VERSION 5.8 ;
BUSBITCHARS "[]" ;
DIVIDERCHAR "/" ;
UNITS
    DATABASE MICRONS 1000 ;
END UNITS

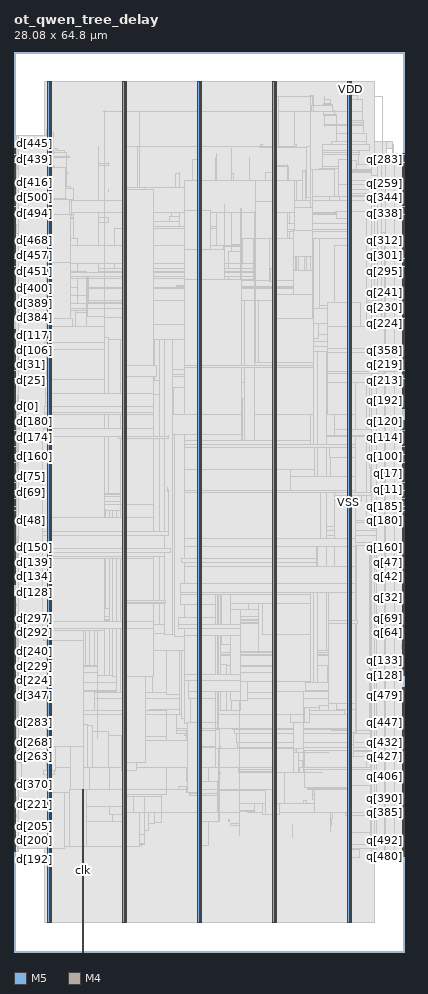
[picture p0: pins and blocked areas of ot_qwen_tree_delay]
MACRO ot_qwen_tree_delay
  FOREIGN ot_qwen_tree_delay 0 0 ;
  CLASS BLOCK ;
  SIZE 28.08 BY 64.8 ;
  PIN clk
    DIRECTION INPUT ;
    USE SIGNAL ;
    PORT
      LAYER M5 ;
        RECT  4.944 0 4.968 0.084 ;
    END
    PORT
      LAYER M5 ;
        RECT  4.944 0.016 4.968 11.701 ;
    END
  END clk
  PIN d[0]
    DIRECTION INPUT ;
    USE SIGNAL ;
    PORT
      LAYER M4 ;
        RECT  0 38.736 0.084 38.76 ;
    END
  END d[0]
  PIN d[100]
    DIRECTION INPUT ;
    USE SIGNAL ;
    PORT
      LAYER M4 ;
        RECT  0 42.192 0.084 42.216 ;
    END
  END d[100]
  PIN d[101]
    DIRECTION INPUT ;
    USE SIGNAL ;
    PORT
      LAYER M4 ;
        RECT  0 42.288 0.084 42.312 ;
    END
  END d[101]
  PIN d[102]
    DIRECTION INPUT ;
    USE SIGNAL ;
    PORT
      LAYER M4 ;
        RECT  0 42.384 0.084 42.408 ;
    END
  END d[102]
  PIN d[103]
    DIRECTION INPUT ;
    USE SIGNAL ;
    PORT
      LAYER M4 ;
        RECT  0 42.48 0.084 42.504 ;
    END
  END d[103]
  PIN d[104]
    DIRECTION INPUT ;
    USE SIGNAL ;
    PORT
      LAYER M4 ;
        RECT  0 42.576 0.084 42.6 ;
    END
  END d[104]
  PIN d[105]
    DIRECTION INPUT ;
    USE SIGNAL ;
    PORT
      LAYER M4 ;
        RECT  0 42.672 0.084 42.696 ;
    END
  END d[105]
  PIN d[106]
    DIRECTION INPUT ;
    USE SIGNAL ;
    PORT
      LAYER M4 ;
        RECT  0 42.768 0.084 42.792 ;
    END
  END d[106]
  PIN d[107]
    DIRECTION INPUT ;
    USE SIGNAL ;
    PORT
      LAYER M4 ;
        RECT  0 42.864 0.084 42.888 ;
    END
  END d[107]
  PIN d[108]
    DIRECTION INPUT ;
    USE SIGNAL ;
    PORT
      LAYER M4 ;
        RECT  0 42.96 0.084 42.984 ;
    END
  END d[108]
  PIN d[109]
    DIRECTION INPUT ;
    USE SIGNAL ;
    PORT
      LAYER M4 ;
        RECT  0 43.056 0.084 43.08 ;
    END
  END d[109]
  PIN d[10]
    DIRECTION INPUT ;
    USE SIGNAL ;
    PORT
      LAYER M4 ;
        RECT  0 39.696 0.084 39.72 ;
    END
  END d[10]
  PIN d[110]
    DIRECTION INPUT ;
    USE SIGNAL ;
    PORT
      LAYER M4 ;
        RECT  0 43.152 0.084 43.176 ;
    END
  END d[110]
  PIN d[111]
    DIRECTION INPUT ;
    USE SIGNAL ;
    PORT
      LAYER M4 ;
        RECT  0 43.248 0.084 43.272 ;
    END
  END d[111]
  PIN d[112]
    DIRECTION INPUT ;
    USE SIGNAL ;
    PORT
      LAYER M4 ;
        RECT  0 43.344 0.084 43.368 ;
    END
  END d[112]
  PIN d[113]
    DIRECTION INPUT ;
    USE SIGNAL ;
    PORT
      LAYER M4 ;
        RECT  0 43.44 0.084 43.464 ;
    END
  END d[113]
  PIN d[114]
    DIRECTION INPUT ;
    USE SIGNAL ;
    PORT
      LAYER M4 ;
        RECT  0 43.536 0.084 43.56 ;
    END
  END d[114]
  PIN d[115]
    DIRECTION INPUT ;
    USE SIGNAL ;
    PORT
      LAYER M4 ;
        RECT  0 43.632 0.084 43.656 ;
    END
  END d[115]
  PIN d[116]
    DIRECTION INPUT ;
    USE SIGNAL ;
    PORT
      LAYER M4 ;
        RECT  0 43.728 0.084 43.752 ;
    END
  END d[116]
  PIN d[117]
    DIRECTION INPUT ;
    USE SIGNAL ;
    PORT
      LAYER M4 ;
        RECT  0 43.824 0.084 43.848 ;
    END
  END d[117]
  PIN d[118]
    DIRECTION INPUT ;
    USE SIGNAL ;
    PORT
      LAYER M4 ;
        RECT  0 43.92 0.084 43.944 ;
    END
  END d[118]
  PIN d[119]
    DIRECTION INPUT ;
    USE SIGNAL ;
    PORT
      LAYER M4 ;
        RECT  0 44.016 0.084 44.04 ;
    END
  END d[119]
  PIN d[11]
    DIRECTION INPUT ;
    USE SIGNAL ;
    PORT
      LAYER M4 ;
        RECT  0 39.792 0.084 39.816 ;
    END
  END d[11]
  PIN d[120]
    DIRECTION INPUT ;
    USE SIGNAL ;
    PORT
      LAYER M4 ;
        RECT  0 44.112 0.084 44.136 ;
    END
  END d[120]
  PIN d[121]
    DIRECTION INPUT ;
    USE SIGNAL ;
    PORT
      LAYER M4 ;
        RECT  0 44.208 0.084 44.232 ;
    END
  END d[121]
  PIN d[122]
    DIRECTION INPUT ;
    USE SIGNAL ;
    PORT
      LAYER M4 ;
        RECT  0 44.304 0.084 44.328 ;
    END
  END d[122]
  PIN d[123]
    DIRECTION INPUT ;
    USE SIGNAL ;
    PORT
      LAYER M4 ;
        RECT  0 44.4 0.084 44.424 ;
    END
  END d[123]
  PIN d[124]
    DIRECTION INPUT ;
    USE SIGNAL ;
    PORT
      LAYER M4 ;
        RECT  0 44.496 0.084 44.52 ;
    END
  END d[124]
  PIN d[125]
    DIRECTION INPUT ;
    USE SIGNAL ;
    PORT
      LAYER M4 ;
        RECT  0 44.592 0.084 44.616 ;
    END
  END d[125]
  PIN d[126]
    DIRECTION INPUT ;
    USE SIGNAL ;
    PORT
      LAYER M4 ;
        RECT  0 44.688 0.084 44.712 ;
    END
  END d[126]
  PIN d[127]
    DIRECTION INPUT ;
    USE SIGNAL ;
    PORT
      LAYER M4 ;
        RECT  0 44.784 0.084 44.808 ;
    END
  END d[127]
  PIN d[128]
    DIRECTION INPUT ;
    USE SIGNAL ;
    PORT
      LAYER M4 ;
        RECT  0 26.448 0.084 26.472 ;
    END
  END d[128]
  PIN d[129]
    DIRECTION INPUT ;
    USE SIGNAL ;
    PORT
      LAYER M4 ;
        RECT  0 26.544 0.084 26.568 ;
    END
  END d[129]
  PIN d[12]
    DIRECTION INPUT ;
    USE SIGNAL ;
    PORT
      LAYER M4 ;
        RECT  0 39.888 0.084 39.912 ;
    END
  END d[12]
  PIN d[130]
    DIRECTION INPUT ;
    USE SIGNAL ;
    PORT
      LAYER M4 ;
        RECT  0 26.64 0.084 26.664 ;
    END
  END d[130]
  PIN d[131]
    DIRECTION INPUT ;
    USE SIGNAL ;
    PORT
      LAYER M4 ;
        RECT  0 26.736 0.084 26.76 ;
    END
  END d[131]
  PIN d[132]
    DIRECTION INPUT ;
    USE SIGNAL ;
    PORT
      LAYER M4 ;
        RECT  0 26.832 0.084 26.856 ;
    END
  END d[132]
  PIN d[133]
    DIRECTION INPUT ;
    USE SIGNAL ;
    PORT
      LAYER M4 ;
        RECT  0 26.928 0.084 26.952 ;
    END
  END d[133]
  PIN d[134]
    DIRECTION INPUT ;
    USE SIGNAL ;
    PORT
      LAYER M4 ;
        RECT  0 27.024 0.084 27.048 ;
    END
  END d[134]
  PIN d[135]
    DIRECTION INPUT ;
    USE SIGNAL ;
    PORT
      LAYER M4 ;
        RECT  0 27.12 0.084 27.144 ;
    END
  END d[135]
  PIN d[136]
    DIRECTION INPUT ;
    USE SIGNAL ;
    PORT
      LAYER M4 ;
        RECT  0 27.216 0.084 27.24 ;
    END
  END d[136]
  PIN d[137]
    DIRECTION INPUT ;
    USE SIGNAL ;
    PORT
      LAYER M4 ;
        RECT  0 27.312 0.084 27.336 ;
    END
  END d[137]
  PIN d[138]
    DIRECTION INPUT ;
    USE SIGNAL ;
    PORT
      LAYER M4 ;
        RECT  0 27.408 0.084 27.432 ;
    END
  END d[138]
  PIN d[139]
    DIRECTION INPUT ;
    USE SIGNAL ;
    PORT
      LAYER M4 ;
        RECT  0 27.504 0.084 27.528 ;
    END
  END d[139]
  PIN d[13]
    DIRECTION INPUT ;
    USE SIGNAL ;
    PORT
      LAYER M4 ;
        RECT  0 39.984 0.084 40.008 ;
    END
  END d[13]
  PIN d[140]
    DIRECTION INPUT ;
    USE SIGNAL ;
    PORT
      LAYER M4 ;
        RECT  0 27.6 0.084 27.624 ;
    END
  END d[140]
  PIN d[141]
    DIRECTION INPUT ;
    USE SIGNAL ;
    PORT
      LAYER M4 ;
        RECT  0 27.696 0.084 27.72 ;
    END
  END d[141]
  PIN d[142]
    DIRECTION INPUT ;
    USE SIGNAL ;
    PORT
      LAYER M4 ;
        RECT  0 27.792 0.084 27.816 ;
    END
  END d[142]
  PIN d[143]
    DIRECTION INPUT ;
    USE SIGNAL ;
    PORT
      LAYER M4 ;
        RECT  0 27.888 0.084 27.912 ;
    END
  END d[143]
  PIN d[144]
    DIRECTION INPUT ;
    USE SIGNAL ;
    PORT
      LAYER M4 ;
        RECT  0 27.984 0.084 28.008 ;
    END
  END d[144]
  PIN d[145]
    DIRECTION INPUT ;
    USE SIGNAL ;
    PORT
      LAYER M4 ;
        RECT  0 28.08 0.084 28.104 ;
    END
  END d[145]
  PIN d[146]
    DIRECTION INPUT ;
    USE SIGNAL ;
    PORT
      LAYER M4 ;
        RECT  0 28.176 0.084 28.2 ;
    END
  END d[146]
  PIN d[147]
    DIRECTION INPUT ;
    USE SIGNAL ;
    PORT
      LAYER M4 ;
        RECT  0 28.272 0.084 28.296 ;
    END
  END d[147]
  PIN d[148]
    DIRECTION INPUT ;
    USE SIGNAL ;
    PORT
      LAYER M4 ;
        RECT  0 28.368 0.084 28.392 ;
    END
  END d[148]
  PIN d[149]
    DIRECTION INPUT ;
    USE SIGNAL ;
    PORT
      LAYER M4 ;
        RECT  0 28.464 0.084 28.488 ;
    END
  END d[149]
  PIN d[14]
    DIRECTION INPUT ;
    USE SIGNAL ;
    PORT
      LAYER M4 ;
        RECT  0 40.08 0.084 40.104 ;
    END
  END d[14]
  PIN d[150]
    DIRECTION INPUT ;
    USE SIGNAL ;
    PORT
      LAYER M4 ;
        RECT  0 28.56 0.084 28.584 ;
    END
  END d[150]
  PIN d[151]
    DIRECTION INPUT ;
    USE SIGNAL ;
    PORT
      LAYER M4 ;
        RECT  0 28.656 0.084 28.68 ;
    END
  END d[151]
  PIN d[152]
    DIRECTION INPUT ;
    USE SIGNAL ;
    PORT
      LAYER M4 ;
        RECT  0 28.752 0.084 28.776 ;
    END
  END d[152]
  PIN d[153]
    DIRECTION INPUT ;
    USE SIGNAL ;
    PORT
      LAYER M4 ;
        RECT  0 28.848 0.084 28.872 ;
    END
  END d[153]
  PIN d[154]
    DIRECTION INPUT ;
    USE SIGNAL ;
    PORT
      LAYER M4 ;
        RECT  0 28.944 0.084 28.968 ;
    END
  END d[154]
  PIN d[155]
    DIRECTION INPUT ;
    USE SIGNAL ;
    PORT
      LAYER M4 ;
        RECT  0 29.04 0.084 29.064 ;
    END
  END d[155]
  PIN d[156]
    DIRECTION INPUT ;
    USE SIGNAL ;
    PORT
      LAYER M4 ;
        RECT  0 29.136 0.084 29.16 ;
    END
  END d[156]
  PIN d[157]
    DIRECTION INPUT ;
    USE SIGNAL ;
    PORT
      LAYER M4 ;
        RECT  0 29.232 0.084 29.256 ;
    END
  END d[157]
  PIN d[158]
    DIRECTION INPUT ;
    USE SIGNAL ;
    PORT
      LAYER M4 ;
        RECT  0 29.328 0.084 29.352 ;
    END
  END d[158]
  PIN d[159]
    DIRECTION INPUT ;
    USE SIGNAL ;
    PORT
      LAYER M4 ;
        RECT  0 29.424 0.084 29.448 ;
    END
  END d[159]
  PIN d[15]
    DIRECTION INPUT ;
    USE SIGNAL ;
    PORT
      LAYER M4 ;
        RECT  0 40.176 0.084 40.2 ;
    END
  END d[15]
  PIN d[160]
    DIRECTION INPUT ;
    USE SIGNAL ;
    PORT
      LAYER M4 ;
        RECT  0 35.664 0.084 35.688 ;
    END
  END d[160]
  PIN d[161]
    DIRECTION INPUT ;
    USE SIGNAL ;
    PORT
      LAYER M4 ;
        RECT  0 35.76 0.084 35.784 ;
    END
  END d[161]
  PIN d[162]
    DIRECTION INPUT ;
    USE SIGNAL ;
    PORT
      LAYER M4 ;
        RECT  0 35.856 0.084 35.88 ;
    END
  END d[162]
  PIN d[163]
    DIRECTION INPUT ;
    USE SIGNAL ;
    PORT
      LAYER M4 ;
        RECT  0 35.952 0.084 35.976 ;
    END
  END d[163]
  PIN d[164]
    DIRECTION INPUT ;
    USE SIGNAL ;
    PORT
      LAYER M4 ;
        RECT  0 36.048 0.084 36.072 ;
    END
  END d[164]
  PIN d[165]
    DIRECTION INPUT ;
    USE SIGNAL ;
    PORT
      LAYER M4 ;
        RECT  0 36.144 0.084 36.168 ;
    END
  END d[165]
  PIN d[166]
    DIRECTION INPUT ;
    USE SIGNAL ;
    PORT
      LAYER M4 ;
        RECT  0 36.24 0.084 36.264 ;
    END
  END d[166]
  PIN d[167]
    DIRECTION INPUT ;
    USE SIGNAL ;
    PORT
      LAYER M4 ;
        RECT  0 36.336 0.084 36.36 ;
    END
  END d[167]
  PIN d[168]
    DIRECTION INPUT ;
    USE SIGNAL ;
    PORT
      LAYER M4 ;
        RECT  0 36.432 0.084 36.456 ;
    END
  END d[168]
  PIN d[169]
    DIRECTION INPUT ;
    USE SIGNAL ;
    PORT
      LAYER M4 ;
        RECT  0 36.528 0.084 36.552 ;
    END
  END d[169]
  PIN d[16]
    DIRECTION INPUT ;
    USE SIGNAL ;
    PORT
      LAYER M4 ;
        RECT  0 40.272 0.084 40.296 ;
    END
  END d[16]
  PIN d[170]
    DIRECTION INPUT ;
    USE SIGNAL ;
    PORT
      LAYER M4 ;
        RECT  0 36.624 0.084 36.648 ;
    END
  END d[170]
  PIN d[171]
    DIRECTION INPUT ;
    USE SIGNAL ;
    PORT
      LAYER M4 ;
        RECT  0 36.72 0.084 36.744 ;
    END
  END d[171]
  PIN d[172]
    DIRECTION INPUT ;
    USE SIGNAL ;
    PORT
      LAYER M4 ;
        RECT  0 36.816 0.084 36.84 ;
    END
  END d[172]
  PIN d[173]
    DIRECTION INPUT ;
    USE SIGNAL ;
    PORT
      LAYER M4 ;
        RECT  0 36.912 0.084 36.936 ;
    END
  END d[173]
  PIN d[174]
    DIRECTION INPUT ;
    USE SIGNAL ;
    PORT
      LAYER M4 ;
        RECT  0 37.008 0.084 37.032 ;
    END
  END d[174]
  PIN d[175]
    DIRECTION INPUT ;
    USE SIGNAL ;
    PORT
      LAYER M4 ;
        RECT  0 37.104 0.084 37.128 ;
    END
  END d[175]
  PIN d[176]
    DIRECTION INPUT ;
    USE SIGNAL ;
    PORT
      LAYER M4 ;
        RECT  0 37.2 0.084 37.224 ;
    END
  END d[176]
  PIN d[177]
    DIRECTION INPUT ;
    USE SIGNAL ;
    PORT
      LAYER M4 ;
        RECT  0 37.296 0.084 37.32 ;
    END
  END d[177]
  PIN d[178]
    DIRECTION INPUT ;
    USE SIGNAL ;
    PORT
      LAYER M4 ;
        RECT  0 37.392 0.084 37.416 ;
    END
  END d[178]
  PIN d[179]
    DIRECTION INPUT ;
    USE SIGNAL ;
    PORT
      LAYER M4 ;
        RECT  0 37.488 0.084 37.512 ;
    END
  END d[179]
  PIN d[17]
    DIRECTION INPUT ;
    USE SIGNAL ;
    PORT
      LAYER M4 ;
        RECT  0 40.368 0.084 40.392 ;
    END
  END d[17]
  PIN d[180]
    DIRECTION INPUT ;
    USE SIGNAL ;
    PORT
      LAYER M4 ;
        RECT  0 37.584 0.084 37.608 ;
    END
  END d[180]
  PIN d[181]
    DIRECTION INPUT ;
    USE SIGNAL ;
    PORT
      LAYER M4 ;
        RECT  0 37.68 0.084 37.704 ;
    END
  END d[181]
  PIN d[182]
    DIRECTION INPUT ;
    USE SIGNAL ;
    PORT
      LAYER M4 ;
        RECT  0 37.776 0.084 37.8 ;
    END
  END d[182]
  PIN d[183]
    DIRECTION INPUT ;
    USE SIGNAL ;
    PORT
      LAYER M4 ;
        RECT  0 37.872 0.084 37.896 ;
    END
  END d[183]
  PIN d[184]
    DIRECTION INPUT ;
    USE SIGNAL ;
    PORT
      LAYER M4 ;
        RECT  0 37.968 0.084 37.992 ;
    END
  END d[184]
  PIN d[185]
    DIRECTION INPUT ;
    USE SIGNAL ;
    PORT
      LAYER M4 ;
        RECT  0 38.064 0.084 38.088 ;
    END
  END d[185]
  PIN d[186]
    DIRECTION INPUT ;
    USE SIGNAL ;
    PORT
      LAYER M4 ;
        RECT  0 38.16 0.084 38.184 ;
    END
  END d[186]
  PIN d[187]
    DIRECTION INPUT ;
    USE SIGNAL ;
    PORT
      LAYER M4 ;
        RECT  0 38.256 0.084 38.28 ;
    END
  END d[187]
  PIN d[188]
    DIRECTION INPUT ;
    USE SIGNAL ;
    PORT
      LAYER M4 ;
        RECT  0 38.352 0.084 38.376 ;
    END
  END d[188]
  PIN d[189]
    DIRECTION INPUT ;
    USE SIGNAL ;
    PORT
      LAYER M4 ;
        RECT  0 38.448 0.084 38.472 ;
    END
  END d[189]
  PIN d[18]
    DIRECTION INPUT ;
    USE SIGNAL ;
    PORT
      LAYER M4 ;
        RECT  0 40.464 0.084 40.488 ;
    END
  END d[18]
  PIN d[190]
    DIRECTION INPUT ;
    USE SIGNAL ;
    PORT
      LAYER M4 ;
        RECT  0 38.544 0.084 38.568 ;
    END
  END d[190]
  PIN d[191]
    DIRECTION INPUT ;
    USE SIGNAL ;
    PORT
      LAYER M4 ;
        RECT  0 38.64 0.084 38.664 ;
    END
  END d[191]
  PIN d[192]
    DIRECTION INPUT ;
    USE SIGNAL ;
    PORT
      LAYER M4 ;
        RECT  0 7.248 0.084 7.272 ;
    END
  END d[192]
  PIN d[193]
    DIRECTION INPUT ;
    USE SIGNAL ;
    PORT
      LAYER M4 ;
        RECT  0 7.344 0.084 7.368 ;
    END
  END d[193]
  PIN d[194]
    DIRECTION INPUT ;
    USE SIGNAL ;
    PORT
      LAYER M4 ;
        RECT  0 7.44 0.084 7.464 ;
    END
  END d[194]
  PIN d[195]
    DIRECTION INPUT ;
    USE SIGNAL ;
    PORT
      LAYER M4 ;
        RECT  0 7.536 0.084 7.56 ;
    END
  END d[195]
  PIN d[196]
    DIRECTION INPUT ;
    USE SIGNAL ;
    PORT
      LAYER M4 ;
        RECT  0 7.632 0.084 7.656 ;
    END
  END d[196]
  PIN d[197]
    DIRECTION INPUT ;
    USE SIGNAL ;
    PORT
      LAYER M4 ;
        RECT  0 7.728 0.084 7.752 ;
    END
  END d[197]
  PIN d[198]
    DIRECTION INPUT ;
    USE SIGNAL ;
    PORT
      LAYER M4 ;
        RECT  0 7.824 0.084 7.848 ;
    END
  END d[198]
  PIN d[199]
    DIRECTION INPUT ;
    USE SIGNAL ;
    PORT
      LAYER M4 ;
        RECT  0 7.92 0.084 7.944 ;
    END
  END d[199]
  PIN d[19]
    DIRECTION INPUT ;
    USE SIGNAL ;
    PORT
      LAYER M4 ;
        RECT  0 40.56 0.084 40.584 ;
    END
  END d[19]
  PIN d[1]
    DIRECTION INPUT ;
    USE SIGNAL ;
    PORT
      LAYER M4 ;
        RECT  0 38.832 0.084 38.856 ;
    END
  END d[1]
  PIN d[200]
    DIRECTION INPUT ;
    USE SIGNAL ;
    PORT
      LAYER M4 ;
        RECT  0 8.016 0.084 8.04 ;
    END
  END d[200]
  PIN d[201]
    DIRECTION INPUT ;
    USE SIGNAL ;
    PORT
      LAYER M4 ;
        RECT  0 8.112 0.084 8.136 ;
    END
  END d[201]
  PIN d[202]
    DIRECTION INPUT ;
    USE SIGNAL ;
    PORT
      LAYER M4 ;
        RECT  0 8.208 0.084 8.232 ;
    END
  END d[202]
  PIN d[203]
    DIRECTION INPUT ;
    USE SIGNAL ;
    PORT
      LAYER M4 ;
        RECT  0 8.304 0.084 8.328 ;
    END
  END d[203]
  PIN d[204]
    DIRECTION INPUT ;
    USE SIGNAL ;
    PORT
      LAYER M4 ;
        RECT  0 8.4 0.084 8.424 ;
    END
  END d[204]
  PIN d[205]
    DIRECTION INPUT ;
    USE SIGNAL ;
    PORT
      LAYER M4 ;
        RECT  0 8.496 0.084 8.52 ;
    END
  END d[205]
  PIN d[206]
    DIRECTION INPUT ;
    USE SIGNAL ;
    PORT
      LAYER M4 ;
        RECT  0 8.592 0.084 8.616 ;
    END
  END d[206]
  PIN d[207]
    DIRECTION INPUT ;
    USE SIGNAL ;
    PORT
      LAYER M4 ;
        RECT  0 8.688 0.084 8.712 ;
    END
  END d[207]
  PIN d[208]
    DIRECTION INPUT ;
    USE SIGNAL ;
    PORT
      LAYER M4 ;
        RECT  0 8.784 0.084 8.808 ;
    END
  END d[208]
  PIN d[209]
    DIRECTION INPUT ;
    USE SIGNAL ;
    PORT
      LAYER M4 ;
        RECT  0 8.88 0.084 8.904 ;
    END
  END d[209]
  PIN d[20]
    DIRECTION INPUT ;
    USE SIGNAL ;
    PORT
      LAYER M4 ;
        RECT  0 40.656 0.084 40.68 ;
    END
  END d[20]
  PIN d[210]
    DIRECTION INPUT ;
    USE SIGNAL ;
    PORT
      LAYER M4 ;
        RECT  0 8.976 0.084 9 ;
    END
  END d[210]
  PIN d[211]
    DIRECTION INPUT ;
    USE SIGNAL ;
    PORT
      LAYER M4 ;
        RECT  0 9.072 0.084 9.096 ;
    END
  END d[211]
  PIN d[212]
    DIRECTION INPUT ;
    USE SIGNAL ;
    PORT
      LAYER M4 ;
        RECT  0 9.168 0.084 9.192 ;
    END
  END d[212]
  PIN d[213]
    DIRECTION INPUT ;
    USE SIGNAL ;
    PORT
      LAYER M4 ;
        RECT  0 9.264 0.084 9.288 ;
    END
  END d[213]
  PIN d[214]
    DIRECTION INPUT ;
    USE SIGNAL ;
    PORT
      LAYER M4 ;
        RECT  0 9.36 0.084 9.384 ;
    END
  END d[214]
  PIN d[215]
    DIRECTION INPUT ;
    USE SIGNAL ;
    PORT
      LAYER M4 ;
        RECT  0 9.456 0.084 9.48 ;
    END
  END d[215]
  PIN d[216]
    DIRECTION INPUT ;
    USE SIGNAL ;
    PORT
      LAYER M4 ;
        RECT  0 9.552 0.084 9.576 ;
    END
  END d[216]
  PIN d[217]
    DIRECTION INPUT ;
    USE SIGNAL ;
    PORT
      LAYER M4 ;
        RECT  0 9.648 0.084 9.672 ;
    END
  END d[217]
  PIN d[218]
    DIRECTION INPUT ;
    USE SIGNAL ;
    PORT
      LAYER M4 ;
        RECT  0 9.744 0.084 9.768 ;
    END
  END d[218]
  PIN d[219]
    DIRECTION INPUT ;
    USE SIGNAL ;
    PORT
      LAYER M4 ;
        RECT  0 9.84 0.084 9.864 ;
    END
  END d[219]
  PIN d[21]
    DIRECTION INPUT ;
    USE SIGNAL ;
    PORT
      LAYER M4 ;
        RECT  0 40.752 0.084 40.776 ;
    END
  END d[21]
  PIN d[220]
    DIRECTION INPUT ;
    USE SIGNAL ;
    PORT
      LAYER M4 ;
        RECT  0 9.936 0.084 9.96 ;
    END
  END d[220]
  PIN d[221]
    DIRECTION INPUT ;
    USE SIGNAL ;
    PORT
      LAYER M4 ;
        RECT  0 10.032 0.084 10.056 ;
    END
  END d[221]
  PIN d[222]
    DIRECTION INPUT ;
    USE SIGNAL ;
    PORT
      LAYER M4 ;
        RECT  0 10.128 0.084 10.152 ;
    END
  END d[222]
  PIN d[223]
    DIRECTION INPUT ;
    USE SIGNAL ;
    PORT
      LAYER M4 ;
        RECT  0 10.224 0.084 10.248 ;
    END
  END d[223]
  PIN d[224]
    DIRECTION INPUT ;
    USE SIGNAL ;
    PORT
      LAYER M4 ;
        RECT  0 19.536 0.084 19.56 ;
    END
  END d[224]
  PIN d[225]
    DIRECTION INPUT ;
    USE SIGNAL ;
    PORT
      LAYER M4 ;
        RECT  0 19.632 0.084 19.656 ;
    END
  END d[225]
  PIN d[226]
    DIRECTION INPUT ;
    USE SIGNAL ;
    PORT
      LAYER M4 ;
        RECT  0 19.728 0.084 19.752 ;
    END
  END d[226]
  PIN d[227]
    DIRECTION INPUT ;
    USE SIGNAL ;
    PORT
      LAYER M4 ;
        RECT  0 19.824 0.084 19.848 ;
    END
  END d[227]
  PIN d[228]
    DIRECTION INPUT ;
    USE SIGNAL ;
    PORT
      LAYER M4 ;
        RECT  0 19.92 0.084 19.944 ;
    END
  END d[228]
  PIN d[229]
    DIRECTION INPUT ;
    USE SIGNAL ;
    PORT
      LAYER M4 ;
        RECT  0 20.016 0.084 20.04 ;
    END
  END d[229]
  PIN d[22]
    DIRECTION INPUT ;
    USE SIGNAL ;
    PORT
      LAYER M4 ;
        RECT  0 40.848 0.084 40.872 ;
    END
  END d[22]
  PIN d[230]
    DIRECTION INPUT ;
    USE SIGNAL ;
    PORT
      LAYER M4 ;
        RECT  0 20.112 0.084 20.136 ;
    END
  END d[230]
  PIN d[231]
    DIRECTION INPUT ;
    USE SIGNAL ;
    PORT
      LAYER M4 ;
        RECT  0 20.208 0.084 20.232 ;
    END
  END d[231]
  PIN d[232]
    DIRECTION INPUT ;
    USE SIGNAL ;
    PORT
      LAYER M4 ;
        RECT  0 20.304 0.084 20.328 ;
    END
  END d[232]
  PIN d[233]
    DIRECTION INPUT ;
    USE SIGNAL ;
    PORT
      LAYER M4 ;
        RECT  0 20.4 0.084 20.424 ;
    END
  END d[233]
  PIN d[234]
    DIRECTION INPUT ;
    USE SIGNAL ;
    PORT
      LAYER M4 ;
        RECT  0 20.496 0.084 20.52 ;
    END
  END d[234]
  PIN d[235]
    DIRECTION INPUT ;
    USE SIGNAL ;
    PORT
      LAYER M4 ;
        RECT  0 20.592 0.084 20.616 ;
    END
  END d[235]
  PIN d[236]
    DIRECTION INPUT ;
    USE SIGNAL ;
    PORT
      LAYER M4 ;
        RECT  0 20.688 0.084 20.712 ;
    END
  END d[236]
  PIN d[237]
    DIRECTION INPUT ;
    USE SIGNAL ;
    PORT
      LAYER M4 ;
        RECT  0 20.784 0.084 20.808 ;
    END
  END d[237]
  PIN d[238]
    DIRECTION INPUT ;
    USE SIGNAL ;
    PORT
      LAYER M4 ;
        RECT  0 20.88 0.084 20.904 ;
    END
  END d[238]
  PIN d[239]
    DIRECTION INPUT ;
    USE SIGNAL ;
    PORT
      LAYER M4 ;
        RECT  0 20.976 0.084 21 ;
    END
  END d[239]
  PIN d[23]
    DIRECTION INPUT ;
    USE SIGNAL ;
    PORT
      LAYER M4 ;
        RECT  0 40.944 0.084 40.968 ;
    END
  END d[23]
  PIN d[240]
    DIRECTION INPUT ;
    USE SIGNAL ;
    PORT
      LAYER M4 ;
        RECT  0 21.072 0.084 21.096 ;
    END
  END d[240]
  PIN d[241]
    DIRECTION INPUT ;
    USE SIGNAL ;
    PORT
      LAYER M4 ;
        RECT  0 21.168 0.084 21.192 ;
    END
  END d[241]
  PIN d[242]
    DIRECTION INPUT ;
    USE SIGNAL ;
    PORT
      LAYER M4 ;
        RECT  0 21.264 0.084 21.288 ;
    END
  END d[242]
  PIN d[243]
    DIRECTION INPUT ;
    USE SIGNAL ;
    PORT
      LAYER M4 ;
        RECT  0 21.36 0.084 21.384 ;
    END
  END d[243]
  PIN d[244]
    DIRECTION INPUT ;
    USE SIGNAL ;
    PORT
      LAYER M4 ;
        RECT  0 21.456 0.084 21.48 ;
    END
  END d[244]
  PIN d[245]
    DIRECTION INPUT ;
    USE SIGNAL ;
    PORT
      LAYER M4 ;
        RECT  0 21.552 0.084 21.576 ;
    END
  END d[245]
  PIN d[246]
    DIRECTION INPUT ;
    USE SIGNAL ;
    PORT
      LAYER M4 ;
        RECT  0 21.648 0.084 21.672 ;
    END
  END d[246]
  PIN d[247]
    DIRECTION INPUT ;
    USE SIGNAL ;
    PORT
      LAYER M4 ;
        RECT  0 21.744 0.084 21.768 ;
    END
  END d[247]
  PIN d[248]
    DIRECTION INPUT ;
    USE SIGNAL ;
    PORT
      LAYER M4 ;
        RECT  0 21.84 0.084 21.864 ;
    END
  END d[248]
  PIN d[249]
    DIRECTION INPUT ;
    USE SIGNAL ;
    PORT
      LAYER M4 ;
        RECT  0 21.936 0.084 21.96 ;
    END
  END d[249]
  PIN d[24]
    DIRECTION INPUT ;
    USE SIGNAL ;
    PORT
      LAYER M4 ;
        RECT  0 41.04 0.084 41.064 ;
    END
  END d[24]
  PIN d[250]
    DIRECTION INPUT ;
    USE SIGNAL ;
    PORT
      LAYER M4 ;
        RECT  0 22.032 0.084 22.056 ;
    END
  END d[250]
  PIN d[251]
    DIRECTION INPUT ;
    USE SIGNAL ;
    PORT
      LAYER M4 ;
        RECT  0 22.128 0.084 22.152 ;
    END
  END d[251]
  PIN d[252]
    DIRECTION INPUT ;
    USE SIGNAL ;
    PORT
      LAYER M4 ;
        RECT  0 22.224 0.084 22.248 ;
    END
  END d[252]
  PIN d[253]
    DIRECTION INPUT ;
    USE SIGNAL ;
    PORT
      LAYER M4 ;
        RECT  0 22.32 0.084 22.344 ;
    END
  END d[253]
  PIN d[254]
    DIRECTION INPUT ;
    USE SIGNAL ;
    PORT
      LAYER M4 ;
        RECT  0 22.416 0.084 22.44 ;
    END
  END d[254]
  PIN d[255]
    DIRECTION INPUT ;
    USE SIGNAL ;
    PORT
      LAYER M4 ;
        RECT  0 22.512 0.084 22.536 ;
    END
  END d[255]
  PIN d[256]
    DIRECTION INPUT ;
    USE SIGNAL ;
    PORT
      LAYER M4 ;
        RECT  0 13.392 0.084 13.416 ;
    END
  END d[256]
  PIN d[257]
    DIRECTION INPUT ;
    USE SIGNAL ;
    PORT
      LAYER M4 ;
        RECT  0 13.488 0.084 13.512 ;
    END
  END d[257]
  PIN d[258]
    DIRECTION INPUT ;
    USE SIGNAL ;
    PORT
      LAYER M4 ;
        RECT  0 13.584 0.084 13.608 ;
    END
  END d[258]
  PIN d[259]
    DIRECTION INPUT ;
    USE SIGNAL ;
    PORT
      LAYER M4 ;
        RECT  0 13.68 0.084 13.704 ;
    END
  END d[259]
  PIN d[25]
    DIRECTION INPUT ;
    USE SIGNAL ;
    PORT
      LAYER M4 ;
        RECT  0 41.136 0.084 41.16 ;
    END
  END d[25]
  PIN d[260]
    DIRECTION INPUT ;
    USE SIGNAL ;
    PORT
      LAYER M4 ;
        RECT  0 13.776 0.084 13.8 ;
    END
  END d[260]
  PIN d[261]
    DIRECTION INPUT ;
    USE SIGNAL ;
    PORT
      LAYER M4 ;
        RECT  0 13.872 0.084 13.896 ;
    END
  END d[261]
  PIN d[262]
    DIRECTION INPUT ;
    USE SIGNAL ;
    PORT
      LAYER M4 ;
        RECT  0 13.968 0.084 13.992 ;
    END
  END d[262]
  PIN d[263]
    DIRECTION INPUT ;
    USE SIGNAL ;
    PORT
      LAYER M4 ;
        RECT  0 14.064 0.084 14.088 ;
    END
  END d[263]
  PIN d[264]
    DIRECTION INPUT ;
    USE SIGNAL ;
    PORT
      LAYER M4 ;
        RECT  0 14.16 0.084 14.184 ;
    END
  END d[264]
  PIN d[265]
    DIRECTION INPUT ;
    USE SIGNAL ;
    PORT
      LAYER M4 ;
        RECT  0 14.256 0.084 14.28 ;
    END
  END d[265]
  PIN d[266]
    DIRECTION INPUT ;
    USE SIGNAL ;
    PORT
      LAYER M4 ;
        RECT  0 14.352 0.084 14.376 ;
    END
  END d[266]
  PIN d[267]
    DIRECTION INPUT ;
    USE SIGNAL ;
    PORT
      LAYER M4 ;
        RECT  0 14.448 0.084 14.472 ;
    END
  END d[267]
  PIN d[268]
    DIRECTION INPUT ;
    USE SIGNAL ;
    PORT
      LAYER M4 ;
        RECT  0 14.544 0.084 14.568 ;
    END
  END d[268]
  PIN d[269]
    DIRECTION INPUT ;
    USE SIGNAL ;
    PORT
      LAYER M4 ;
        RECT  0 14.64 0.084 14.664 ;
    END
  END d[269]
  PIN d[26]
    DIRECTION INPUT ;
    USE SIGNAL ;
    PORT
      LAYER M4 ;
        RECT  0 41.232 0.084 41.256 ;
    END
  END d[26]
  PIN d[270]
    DIRECTION INPUT ;
    USE SIGNAL ;
    PORT
      LAYER M4 ;
        RECT  0 14.736 0.084 14.76 ;
    END
  END d[270]
  PIN d[271]
    DIRECTION INPUT ;
    USE SIGNAL ;
    PORT
      LAYER M4 ;
        RECT  0 14.832 0.084 14.856 ;
    END
  END d[271]
  PIN d[272]
    DIRECTION INPUT ;
    USE SIGNAL ;
    PORT
      LAYER M4 ;
        RECT  0 14.928 0.084 14.952 ;
    END
  END d[272]
  PIN d[273]
    DIRECTION INPUT ;
    USE SIGNAL ;
    PORT
      LAYER M4 ;
        RECT  0 15.024 0.084 15.048 ;
    END
  END d[273]
  PIN d[274]
    DIRECTION INPUT ;
    USE SIGNAL ;
    PORT
      LAYER M4 ;
        RECT  0 15.12 0.084 15.144 ;
    END
  END d[274]
  PIN d[275]
    DIRECTION INPUT ;
    USE SIGNAL ;
    PORT
      LAYER M4 ;
        RECT  0 15.216 0.084 15.24 ;
    END
  END d[275]
  PIN d[276]
    DIRECTION INPUT ;
    USE SIGNAL ;
    PORT
      LAYER M4 ;
        RECT  0 15.312 0.084 15.336 ;
    END
  END d[276]
  PIN d[277]
    DIRECTION INPUT ;
    USE SIGNAL ;
    PORT
      LAYER M4 ;
        RECT  0 15.408 0.084 15.432 ;
    END
  END d[277]
  PIN d[278]
    DIRECTION INPUT ;
    USE SIGNAL ;
    PORT
      LAYER M4 ;
        RECT  0 15.504 0.084 15.528 ;
    END
  END d[278]
  PIN d[279]
    DIRECTION INPUT ;
    USE SIGNAL ;
    PORT
      LAYER M4 ;
        RECT  0 15.6 0.084 15.624 ;
    END
  END d[279]
  PIN d[27]
    DIRECTION INPUT ;
    USE SIGNAL ;
    PORT
      LAYER M4 ;
        RECT  0 41.328 0.084 41.352 ;
    END
  END d[27]
  PIN d[280]
    DIRECTION INPUT ;
    USE SIGNAL ;
    PORT
      LAYER M4 ;
        RECT  0 15.696 0.084 15.72 ;
    END
  END d[280]
  PIN d[281]
    DIRECTION INPUT ;
    USE SIGNAL ;
    PORT
      LAYER M4 ;
        RECT  0 15.792 0.084 15.816 ;
    END
  END d[281]
  PIN d[282]
    DIRECTION INPUT ;
    USE SIGNAL ;
    PORT
      LAYER M4 ;
        RECT  0 15.888 0.084 15.912 ;
    END
  END d[282]
  PIN d[283]
    DIRECTION INPUT ;
    USE SIGNAL ;
    PORT
      LAYER M4 ;
        RECT  0 15.984 0.084 16.008 ;
    END
  END d[283]
  PIN d[284]
    DIRECTION INPUT ;
    USE SIGNAL ;
    PORT
      LAYER M4 ;
        RECT  0 16.08 0.084 16.104 ;
    END
  END d[284]
  PIN d[285]
    DIRECTION INPUT ;
    USE SIGNAL ;
    PORT
      LAYER M4 ;
        RECT  0 16.176 0.084 16.2 ;
    END
  END d[285]
  PIN d[286]
    DIRECTION INPUT ;
    USE SIGNAL ;
    PORT
      LAYER M4 ;
        RECT  0 16.272 0.084 16.296 ;
    END
  END d[286]
  PIN d[287]
    DIRECTION INPUT ;
    USE SIGNAL ;
    PORT
      LAYER M4 ;
        RECT  0 16.368 0.084 16.392 ;
    END
  END d[287]
  PIN d[288]
    DIRECTION INPUT ;
    USE SIGNAL ;
    PORT
      LAYER M4 ;
        RECT  0 22.608 0.084 22.632 ;
    END
  END d[288]
  PIN d[289]
    DIRECTION INPUT ;
    USE SIGNAL ;
    PORT
      LAYER M4 ;
        RECT  0 22.704 0.084 22.728 ;
    END
  END d[289]
  PIN d[28]
    DIRECTION INPUT ;
    USE SIGNAL ;
    PORT
      LAYER M4 ;
        RECT  0 41.424 0.084 41.448 ;
    END
  END d[28]
  PIN d[290]
    DIRECTION INPUT ;
    USE SIGNAL ;
    PORT
      LAYER M4 ;
        RECT  0 22.8 0.084 22.824 ;
    END
  END d[290]
  PIN d[291]
    DIRECTION INPUT ;
    USE SIGNAL ;
    PORT
      LAYER M4 ;
        RECT  0 22.896 0.084 22.92 ;
    END
  END d[291]
  PIN d[292]
    DIRECTION INPUT ;
    USE SIGNAL ;
    PORT
      LAYER M4 ;
        RECT  0 22.992 0.084 23.016 ;
    END
  END d[292]
  PIN d[293]
    DIRECTION INPUT ;
    USE SIGNAL ;
    PORT
      LAYER M4 ;
        RECT  0 23.088 0.084 23.112 ;
    END
  END d[293]
  PIN d[294]
    DIRECTION INPUT ;
    USE SIGNAL ;
    PORT
      LAYER M4 ;
        RECT  0 23.184 0.084 23.208 ;
    END
  END d[294]
  PIN d[295]
    DIRECTION INPUT ;
    USE SIGNAL ;
    PORT
      LAYER M4 ;
        RECT  0 23.28 0.084 23.304 ;
    END
  END d[295]
  PIN d[296]
    DIRECTION INPUT ;
    USE SIGNAL ;
    PORT
      LAYER M4 ;
        RECT  0 23.376 0.084 23.4 ;
    END
  END d[296]
  PIN d[297]
    DIRECTION INPUT ;
    USE SIGNAL ;
    PORT
      LAYER M4 ;
        RECT  0 23.472 0.084 23.496 ;
    END
  END d[297]
  PIN d[298]
    DIRECTION INPUT ;
    USE SIGNAL ;
    PORT
      LAYER M4 ;
        RECT  0 23.568 0.084 23.592 ;
    END
  END d[298]
  PIN d[299]
    DIRECTION INPUT ;
    USE SIGNAL ;
    PORT
      LAYER M4 ;
        RECT  0 23.664 0.084 23.688 ;
    END
  END d[299]
  PIN d[29]
    DIRECTION INPUT ;
    USE SIGNAL ;
    PORT
      LAYER M4 ;
        RECT  0 41.52 0.084 41.544 ;
    END
  END d[29]
  PIN d[2]
    DIRECTION INPUT ;
    USE SIGNAL ;
    PORT
      LAYER M4 ;
        RECT  0 38.928 0.084 38.952 ;
    END
  END d[2]
  PIN d[300]
    DIRECTION INPUT ;
    USE SIGNAL ;
    PORT
      LAYER M4 ;
        RECT  0 23.76 0.084 23.784 ;
    END
  END d[300]
  PIN d[301]
    DIRECTION INPUT ;
    USE SIGNAL ;
    PORT
      LAYER M4 ;
        RECT  0 23.856 0.084 23.88 ;
    END
  END d[301]
  PIN d[302]
    DIRECTION INPUT ;
    USE SIGNAL ;
    PORT
      LAYER M4 ;
        RECT  0 23.952 0.084 23.976 ;
    END
  END d[302]
  PIN d[303]
    DIRECTION INPUT ;
    USE SIGNAL ;
    PORT
      LAYER M4 ;
        RECT  0 24.048 0.084 24.072 ;
    END
  END d[303]
  PIN d[304]
    DIRECTION INPUT ;
    USE SIGNAL ;
    PORT
      LAYER M4 ;
        RECT  0 24.144 0.084 24.168 ;
    END
  END d[304]
  PIN d[305]
    DIRECTION INPUT ;
    USE SIGNAL ;
    PORT
      LAYER M4 ;
        RECT  0 24.24 0.084 24.264 ;
    END
  END d[305]
  PIN d[306]
    DIRECTION INPUT ;
    USE SIGNAL ;
    PORT
      LAYER M4 ;
        RECT  0 24.336 0.084 24.36 ;
    END
  END d[306]
  PIN d[307]
    DIRECTION INPUT ;
    USE SIGNAL ;
    PORT
      LAYER M4 ;
        RECT  0 24.432 0.084 24.456 ;
    END
  END d[307]
  PIN d[308]
    DIRECTION INPUT ;
    USE SIGNAL ;
    PORT
      LAYER M4 ;
        RECT  0 24.528 0.084 24.552 ;
    END
  END d[308]
  PIN d[309]
    DIRECTION INPUT ;
    USE SIGNAL ;
    PORT
      LAYER M4 ;
        RECT  0 24.624 0.084 24.648 ;
    END
  END d[309]
  PIN d[30]
    DIRECTION INPUT ;
    USE SIGNAL ;
    PORT
      LAYER M4 ;
        RECT  0 41.616 0.084 41.64 ;
    END
  END d[30]
  PIN d[310]
    DIRECTION INPUT ;
    USE SIGNAL ;
    PORT
      LAYER M4 ;
        RECT  0 24.72 0.084 24.744 ;
    END
  END d[310]
  PIN d[311]
    DIRECTION INPUT ;
    USE SIGNAL ;
    PORT
      LAYER M4 ;
        RECT  0 24.816 0.084 24.84 ;
    END
  END d[311]
  PIN d[312]
    DIRECTION INPUT ;
    USE SIGNAL ;
    PORT
      LAYER M4 ;
        RECT  0 24.912 0.084 24.936 ;
    END
  END d[312]
  PIN d[313]
    DIRECTION INPUT ;
    USE SIGNAL ;
    PORT
      LAYER M4 ;
        RECT  0 25.008 0.084 25.032 ;
    END
  END d[313]
  PIN d[314]
    DIRECTION INPUT ;
    USE SIGNAL ;
    PORT
      LAYER M4 ;
        RECT  0 25.104 0.084 25.128 ;
    END
  END d[314]
  PIN d[315]
    DIRECTION INPUT ;
    USE SIGNAL ;
    PORT
      LAYER M4 ;
        RECT  0 25.2 0.084 25.224 ;
    END
  END d[315]
  PIN d[316]
    DIRECTION INPUT ;
    USE SIGNAL ;
    PORT
      LAYER M4 ;
        RECT  0 25.296 0.084 25.32 ;
    END
  END d[316]
  PIN d[317]
    DIRECTION INPUT ;
    USE SIGNAL ;
    PORT
      LAYER M4 ;
        RECT  0 25.392 0.084 25.416 ;
    END
  END d[317]
  PIN d[318]
    DIRECTION INPUT ;
    USE SIGNAL ;
    PORT
      LAYER M4 ;
        RECT  0 25.488 0.084 25.512 ;
    END
  END d[318]
  PIN d[319]
    DIRECTION INPUT ;
    USE SIGNAL ;
    PORT
      LAYER M4 ;
        RECT  0 25.584 0.084 25.608 ;
    END
  END d[319]
  PIN d[31]
    DIRECTION INPUT ;
    USE SIGNAL ;
    PORT
      LAYER M4 ;
        RECT  0 41.712 0.084 41.736 ;
    END
  END d[31]
  PIN d[320]
    DIRECTION INPUT ;
    USE SIGNAL ;
    PORT
      LAYER M4 ;
        RECT  0 16.464 0.084 16.488 ;
    END
  END d[320]
  PIN d[321]
    DIRECTION INPUT ;
    USE SIGNAL ;
    PORT
      LAYER M4 ;
        RECT  0 16.56 0.084 16.584 ;
    END
  END d[321]
  PIN d[322]
    DIRECTION INPUT ;
    USE SIGNAL ;
    PORT
      LAYER M4 ;
        RECT  0 16.656 0.084 16.68 ;
    END
  END d[322]
  PIN d[323]
    DIRECTION INPUT ;
    USE SIGNAL ;
    PORT
      LAYER M4 ;
        RECT  0 16.752 0.084 16.776 ;
    END
  END d[323]
  PIN d[324]
    DIRECTION INPUT ;
    USE SIGNAL ;
    PORT
      LAYER M4 ;
        RECT  0 16.848 0.084 16.872 ;
    END
  END d[324]
  PIN d[325]
    DIRECTION INPUT ;
    USE SIGNAL ;
    PORT
      LAYER M4 ;
        RECT  0 16.944 0.084 16.968 ;
    END
  END d[325]
  PIN d[326]
    DIRECTION INPUT ;
    USE SIGNAL ;
    PORT
      LAYER M4 ;
        RECT  0 17.04 0.084 17.064 ;
    END
  END d[326]
  PIN d[327]
    DIRECTION INPUT ;
    USE SIGNAL ;
    PORT
      LAYER M4 ;
        RECT  0 17.136 0.084 17.16 ;
    END
  END d[327]
  PIN d[328]
    DIRECTION INPUT ;
    USE SIGNAL ;
    PORT
      LAYER M4 ;
        RECT  0 17.232 0.084 17.256 ;
    END
  END d[328]
  PIN d[329]
    DIRECTION INPUT ;
    USE SIGNAL ;
    PORT
      LAYER M4 ;
        RECT  0 17.328 0.084 17.352 ;
    END
  END d[329]
  PIN d[32]
    DIRECTION INPUT ;
    USE SIGNAL ;
    PORT
      LAYER M4 ;
        RECT  0 29.52 0.084 29.544 ;
    END
  END d[32]
  PIN d[330]
    DIRECTION INPUT ;
    USE SIGNAL ;
    PORT
      LAYER M4 ;
        RECT  0 17.424 0.084 17.448 ;
    END
  END d[330]
  PIN d[331]
    DIRECTION INPUT ;
    USE SIGNAL ;
    PORT
      LAYER M4 ;
        RECT  0 17.52 0.084 17.544 ;
    END
  END d[331]
  PIN d[332]
    DIRECTION INPUT ;
    USE SIGNAL ;
    PORT
      LAYER M4 ;
        RECT  0 17.616 0.084 17.64 ;
    END
  END d[332]
  PIN d[333]
    DIRECTION INPUT ;
    USE SIGNAL ;
    PORT
      LAYER M4 ;
        RECT  0 17.712 0.084 17.736 ;
    END
  END d[333]
  PIN d[334]
    DIRECTION INPUT ;
    USE SIGNAL ;
    PORT
      LAYER M4 ;
        RECT  0 17.808 0.084 17.832 ;
    END
  END d[334]
  PIN d[335]
    DIRECTION INPUT ;
    USE SIGNAL ;
    PORT
      LAYER M4 ;
        RECT  0 17.904 0.084 17.928 ;
    END
  END d[335]
  PIN d[336]
    DIRECTION INPUT ;
    USE SIGNAL ;
    PORT
      LAYER M4 ;
        RECT  0 18 0.084 18.024 ;
    END
  END d[336]
  PIN d[337]
    DIRECTION INPUT ;
    USE SIGNAL ;
    PORT
      LAYER M4 ;
        RECT  0 18.096 0.084 18.12 ;
    END
  END d[337]
  PIN d[338]
    DIRECTION INPUT ;
    USE SIGNAL ;
    PORT
      LAYER M4 ;
        RECT  0 18.192 0.084 18.216 ;
    END
  END d[338]
  PIN d[339]
    DIRECTION INPUT ;
    USE SIGNAL ;
    PORT
      LAYER M4 ;
        RECT  0 18.288 0.084 18.312 ;
    END
  END d[339]
  PIN d[33]
    DIRECTION INPUT ;
    USE SIGNAL ;
    PORT
      LAYER M4 ;
        RECT  0 29.616 0.084 29.64 ;
    END
  END d[33]
  PIN d[340]
    DIRECTION INPUT ;
    USE SIGNAL ;
    PORT
      LAYER M4 ;
        RECT  0 18.384 0.084 18.408 ;
    END
  END d[340]
  PIN d[341]
    DIRECTION INPUT ;
    USE SIGNAL ;
    PORT
      LAYER M4 ;
        RECT  0 18.48 0.084 18.504 ;
    END
  END d[341]
  PIN d[342]
    DIRECTION INPUT ;
    USE SIGNAL ;
    PORT
      LAYER M4 ;
        RECT  0 18.576 0.084 18.6 ;
    END
  END d[342]
  PIN d[343]
    DIRECTION INPUT ;
    USE SIGNAL ;
    PORT
      LAYER M4 ;
        RECT  0 18.672 0.084 18.696 ;
    END
  END d[343]
  PIN d[344]
    DIRECTION INPUT ;
    USE SIGNAL ;
    PORT
      LAYER M4 ;
        RECT  0 18.768 0.084 18.792 ;
    END
  END d[344]
  PIN d[345]
    DIRECTION INPUT ;
    USE SIGNAL ;
    PORT
      LAYER M4 ;
        RECT  0 18.864 0.084 18.888 ;
    END
  END d[345]
  PIN d[346]
    DIRECTION INPUT ;
    USE SIGNAL ;
    PORT
      LAYER M4 ;
        RECT  0 18.96 0.084 18.984 ;
    END
  END d[346]
  PIN d[347]
    DIRECTION INPUT ;
    USE SIGNAL ;
    PORT
      LAYER M4 ;
        RECT  0 19.056 0.084 19.08 ;
    END
  END d[347]
  PIN d[348]
    DIRECTION INPUT ;
    USE SIGNAL ;
    PORT
      LAYER M4 ;
        RECT  0 19.152 0.084 19.176 ;
    END
  END d[348]
  PIN d[349]
    DIRECTION INPUT ;
    USE SIGNAL ;
    PORT
      LAYER M4 ;
        RECT  0 19.248 0.084 19.272 ;
    END
  END d[349]
  PIN d[34]
    DIRECTION INPUT ;
    USE SIGNAL ;
    PORT
      LAYER M4 ;
        RECT  0 29.712 0.084 29.736 ;
    END
  END d[34]
  PIN d[350]
    DIRECTION INPUT ;
    USE SIGNAL ;
    PORT
      LAYER M4 ;
        RECT  0 19.344 0.084 19.368 ;
    END
  END d[350]
  PIN d[351]
    DIRECTION INPUT ;
    USE SIGNAL ;
    PORT
      LAYER M4 ;
        RECT  0 19.44 0.084 19.464 ;
    END
  END d[351]
  PIN d[352]
    DIRECTION INPUT ;
    USE SIGNAL ;
    PORT
      LAYER M4 ;
        RECT  0 10.32 0.084 10.344 ;
    END
  END d[352]
  PIN d[353]
    DIRECTION INPUT ;
    USE SIGNAL ;
    PORT
      LAYER M4 ;
        RECT  0 10.416 0.084 10.44 ;
    END
  END d[353]
  PIN d[354]
    DIRECTION INPUT ;
    USE SIGNAL ;
    PORT
      LAYER M4 ;
        RECT  0 10.512 0.084 10.536 ;
    END
  END d[354]
  PIN d[355]
    DIRECTION INPUT ;
    USE SIGNAL ;
    PORT
      LAYER M4 ;
        RECT  0 10.608 0.084 10.632 ;
    END
  END d[355]
  PIN d[356]
    DIRECTION INPUT ;
    USE SIGNAL ;
    PORT
      LAYER M4 ;
        RECT  0 10.704 0.084 10.728 ;
    END
  END d[356]
  PIN d[357]
    DIRECTION INPUT ;
    USE SIGNAL ;
    PORT
      LAYER M4 ;
        RECT  0 10.8 0.084 10.824 ;
    END
  END d[357]
  PIN d[358]
    DIRECTION INPUT ;
    USE SIGNAL ;
    PORT
      LAYER M4 ;
        RECT  0 10.896 0.084 10.92 ;
    END
  END d[358]
  PIN d[359]
    DIRECTION INPUT ;
    USE SIGNAL ;
    PORT
      LAYER M4 ;
        RECT  0 10.992 0.084 11.016 ;
    END
  END d[359]
  PIN d[35]
    DIRECTION INPUT ;
    USE SIGNAL ;
    PORT
      LAYER M4 ;
        RECT  0 29.808 0.084 29.832 ;
    END
  END d[35]
  PIN d[360]
    DIRECTION INPUT ;
    USE SIGNAL ;
    PORT
      LAYER M4 ;
        RECT  0 11.088 0.084 11.112 ;
    END
  END d[360]
  PIN d[361]
    DIRECTION INPUT ;
    USE SIGNAL ;
    PORT
      LAYER M4 ;
        RECT  0 11.184 0.084 11.208 ;
    END
  END d[361]
  PIN d[362]
    DIRECTION INPUT ;
    USE SIGNAL ;
    PORT
      LAYER M4 ;
        RECT  0 11.28 0.084 11.304 ;
    END
  END d[362]
  PIN d[363]
    DIRECTION INPUT ;
    USE SIGNAL ;
    PORT
      LAYER M4 ;
        RECT  0 11.376 0.084 11.4 ;
    END
  END d[363]
  PIN d[364]
    DIRECTION INPUT ;
    USE SIGNAL ;
    PORT
      LAYER M4 ;
        RECT  0 11.472 0.084 11.496 ;
    END
  END d[364]
  PIN d[365]
    DIRECTION INPUT ;
    USE SIGNAL ;
    PORT
      LAYER M4 ;
        RECT  0 11.568 0.084 11.592 ;
    END
  END d[365]
  PIN d[366]
    DIRECTION INPUT ;
    USE SIGNAL ;
    PORT
      LAYER M4 ;
        RECT  0 11.664 0.084 11.688 ;
    END
  END d[366]
  PIN d[367]
    DIRECTION INPUT ;
    USE SIGNAL ;
    PORT
      LAYER M4 ;
        RECT  0 11.76 0.084 11.784 ;
    END
  END d[367]
  PIN d[368]
    DIRECTION INPUT ;
    USE SIGNAL ;
    PORT
      LAYER M4 ;
        RECT  0 11.856 0.084 11.88 ;
    END
  END d[368]
  PIN d[369]
    DIRECTION INPUT ;
    USE SIGNAL ;
    PORT
      LAYER M4 ;
        RECT  0 11.952 0.084 11.976 ;
    END
  END d[369]
  PIN d[36]
    DIRECTION INPUT ;
    USE SIGNAL ;
    PORT
      LAYER M4 ;
        RECT  0 29.904 0.084 29.928 ;
    END
  END d[36]
  PIN d[370]
    DIRECTION INPUT ;
    USE SIGNAL ;
    PORT
      LAYER M4 ;
        RECT  0 12.048 0.084 12.072 ;
    END
  END d[370]
  PIN d[371]
    DIRECTION INPUT ;
    USE SIGNAL ;
    PORT
      LAYER M4 ;
        RECT  0 12.144 0.084 12.168 ;
    END
  END d[371]
  PIN d[372]
    DIRECTION INPUT ;
    USE SIGNAL ;
    PORT
      LAYER M4 ;
        RECT  0 12.24 0.084 12.264 ;
    END
  END d[372]
  PIN d[373]
    DIRECTION INPUT ;
    USE SIGNAL ;
    PORT
      LAYER M4 ;
        RECT  0 12.336 0.084 12.36 ;
    END
  END d[373]
  PIN d[374]
    DIRECTION INPUT ;
    USE SIGNAL ;
    PORT
      LAYER M4 ;
        RECT  0 12.432 0.084 12.456 ;
    END
  END d[374]
  PIN d[375]
    DIRECTION INPUT ;
    USE SIGNAL ;
    PORT
      LAYER M4 ;
        RECT  0 12.528 0.084 12.552 ;
    END
  END d[375]
  PIN d[376]
    DIRECTION INPUT ;
    USE SIGNAL ;
    PORT
      LAYER M4 ;
        RECT  0 12.624 0.084 12.648 ;
    END
  END d[376]
  PIN d[377]
    DIRECTION INPUT ;
    USE SIGNAL ;
    PORT
      LAYER M4 ;
        RECT  0 12.72 0.084 12.744 ;
    END
  END d[377]
  PIN d[378]
    DIRECTION INPUT ;
    USE SIGNAL ;
    PORT
      LAYER M4 ;
        RECT  0 12.816 0.084 12.84 ;
    END
  END d[378]
  PIN d[379]
    DIRECTION INPUT ;
    USE SIGNAL ;
    PORT
      LAYER M4 ;
        RECT  0 12.912 0.084 12.936 ;
    END
  END d[379]
  PIN d[37]
    DIRECTION INPUT ;
    USE SIGNAL ;
    PORT
      LAYER M4 ;
        RECT  0 30 0.084 30.024 ;
    END
  END d[37]
  PIN d[380]
    DIRECTION INPUT ;
    USE SIGNAL ;
    PORT
      LAYER M4 ;
        RECT  0 13.008 0.084 13.032 ;
    END
  END d[380]
  PIN d[381]
    DIRECTION INPUT ;
    USE SIGNAL ;
    PORT
      LAYER M4 ;
        RECT  0 13.104 0.084 13.128 ;
    END
  END d[381]
  PIN d[382]
    DIRECTION INPUT ;
    USE SIGNAL ;
    PORT
      LAYER M4 ;
        RECT  0 13.2 0.084 13.224 ;
    END
  END d[382]
  PIN d[383]
    DIRECTION INPUT ;
    USE SIGNAL ;
    PORT
      LAYER M4 ;
        RECT  0 13.296 0.084 13.32 ;
    END
  END d[383]
  PIN d[384]
    DIRECTION INPUT ;
    USE SIGNAL ;
    PORT
      LAYER M4 ;
        RECT  0 45.648 0.084 45.672 ;
    END
  END d[384]
  PIN d[385]
    DIRECTION INPUT ;
    USE SIGNAL ;
    PORT
      LAYER M4 ;
        RECT  0 45.744 0.084 45.768 ;
    END
  END d[385]
  PIN d[386]
    DIRECTION INPUT ;
    USE SIGNAL ;
    PORT
      LAYER M4 ;
        RECT  0 45.84 0.084 45.864 ;
    END
  END d[386]
  PIN d[387]
    DIRECTION INPUT ;
    USE SIGNAL ;
    PORT
      LAYER M4 ;
        RECT  0 45.936 0.084 45.96 ;
    END
  END d[387]
  PIN d[388]
    DIRECTION INPUT ;
    USE SIGNAL ;
    PORT
      LAYER M4 ;
        RECT  0 46.032 0.084 46.056 ;
    END
  END d[388]
  PIN d[389]
    DIRECTION INPUT ;
    USE SIGNAL ;
    PORT
      LAYER M4 ;
        RECT  0 46.128 0.084 46.152 ;
    END
  END d[389]
  PIN d[38]
    DIRECTION INPUT ;
    USE SIGNAL ;
    PORT
      LAYER M4 ;
        RECT  0 30.096 0.084 30.12 ;
    END
  END d[38]
  PIN d[390]
    DIRECTION INPUT ;
    USE SIGNAL ;
    PORT
      LAYER M4 ;
        RECT  0 46.224 0.084 46.248 ;
    END
  END d[390]
  PIN d[391]
    DIRECTION INPUT ;
    USE SIGNAL ;
    PORT
      LAYER M4 ;
        RECT  0 46.32 0.084 46.344 ;
    END
  END d[391]
  PIN d[392]
    DIRECTION INPUT ;
    USE SIGNAL ;
    PORT
      LAYER M4 ;
        RECT  0 46.416 0.084 46.44 ;
    END
  END d[392]
  PIN d[393]
    DIRECTION INPUT ;
    USE SIGNAL ;
    PORT
      LAYER M4 ;
        RECT  0 46.512 0.084 46.536 ;
    END
  END d[393]
  PIN d[394]
    DIRECTION INPUT ;
    USE SIGNAL ;
    PORT
      LAYER M4 ;
        RECT  0 46.608 0.084 46.632 ;
    END
  END d[394]
  PIN d[395]
    DIRECTION INPUT ;
    USE SIGNAL ;
    PORT
      LAYER M4 ;
        RECT  0 46.704 0.084 46.728 ;
    END
  END d[395]
  PIN d[396]
    DIRECTION INPUT ;
    USE SIGNAL ;
    PORT
      LAYER M4 ;
        RECT  0 46.8 0.084 46.824 ;
    END
  END d[396]
  PIN d[397]
    DIRECTION INPUT ;
    USE SIGNAL ;
    PORT
      LAYER M4 ;
        RECT  0 46.896 0.084 46.92 ;
    END
  END d[397]
  PIN d[398]
    DIRECTION INPUT ;
    USE SIGNAL ;
    PORT
      LAYER M4 ;
        RECT  0 46.992 0.084 47.016 ;
    END
  END d[398]
  PIN d[399]
    DIRECTION INPUT ;
    USE SIGNAL ;
    PORT
      LAYER M4 ;
        RECT  0 47.088 0.084 47.112 ;
    END
  END d[399]
  PIN d[39]
    DIRECTION INPUT ;
    USE SIGNAL ;
    PORT
      LAYER M4 ;
        RECT  0 30.192 0.084 30.216 ;
    END
  END d[39]
  PIN d[3]
    DIRECTION INPUT ;
    USE SIGNAL ;
    PORT
      LAYER M4 ;
        RECT  0 39.024 0.084 39.048 ;
    END
  END d[3]
  PIN d[400]
    DIRECTION INPUT ;
    USE SIGNAL ;
    PORT
      LAYER M4 ;
        RECT  0 47.184 0.084 47.208 ;
    END
  END d[400]
  PIN d[401]
    DIRECTION INPUT ;
    USE SIGNAL ;
    PORT
      LAYER M4 ;
        RECT  0 47.28 0.084 47.304 ;
    END
  END d[401]
  PIN d[402]
    DIRECTION INPUT ;
    USE SIGNAL ;
    PORT
      LAYER M4 ;
        RECT  0 47.376 0.084 47.4 ;
    END
  END d[402]
  PIN d[403]
    DIRECTION INPUT ;
    USE SIGNAL ;
    PORT
      LAYER M4 ;
        RECT  0 47.472 0.084 47.496 ;
    END
  END d[403]
  PIN d[404]
    DIRECTION INPUT ;
    USE SIGNAL ;
    PORT
      LAYER M4 ;
        RECT  0 47.568 0.084 47.592 ;
    END
  END d[404]
  PIN d[405]
    DIRECTION INPUT ;
    USE SIGNAL ;
    PORT
      LAYER M4 ;
        RECT  0 47.664 0.084 47.688 ;
    END
  END d[405]
  PIN d[406]
    DIRECTION INPUT ;
    USE SIGNAL ;
    PORT
      LAYER M4 ;
        RECT  0 47.76 0.084 47.784 ;
    END
  END d[406]
  PIN d[407]
    DIRECTION INPUT ;
    USE SIGNAL ;
    PORT
      LAYER M4 ;
        RECT  0 47.856 0.084 47.88 ;
    END
  END d[407]
  PIN d[408]
    DIRECTION INPUT ;
    USE SIGNAL ;
    PORT
      LAYER M4 ;
        RECT  0 47.952 0.084 47.976 ;
    END
  END d[408]
  PIN d[409]
    DIRECTION INPUT ;
    USE SIGNAL ;
    PORT
      LAYER M4 ;
        RECT  0 48.048 0.084 48.072 ;
    END
  END d[409]
  PIN d[40]
    DIRECTION INPUT ;
    USE SIGNAL ;
    PORT
      LAYER M4 ;
        RECT  0 30.288 0.084 30.312 ;
    END
  END d[40]
  PIN d[410]
    DIRECTION INPUT ;
    USE SIGNAL ;
    PORT
      LAYER M4 ;
        RECT  0 48.144 0.084 48.168 ;
    END
  END d[410]
  PIN d[411]
    DIRECTION INPUT ;
    USE SIGNAL ;
    PORT
      LAYER M4 ;
        RECT  0 48.24 0.084 48.264 ;
    END
  END d[411]
  PIN d[412]
    DIRECTION INPUT ;
    USE SIGNAL ;
    PORT
      LAYER M4 ;
        RECT  0 48.336 0.084 48.36 ;
    END
  END d[412]
  PIN d[413]
    DIRECTION INPUT ;
    USE SIGNAL ;
    PORT
      LAYER M4 ;
        RECT  0 48.432 0.084 48.456 ;
    END
  END d[413]
  PIN d[414]
    DIRECTION INPUT ;
    USE SIGNAL ;
    PORT
      LAYER M4 ;
        RECT  0 48.528 0.084 48.552 ;
    END
  END d[414]
  PIN d[415]
    DIRECTION INPUT ;
    USE SIGNAL ;
    PORT
      LAYER M4 ;
        RECT  0 48.624 0.084 48.648 ;
    END
  END d[415]
  PIN d[416]
    DIRECTION INPUT ;
    USE SIGNAL ;
    PORT
      LAYER M4 ;
        RECT  0 54.864 0.084 54.888 ;
    END
  END d[416]
  PIN d[417]
    DIRECTION INPUT ;
    USE SIGNAL ;
    PORT
      LAYER M4 ;
        RECT  0 54.96 0.084 54.984 ;
    END
  END d[417]
  PIN d[418]
    DIRECTION INPUT ;
    USE SIGNAL ;
    PORT
      LAYER M4 ;
        RECT  0 55.056 0.084 55.08 ;
    END
  END d[418]
  PIN d[419]
    DIRECTION INPUT ;
    USE SIGNAL ;
    PORT
      LAYER M4 ;
        RECT  0 55.152 0.084 55.176 ;
    END
  END d[419]
  PIN d[41]
    DIRECTION INPUT ;
    USE SIGNAL ;
    PORT
      LAYER M4 ;
        RECT  0 30.384 0.084 30.408 ;
    END
  END d[41]
  PIN d[420]
    DIRECTION INPUT ;
    USE SIGNAL ;
    PORT
      LAYER M4 ;
        RECT  0 55.248 0.084 55.272 ;
    END
  END d[420]
  PIN d[421]
    DIRECTION INPUT ;
    USE SIGNAL ;
    PORT
      LAYER M4 ;
        RECT  0 55.344 0.084 55.368 ;
    END
  END d[421]
  PIN d[422]
    DIRECTION INPUT ;
    USE SIGNAL ;
    PORT
      LAYER M4 ;
        RECT  0 55.44 0.084 55.464 ;
    END
  END d[422]
  PIN d[423]
    DIRECTION INPUT ;
    USE SIGNAL ;
    PORT
      LAYER M4 ;
        RECT  0 55.536 0.084 55.56 ;
    END
  END d[423]
  PIN d[424]
    DIRECTION INPUT ;
    USE SIGNAL ;
    PORT
      LAYER M4 ;
        RECT  0 55.632 0.084 55.656 ;
    END
  END d[424]
  PIN d[425]
    DIRECTION INPUT ;
    USE SIGNAL ;
    PORT
      LAYER M4 ;
        RECT  0 55.728 0.084 55.752 ;
    END
  END d[425]
  PIN d[426]
    DIRECTION INPUT ;
    USE SIGNAL ;
    PORT
      LAYER M4 ;
        RECT  0 55.824 0.084 55.848 ;
    END
  END d[426]
  PIN d[427]
    DIRECTION INPUT ;
    USE SIGNAL ;
    PORT
      LAYER M4 ;
        RECT  0 55.92 0.084 55.944 ;
    END
  END d[427]
  PIN d[428]
    DIRECTION INPUT ;
    USE SIGNAL ;
    PORT
      LAYER M4 ;
        RECT  0 56.016 0.084 56.04 ;
    END
  END d[428]
  PIN d[429]
    DIRECTION INPUT ;
    USE SIGNAL ;
    PORT
      LAYER M4 ;
        RECT  0 56.112 0.084 56.136 ;
    END
  END d[429]
  PIN d[42]
    DIRECTION INPUT ;
    USE SIGNAL ;
    PORT
      LAYER M4 ;
        RECT  0 30.48 0.084 30.504 ;
    END
  END d[42]
  PIN d[430]
    DIRECTION INPUT ;
    USE SIGNAL ;
    PORT
      LAYER M4 ;
        RECT  0 56.208 0.084 56.232 ;
    END
  END d[430]
  PIN d[431]
    DIRECTION INPUT ;
    USE SIGNAL ;
    PORT
      LAYER M4 ;
        RECT  0 56.304 0.084 56.328 ;
    END
  END d[431]
  PIN d[432]
    DIRECTION INPUT ;
    USE SIGNAL ;
    PORT
      LAYER M4 ;
        RECT  0 56.4 0.084 56.424 ;
    END
  END d[432]
  PIN d[433]
    DIRECTION INPUT ;
    USE SIGNAL ;
    PORT
      LAYER M4 ;
        RECT  0 56.496 0.084 56.52 ;
    END
  END d[433]
  PIN d[434]
    DIRECTION INPUT ;
    USE SIGNAL ;
    PORT
      LAYER M4 ;
        RECT  0 56.592 0.084 56.616 ;
    END
  END d[434]
  PIN d[435]
    DIRECTION INPUT ;
    USE SIGNAL ;
    PORT
      LAYER M4 ;
        RECT  0 56.688 0.084 56.712 ;
    END
  END d[435]
  PIN d[436]
    DIRECTION INPUT ;
    USE SIGNAL ;
    PORT
      LAYER M4 ;
        RECT  0 56.784 0.084 56.808 ;
    END
  END d[436]
  PIN d[437]
    DIRECTION INPUT ;
    USE SIGNAL ;
    PORT
      LAYER M4 ;
        RECT  0 56.88 0.084 56.904 ;
    END
  END d[437]
  PIN d[438]
    DIRECTION INPUT ;
    USE SIGNAL ;
    PORT
      LAYER M4 ;
        RECT  0 56.976 0.084 57 ;
    END
  END d[438]
  PIN d[439]
    DIRECTION INPUT ;
    USE SIGNAL ;
    PORT
      LAYER M4 ;
        RECT  0 57.072 0.084 57.096 ;
    END
  END d[439]
  PIN d[43]
    DIRECTION INPUT ;
    USE SIGNAL ;
    PORT
      LAYER M4 ;
        RECT  0 30.576 0.084 30.6 ;
    END
  END d[43]
  PIN d[440]
    DIRECTION INPUT ;
    USE SIGNAL ;
    PORT
      LAYER M4 ;
        RECT  0 57.168 0.084 57.192 ;
    END
  END d[440]
  PIN d[441]
    DIRECTION INPUT ;
    USE SIGNAL ;
    PORT
      LAYER M4 ;
        RECT  0 57.264 0.084 57.288 ;
    END
  END d[441]
  PIN d[442]
    DIRECTION INPUT ;
    USE SIGNAL ;
    PORT
      LAYER M4 ;
        RECT  0 57.36 0.084 57.384 ;
    END
  END d[442]
  PIN d[443]
    DIRECTION INPUT ;
    USE SIGNAL ;
    PORT
      LAYER M4 ;
        RECT  0 57.456 0.084 57.48 ;
    END
  END d[443]
  PIN d[444]
    DIRECTION INPUT ;
    USE SIGNAL ;
    PORT
      LAYER M4 ;
        RECT  0 57.552 0.084 57.576 ;
    END
  END d[444]
  PIN d[445]
    DIRECTION INPUT ;
    USE SIGNAL ;
    PORT
      LAYER M4 ;
        RECT  0 57.648 0.084 57.672 ;
    END
  END d[445]
  PIN d[446]
    DIRECTION INPUT ;
    USE SIGNAL ;
    PORT
      LAYER M4 ;
        RECT  0 57.744 0.084 57.768 ;
    END
  END d[446]
  PIN d[447]
    DIRECTION INPUT ;
    USE SIGNAL ;
    PORT
      LAYER M4 ;
        RECT  0 57.84 0.084 57.864 ;
    END
  END d[447]
  PIN d[448]
    DIRECTION INPUT ;
    USE SIGNAL ;
    PORT
      LAYER M4 ;
        RECT  0 48.72 0.084 48.744 ;
    END
  END d[448]
  PIN d[449]
    DIRECTION INPUT ;
    USE SIGNAL ;
    PORT
      LAYER M4 ;
        RECT  0 48.816 0.084 48.84 ;
    END
  END d[449]
  PIN d[44]
    DIRECTION INPUT ;
    USE SIGNAL ;
    PORT
      LAYER M4 ;
        RECT  0 30.672 0.084 30.696 ;
    END
  END d[44]
  PIN d[450]
    DIRECTION INPUT ;
    USE SIGNAL ;
    PORT
      LAYER M4 ;
        RECT  0 48.912 0.084 48.936 ;
    END
  END d[450]
  PIN d[451]
    DIRECTION INPUT ;
    USE SIGNAL ;
    PORT
      LAYER M4 ;
        RECT  0 49.008 0.084 49.032 ;
    END
  END d[451]
  PIN d[452]
    DIRECTION INPUT ;
    USE SIGNAL ;
    PORT
      LAYER M4 ;
        RECT  0 49.104 0.084 49.128 ;
    END
  END d[452]
  PIN d[453]
    DIRECTION INPUT ;
    USE SIGNAL ;
    PORT
      LAYER M4 ;
        RECT  0 49.2 0.084 49.224 ;
    END
  END d[453]
  PIN d[454]
    DIRECTION INPUT ;
    USE SIGNAL ;
    PORT
      LAYER M4 ;
        RECT  0 49.296 0.084 49.32 ;
    END
  END d[454]
  PIN d[455]
    DIRECTION INPUT ;
    USE SIGNAL ;
    PORT
      LAYER M4 ;
        RECT  0 49.392 0.084 49.416 ;
    END
  END d[455]
  PIN d[456]
    DIRECTION INPUT ;
    USE SIGNAL ;
    PORT
      LAYER M4 ;
        RECT  0 49.488 0.084 49.512 ;
    END
  END d[456]
  PIN d[457]
    DIRECTION INPUT ;
    USE SIGNAL ;
    PORT
      LAYER M4 ;
        RECT  0 49.584 0.084 49.608 ;
    END
  END d[457]
  PIN d[458]
    DIRECTION INPUT ;
    USE SIGNAL ;
    PORT
      LAYER M4 ;
        RECT  0 49.68 0.084 49.704 ;
    END
  END d[458]
  PIN d[459]
    DIRECTION INPUT ;
    USE SIGNAL ;
    PORT
      LAYER M4 ;
        RECT  0 49.776 0.084 49.8 ;
    END
  END d[459]
  PIN d[45]
    DIRECTION INPUT ;
    USE SIGNAL ;
    PORT
      LAYER M4 ;
        RECT  0 30.768 0.084 30.792 ;
    END
  END d[45]
  PIN d[460]
    DIRECTION INPUT ;
    USE SIGNAL ;
    PORT
      LAYER M4 ;
        RECT  0 49.872 0.084 49.896 ;
    END
  END d[460]
  PIN d[461]
    DIRECTION INPUT ;
    USE SIGNAL ;
    PORT
      LAYER M4 ;
        RECT  0 49.968 0.084 49.992 ;
    END
  END d[461]
  PIN d[462]
    DIRECTION INPUT ;
    USE SIGNAL ;
    PORT
      LAYER M4 ;
        RECT  0 50.064 0.084 50.088 ;
    END
  END d[462]
  PIN d[463]
    DIRECTION INPUT ;
    USE SIGNAL ;
    PORT
      LAYER M4 ;
        RECT  0 50.16 0.084 50.184 ;
    END
  END d[463]
  PIN d[464]
    DIRECTION INPUT ;
    USE SIGNAL ;
    PORT
      LAYER M4 ;
        RECT  0 50.256 0.084 50.28 ;
    END
  END d[464]
  PIN d[465]
    DIRECTION INPUT ;
    USE SIGNAL ;
    PORT
      LAYER M4 ;
        RECT  0 50.352 0.084 50.376 ;
    END
  END d[465]
  PIN d[466]
    DIRECTION INPUT ;
    USE SIGNAL ;
    PORT
      LAYER M4 ;
        RECT  0 50.448 0.084 50.472 ;
    END
  END d[466]
  PIN d[467]
    DIRECTION INPUT ;
    USE SIGNAL ;
    PORT
      LAYER M4 ;
        RECT  0 50.544 0.084 50.568 ;
    END
  END d[467]
  PIN d[468]
    DIRECTION INPUT ;
    USE SIGNAL ;
    PORT
      LAYER M4 ;
        RECT  0 50.64 0.084 50.664 ;
    END
  END d[468]
  PIN d[469]
    DIRECTION INPUT ;
    USE SIGNAL ;
    PORT
      LAYER M4 ;
        RECT  0 50.736 0.084 50.76 ;
    END
  END d[469]
  PIN d[46]
    DIRECTION INPUT ;
    USE SIGNAL ;
    PORT
      LAYER M4 ;
        RECT  0 30.864 0.084 30.888 ;
    END
  END d[46]
  PIN d[470]
    DIRECTION INPUT ;
    USE SIGNAL ;
    PORT
      LAYER M4 ;
        RECT  0 50.832 0.084 50.856 ;
    END
  END d[470]
  PIN d[471]
    DIRECTION INPUT ;
    USE SIGNAL ;
    PORT
      LAYER M4 ;
        RECT  0 50.928 0.084 50.952 ;
    END
  END d[471]
  PIN d[472]
    DIRECTION INPUT ;
    USE SIGNAL ;
    PORT
      LAYER M4 ;
        RECT  0 51.024 0.084 51.048 ;
    END
  END d[472]
  PIN d[473]
    DIRECTION INPUT ;
    USE SIGNAL ;
    PORT
      LAYER M4 ;
        RECT  0 51.12 0.084 51.144 ;
    END
  END d[473]
  PIN d[474]
    DIRECTION INPUT ;
    USE SIGNAL ;
    PORT
      LAYER M4 ;
        RECT  0 51.216 0.084 51.24 ;
    END
  END d[474]
  PIN d[475]
    DIRECTION INPUT ;
    USE SIGNAL ;
    PORT
      LAYER M4 ;
        RECT  0 51.312 0.084 51.336 ;
    END
  END d[475]
  PIN d[476]
    DIRECTION INPUT ;
    USE SIGNAL ;
    PORT
      LAYER M4 ;
        RECT  0 51.408 0.084 51.432 ;
    END
  END d[476]
  PIN d[477]
    DIRECTION INPUT ;
    USE SIGNAL ;
    PORT
      LAYER M4 ;
        RECT  0 51.504 0.084 51.528 ;
    END
  END d[477]
  PIN d[478]
    DIRECTION INPUT ;
    USE SIGNAL ;
    PORT
      LAYER M4 ;
        RECT  0 51.6 0.084 51.624 ;
    END
  END d[478]
  PIN d[479]
    DIRECTION INPUT ;
    USE SIGNAL ;
    PORT
      LAYER M4 ;
        RECT  0 51.696 0.084 51.72 ;
    END
  END d[479]
  PIN d[47]
    DIRECTION INPUT ;
    USE SIGNAL ;
    PORT
      LAYER M4 ;
        RECT  0 30.96 0.084 30.984 ;
    END
  END d[47]
  PIN d[480]
    DIRECTION INPUT ;
    USE SIGNAL ;
    PORT
      LAYER M4 ;
        RECT  0 51.792 0.084 51.816 ;
    END
  END d[480]
  PIN d[481]
    DIRECTION INPUT ;
    USE SIGNAL ;
    PORT
      LAYER M4 ;
        RECT  0 51.888 0.084 51.912 ;
    END
  END d[481]
  PIN d[482]
    DIRECTION INPUT ;
    USE SIGNAL ;
    PORT
      LAYER M4 ;
        RECT  0 51.984 0.084 52.008 ;
    END
  END d[482]
  PIN d[483]
    DIRECTION INPUT ;
    USE SIGNAL ;
    PORT
      LAYER M4 ;
        RECT  0 52.08 0.084 52.104 ;
    END
  END d[483]
  PIN d[484]
    DIRECTION INPUT ;
    USE SIGNAL ;
    PORT
      LAYER M4 ;
        RECT  0 52.176 0.084 52.2 ;
    END
  END d[484]
  PIN d[485]
    DIRECTION INPUT ;
    USE SIGNAL ;
    PORT
      LAYER M4 ;
        RECT  0 52.272 0.084 52.296 ;
    END
  END d[485]
  PIN d[486]
    DIRECTION INPUT ;
    USE SIGNAL ;
    PORT
      LAYER M4 ;
        RECT  0 52.368 0.084 52.392 ;
    END
  END d[486]
  PIN d[487]
    DIRECTION INPUT ;
    USE SIGNAL ;
    PORT
      LAYER M4 ;
        RECT  0 52.464 0.084 52.488 ;
    END
  END d[487]
  PIN d[488]
    DIRECTION INPUT ;
    USE SIGNAL ;
    PORT
      LAYER M4 ;
        RECT  0 52.56 0.084 52.584 ;
    END
  END d[488]
  PIN d[489]
    DIRECTION INPUT ;
    USE SIGNAL ;
    PORT
      LAYER M4 ;
        RECT  0 52.656 0.084 52.68 ;
    END
  END d[489]
  PIN d[48]
    DIRECTION INPUT ;
    USE SIGNAL ;
    PORT
      LAYER M4 ;
        RECT  0 31.056 0.084 31.08 ;
    END
  END d[48]
  PIN d[490]
    DIRECTION INPUT ;
    USE SIGNAL ;
    PORT
      LAYER M4 ;
        RECT  0 52.752 0.084 52.776 ;
    END
  END d[490]
  PIN d[491]
    DIRECTION INPUT ;
    USE SIGNAL ;
    PORT
      LAYER M4 ;
        RECT  0 52.848 0.084 52.872 ;
    END
  END d[491]
  PIN d[492]
    DIRECTION INPUT ;
    USE SIGNAL ;
    PORT
      LAYER M4 ;
        RECT  0 52.944 0.084 52.968 ;
    END
  END d[492]
  PIN d[493]
    DIRECTION INPUT ;
    USE SIGNAL ;
    PORT
      LAYER M4 ;
        RECT  0 53.04 0.084 53.064 ;
    END
  END d[493]
  PIN d[494]
    DIRECTION INPUT ;
    USE SIGNAL ;
    PORT
      LAYER M4 ;
        RECT  0 53.136 0.084 53.16 ;
    END
  END d[494]
  PIN d[495]
    DIRECTION INPUT ;
    USE SIGNAL ;
    PORT
      LAYER M4 ;
        RECT  0 53.232 0.084 53.256 ;
    END
  END d[495]
  PIN d[496]
    DIRECTION INPUT ;
    USE SIGNAL ;
    PORT
      LAYER M4 ;
        RECT  0 53.328 0.084 53.352 ;
    END
  END d[496]
  PIN d[497]
    DIRECTION INPUT ;
    USE SIGNAL ;
    PORT
      LAYER M4 ;
        RECT  0 53.424 0.084 53.448 ;
    END
  END d[497]
  PIN d[498]
    DIRECTION INPUT ;
    USE SIGNAL ;
    PORT
      LAYER M4 ;
        RECT  0 53.52 0.084 53.544 ;
    END
  END d[498]
  PIN d[499]
    DIRECTION INPUT ;
    USE SIGNAL ;
    PORT
      LAYER M4 ;
        RECT  0 53.616 0.084 53.64 ;
    END
  END d[499]
  PIN d[49]
    DIRECTION INPUT ;
    USE SIGNAL ;
    PORT
      LAYER M4 ;
        RECT  0 31.152 0.084 31.176 ;
    END
  END d[49]
  PIN d[4]
    DIRECTION INPUT ;
    USE SIGNAL ;
    PORT
      LAYER M4 ;
        RECT  0 39.12 0.084 39.144 ;
    END
  END d[4]
  PIN d[500]
    DIRECTION INPUT ;
    USE SIGNAL ;
    PORT
      LAYER M4 ;
        RECT  0 53.712 0.084 53.736 ;
    END
  END d[500]
  PIN d[501]
    DIRECTION INPUT ;
    USE SIGNAL ;
    PORT
      LAYER M4 ;
        RECT  0 53.808 0.084 53.832 ;
    END
  END d[501]
  PIN d[502]
    DIRECTION INPUT ;
    USE SIGNAL ;
    PORT
      LAYER M4 ;
        RECT  0 53.904 0.084 53.928 ;
    END
  END d[502]
  PIN d[503]
    DIRECTION INPUT ;
    USE SIGNAL ;
    PORT
      LAYER M4 ;
        RECT  0 54 0.084 54.024 ;
    END
  END d[503]
  PIN d[504]
    DIRECTION INPUT ;
    USE SIGNAL ;
    PORT
      LAYER M4 ;
        RECT  0 54.096 0.084 54.12 ;
    END
  END d[504]
  PIN d[505]
    DIRECTION INPUT ;
    USE SIGNAL ;
    PORT
      LAYER M4 ;
        RECT  0 54.192 0.084 54.216 ;
    END
  END d[505]
  PIN d[506]
    DIRECTION INPUT ;
    USE SIGNAL ;
    PORT
      LAYER M4 ;
        RECT  0 54.288 0.084 54.312 ;
    END
  END d[506]
  PIN d[507]
    DIRECTION INPUT ;
    USE SIGNAL ;
    PORT
      LAYER M4 ;
        RECT  0 54.384 0.084 54.408 ;
    END
  END d[507]
  PIN d[508]
    DIRECTION INPUT ;
    USE SIGNAL ;
    PORT
      LAYER M4 ;
        RECT  0 54.48 0.084 54.504 ;
    END
  END d[508]
  PIN d[509]
    DIRECTION INPUT ;
    USE SIGNAL ;
    PORT
      LAYER M4 ;
        RECT  0 54.576 0.084 54.6 ;
    END
  END d[509]
  PIN d[50]
    DIRECTION INPUT ;
    USE SIGNAL ;
    PORT
      LAYER M4 ;
        RECT  0 31.248 0.084 31.272 ;
    END
  END d[50]
  PIN d[510]
    DIRECTION INPUT ;
    USE SIGNAL ;
    PORT
      LAYER M4 ;
        RECT  0 54.672 0.084 54.696 ;
    END
  END d[510]
  PIN d[511]
    DIRECTION INPUT ;
    USE SIGNAL ;
    PORT
      LAYER M4 ;
        RECT  0 54.768 0.084 54.792 ;
    END
  END d[511]
  PIN d[51]
    DIRECTION INPUT ;
    USE SIGNAL ;
    PORT
      LAYER M4 ;
        RECT  0 31.344 0.084 31.368 ;
    END
  END d[51]
  PIN d[52]
    DIRECTION INPUT ;
    USE SIGNAL ;
    PORT
      LAYER M4 ;
        RECT  0 31.44 0.084 31.464 ;
    END
  END d[52]
  PIN d[53]
    DIRECTION INPUT ;
    USE SIGNAL ;
    PORT
      LAYER M4 ;
        RECT  0 31.536 0.084 31.56 ;
    END
  END d[53]
  PIN d[54]
    DIRECTION INPUT ;
    USE SIGNAL ;
    PORT
      LAYER M4 ;
        RECT  0 31.632 0.084 31.656 ;
    END
  END d[54]
  PIN d[55]
    DIRECTION INPUT ;
    USE SIGNAL ;
    PORT
      LAYER M4 ;
        RECT  0 31.728 0.084 31.752 ;
    END
  END d[55]
  PIN d[56]
    DIRECTION INPUT ;
    USE SIGNAL ;
    PORT
      LAYER M4 ;
        RECT  0 31.824 0.084 31.848 ;
    END
  END d[56]
  PIN d[57]
    DIRECTION INPUT ;
    USE SIGNAL ;
    PORT
      LAYER M4 ;
        RECT  0 31.92 0.084 31.944 ;
    END
  END d[57]
  PIN d[58]
    DIRECTION INPUT ;
    USE SIGNAL ;
    PORT
      LAYER M4 ;
        RECT  0 32.016 0.084 32.04 ;
    END
  END d[58]
  PIN d[59]
    DIRECTION INPUT ;
    USE SIGNAL ;
    PORT
      LAYER M4 ;
        RECT  0 32.112 0.084 32.136 ;
    END
  END d[59]
  PIN d[5]
    DIRECTION INPUT ;
    USE SIGNAL ;
    PORT
      LAYER M4 ;
        RECT  0 39.216 0.084 39.24 ;
    END
  END d[5]
  PIN d[60]
    DIRECTION INPUT ;
    USE SIGNAL ;
    PORT
      LAYER M4 ;
        RECT  0 32.208 0.084 32.232 ;
    END
  END d[60]
  PIN d[61]
    DIRECTION INPUT ;
    USE SIGNAL ;
    PORT
      LAYER M4 ;
        RECT  0 32.304 0.084 32.328 ;
    END
  END d[61]
  PIN d[62]
    DIRECTION INPUT ;
    USE SIGNAL ;
    PORT
      LAYER M4 ;
        RECT  0 32.4 0.084 32.424 ;
    END
  END d[62]
  PIN d[63]
    DIRECTION INPUT ;
    USE SIGNAL ;
    PORT
      LAYER M4 ;
        RECT  0 32.496 0.084 32.52 ;
    END
  END d[63]
  PIN d[64]
    DIRECTION INPUT ;
    USE SIGNAL ;
    PORT
      LAYER M4 ;
        RECT  0 32.592 0.084 32.616 ;
    END
  END d[64]
  PIN d[65]
    DIRECTION INPUT ;
    USE SIGNAL ;
    PORT
      LAYER M4 ;
        RECT  0 32.688 0.084 32.712 ;
    END
  END d[65]
  PIN d[66]
    DIRECTION INPUT ;
    USE SIGNAL ;
    PORT
      LAYER M4 ;
        RECT  0 32.784 0.084 32.808 ;
    END
  END d[66]
  PIN d[67]
    DIRECTION INPUT ;
    USE SIGNAL ;
    PORT
      LAYER M4 ;
        RECT  0 32.88 0.084 32.904 ;
    END
  END d[67]
  PIN d[68]
    DIRECTION INPUT ;
    USE SIGNAL ;
    PORT
      LAYER M4 ;
        RECT  0 32.976 0.084 33 ;
    END
  END d[68]
  PIN d[69]
    DIRECTION INPUT ;
    USE SIGNAL ;
    PORT
      LAYER M4 ;
        RECT  0 33.072 0.084 33.096 ;
    END
  END d[69]
  PIN d[6]
    DIRECTION INPUT ;
    USE SIGNAL ;
    PORT
      LAYER M4 ;
        RECT  0 39.312 0.084 39.336 ;
    END
  END d[6]
  PIN d[70]
    DIRECTION INPUT ;
    USE SIGNAL ;
    PORT
      LAYER M4 ;
        RECT  0 33.168 0.084 33.192 ;
    END
  END d[70]
  PIN d[71]
    DIRECTION INPUT ;
    USE SIGNAL ;
    PORT
      LAYER M4 ;
        RECT  0 33.264 0.084 33.288 ;
    END
  END d[71]
  PIN d[72]
    DIRECTION INPUT ;
    USE SIGNAL ;
    PORT
      LAYER M4 ;
        RECT  0 33.36 0.084 33.384 ;
    END
  END d[72]
  PIN d[73]
    DIRECTION INPUT ;
    USE SIGNAL ;
    PORT
      LAYER M4 ;
        RECT  0 33.456 0.084 33.48 ;
    END
  END d[73]
  PIN d[74]
    DIRECTION INPUT ;
    USE SIGNAL ;
    PORT
      LAYER M4 ;
        RECT  0 33.552 0.084 33.576 ;
    END
  END d[74]
  PIN d[75]
    DIRECTION INPUT ;
    USE SIGNAL ;
    PORT
      LAYER M4 ;
        RECT  0 33.648 0.084 33.672 ;
    END
  END d[75]
  PIN d[76]
    DIRECTION INPUT ;
    USE SIGNAL ;
    PORT
      LAYER M4 ;
        RECT  0 33.744 0.084 33.768 ;
    END
  END d[76]
  PIN d[77]
    DIRECTION INPUT ;
    USE SIGNAL ;
    PORT
      LAYER M4 ;
        RECT  0 33.84 0.084 33.864 ;
    END
  END d[77]
  PIN d[78]
    DIRECTION INPUT ;
    USE SIGNAL ;
    PORT
      LAYER M4 ;
        RECT  0 33.936 0.084 33.96 ;
    END
  END d[78]
  PIN d[79]
    DIRECTION INPUT ;
    USE SIGNAL ;
    PORT
      LAYER M4 ;
        RECT  0 34.032 0.084 34.056 ;
    END
  END d[79]
  PIN d[7]
    DIRECTION INPUT ;
    USE SIGNAL ;
    PORT
      LAYER M4 ;
        RECT  0 39.408 0.084 39.432 ;
    END
  END d[7]
  PIN d[80]
    DIRECTION INPUT ;
    USE SIGNAL ;
    PORT
      LAYER M4 ;
        RECT  0 34.128 0.084 34.152 ;
    END
  END d[80]
  PIN d[81]
    DIRECTION INPUT ;
    USE SIGNAL ;
    PORT
      LAYER M4 ;
        RECT  0 34.224 0.084 34.248 ;
    END
  END d[81]
  PIN d[82]
    DIRECTION INPUT ;
    USE SIGNAL ;
    PORT
      LAYER M4 ;
        RECT  0 34.32 0.084 34.344 ;
    END
  END d[82]
  PIN d[83]
    DIRECTION INPUT ;
    USE SIGNAL ;
    PORT
      LAYER M4 ;
        RECT  0 34.416 0.084 34.44 ;
    END
  END d[83]
  PIN d[84]
    DIRECTION INPUT ;
    USE SIGNAL ;
    PORT
      LAYER M4 ;
        RECT  0 34.512 0.084 34.536 ;
    END
  END d[84]
  PIN d[85]
    DIRECTION INPUT ;
    USE SIGNAL ;
    PORT
      LAYER M4 ;
        RECT  0 34.608 0.084 34.632 ;
    END
  END d[85]
  PIN d[86]
    DIRECTION INPUT ;
    USE SIGNAL ;
    PORT
      LAYER M4 ;
        RECT  0 34.704 0.084 34.728 ;
    END
  END d[86]
  PIN d[87]
    DIRECTION INPUT ;
    USE SIGNAL ;
    PORT
      LAYER M4 ;
        RECT  0 34.8 0.084 34.824 ;
    END
  END d[87]
  PIN d[88]
    DIRECTION INPUT ;
    USE SIGNAL ;
    PORT
      LAYER M4 ;
        RECT  0 34.896 0.084 34.92 ;
    END
  END d[88]
  PIN d[89]
    DIRECTION INPUT ;
    USE SIGNAL ;
    PORT
      LAYER M4 ;
        RECT  0 34.992 0.084 35.016 ;
    END
  END d[89]
  PIN d[8]
    DIRECTION INPUT ;
    USE SIGNAL ;
    PORT
      LAYER M4 ;
        RECT  0 39.504 0.084 39.528 ;
    END
  END d[8]
  PIN d[90]
    DIRECTION INPUT ;
    USE SIGNAL ;
    PORT
      LAYER M4 ;
        RECT  0 35.088 0.084 35.112 ;
    END
  END d[90]
  PIN d[91]
    DIRECTION INPUT ;
    USE SIGNAL ;
    PORT
      LAYER M4 ;
        RECT  0 35.184 0.084 35.208 ;
    END
  END d[91]
  PIN d[92]
    DIRECTION INPUT ;
    USE SIGNAL ;
    PORT
      LAYER M4 ;
        RECT  0 35.28 0.084 35.304 ;
    END
  END d[92]
  PIN d[93]
    DIRECTION INPUT ;
    USE SIGNAL ;
    PORT
      LAYER M4 ;
        RECT  0 35.376 0.084 35.4 ;
    END
  END d[93]
  PIN d[94]
    DIRECTION INPUT ;
    USE SIGNAL ;
    PORT
      LAYER M4 ;
        RECT  0 35.472 0.084 35.496 ;
    END
  END d[94]
  PIN d[95]
    DIRECTION INPUT ;
    USE SIGNAL ;
    PORT
      LAYER M4 ;
        RECT  0 35.568 0.084 35.592 ;
    END
  END d[95]
  PIN d[96]
    DIRECTION INPUT ;
    USE SIGNAL ;
    PORT
      LAYER M4 ;
        RECT  0 41.808 0.084 41.832 ;
    END
  END d[96]
  PIN d[97]
    DIRECTION INPUT ;
    USE SIGNAL ;
    PORT
      LAYER M4 ;
        RECT  0 41.904 0.084 41.928 ;
    END
  END d[97]
  PIN d[98]
    DIRECTION INPUT ;
    USE SIGNAL ;
    PORT
      LAYER M4 ;
        RECT  0 42 0.084 42.024 ;
    END
  END d[98]
  PIN d[99]
    DIRECTION INPUT ;
    USE SIGNAL ;
    PORT
      LAYER M4 ;
        RECT  0 42.096 0.084 42.12 ;
    END
  END d[99]
  PIN d[9]
    DIRECTION INPUT ;
    USE SIGNAL ;
    PORT
      LAYER M4 ;
        RECT  0 39.6 0.084 39.624 ;
    END
  END d[9]
  PIN q[0]
    DIRECTION OUTPUT ;
    USE SIGNAL ;
    PORT
      LAYER M4 ;
        RECT  27.996 32.208 28.08 32.232 ;
    END
  END q[0]
  PIN q[100]
    DIRECTION OUTPUT ;
    USE SIGNAL ;
    PORT
      LAYER M4 ;
        RECT  27.996 35.664 28.08 35.688 ;
    END
  END q[100]
  PIN q[101]
    DIRECTION OUTPUT ;
    USE SIGNAL ;
    PORT
      LAYER M4 ;
        RECT  27.996 35.76 28.08 35.784 ;
    END
  END q[101]
  PIN q[102]
    DIRECTION OUTPUT ;
    USE SIGNAL ;
    PORT
      LAYER M4 ;
        RECT  27.996 35.856 28.08 35.88 ;
    END
  END q[102]
  PIN q[103]
    DIRECTION OUTPUT ;
    USE SIGNAL ;
    PORT
      LAYER M4 ;
        RECT  27.996 35.952 28.08 35.976 ;
    END
  END q[103]
  PIN q[104]
    DIRECTION OUTPUT ;
    USE SIGNAL ;
    PORT
      LAYER M4 ;
        RECT  27.996 36.048 28.08 36.072 ;
    END
  END q[104]
  PIN q[105]
    DIRECTION OUTPUT ;
    USE SIGNAL ;
    PORT
      LAYER M4 ;
        RECT  27.996 36.144 28.08 36.168 ;
    END
  END q[105]
  PIN q[106]
    DIRECTION OUTPUT ;
    USE SIGNAL ;
    PORT
      LAYER M4 ;
        RECT  27.996 36.24 28.08 36.264 ;
    END
  END q[106]
  PIN q[107]
    DIRECTION OUTPUT ;
    USE SIGNAL ;
    PORT
      LAYER M4 ;
        RECT  27.996 36.336 28.08 36.36 ;
    END
  END q[107]
  PIN q[108]
    DIRECTION OUTPUT ;
    USE SIGNAL ;
    PORT
      LAYER M4 ;
        RECT  27.996 36.432 28.08 36.456 ;
    END
  END q[108]
  PIN q[109]
    DIRECTION OUTPUT ;
    USE SIGNAL ;
    PORT
      LAYER M4 ;
        RECT  27.996 36.528 28.08 36.552 ;
    END
  END q[109]
  PIN q[10]
    DIRECTION OUTPUT ;
    USE SIGNAL ;
    PORT
      LAYER M4 ;
        RECT  27.996 33.168 28.08 33.192 ;
    END
  END q[10]
  PIN q[110]
    DIRECTION OUTPUT ;
    USE SIGNAL ;
    PORT
      LAYER M4 ;
        RECT  27.996 36.624 28.08 36.648 ;
    END
  END q[110]
  PIN q[111]
    DIRECTION OUTPUT ;
    USE SIGNAL ;
    PORT
      LAYER M4 ;
        RECT  27.996 36.72 28.08 36.744 ;
    END
  END q[111]
  PIN q[112]
    DIRECTION OUTPUT ;
    USE SIGNAL ;
    PORT
      LAYER M4 ;
        RECT  27.996 36.816 28.08 36.84 ;
    END
  END q[112]
  PIN q[113]
    DIRECTION OUTPUT ;
    USE SIGNAL ;
    PORT
      LAYER M4 ;
        RECT  27.996 36.912 28.08 36.936 ;
    END
  END q[113]
  PIN q[114]
    DIRECTION OUTPUT ;
    USE SIGNAL ;
    PORT
      LAYER M4 ;
        RECT  27.996 37.008 28.08 37.032 ;
    END
  END q[114]
  PIN q[115]
    DIRECTION OUTPUT ;
    USE SIGNAL ;
    PORT
      LAYER M4 ;
        RECT  27.996 37.104 28.08 37.128 ;
    END
  END q[115]
  PIN q[116]
    DIRECTION OUTPUT ;
    USE SIGNAL ;
    PORT
      LAYER M4 ;
        RECT  27.996 37.2 28.08 37.224 ;
    END
  END q[116]
  PIN q[117]
    DIRECTION OUTPUT ;
    USE SIGNAL ;
    PORT
      LAYER M4 ;
        RECT  27.996 37.296 28.08 37.32 ;
    END
  END q[117]
  PIN q[118]
    DIRECTION OUTPUT ;
    USE SIGNAL ;
    PORT
      LAYER M4 ;
        RECT  27.996 37.392 28.08 37.416 ;
    END
  END q[118]
  PIN q[119]
    DIRECTION OUTPUT ;
    USE SIGNAL ;
    PORT
      LAYER M4 ;
        RECT  27.996 37.488 28.08 37.512 ;
    END
  END q[119]
  PIN q[11]
    DIRECTION OUTPUT ;
    USE SIGNAL ;
    PORT
      LAYER M4 ;
        RECT  27.996 33.264 28.08 33.288 ;
    END
  END q[11]
  PIN q[120]
    DIRECTION OUTPUT ;
    USE SIGNAL ;
    PORT
      LAYER M4 ;
        RECT  27.996 37.584 28.08 37.608 ;
    END
  END q[120]
  PIN q[121]
    DIRECTION OUTPUT ;
    USE SIGNAL ;
    PORT
      LAYER M4 ;
        RECT  27.996 37.68 28.08 37.704 ;
    END
  END q[121]
  PIN q[122]
    DIRECTION OUTPUT ;
    USE SIGNAL ;
    PORT
      LAYER M4 ;
        RECT  27.996 37.776 28.08 37.8 ;
    END
  END q[122]
  PIN q[123]
    DIRECTION OUTPUT ;
    USE SIGNAL ;
    PORT
      LAYER M4 ;
        RECT  27.996 37.872 28.08 37.896 ;
    END
  END q[123]
  PIN q[124]
    DIRECTION OUTPUT ;
    USE SIGNAL ;
    PORT
      LAYER M4 ;
        RECT  27.996 37.968 28.08 37.992 ;
    END
  END q[124]
  PIN q[125]
    DIRECTION OUTPUT ;
    USE SIGNAL ;
    PORT
      LAYER M4 ;
        RECT  27.996 38.064 28.08 38.088 ;
    END
  END q[125]
  PIN q[126]
    DIRECTION OUTPUT ;
    USE SIGNAL ;
    PORT
      LAYER M4 ;
        RECT  27.996 38.16 28.08 38.184 ;
    END
  END q[126]
  PIN q[127]
    DIRECTION OUTPUT ;
    USE SIGNAL ;
    PORT
      LAYER M4 ;
        RECT  27.996 38.256 28.08 38.28 ;
    END
  END q[127]
  PIN q[128]
    DIRECTION OUTPUT ;
    USE SIGNAL ;
    PORT
      LAYER M4 ;
        RECT  27.996 19.92 28.08 19.944 ;
    END
  END q[128]
  PIN q[129]
    DIRECTION OUTPUT ;
    USE SIGNAL ;
    PORT
      LAYER M4 ;
        RECT  27.996 20.016 28.08 20.04 ;
    END
  END q[129]
  PIN q[12]
    DIRECTION OUTPUT ;
    USE SIGNAL ;
    PORT
      LAYER M4 ;
        RECT  27.996 33.36 28.08 33.384 ;
    END
  END q[12]
  PIN q[130]
    DIRECTION OUTPUT ;
    USE SIGNAL ;
    PORT
      LAYER M4 ;
        RECT  27.996 20.112 28.08 20.136 ;
    END
  END q[130]
  PIN q[131]
    DIRECTION OUTPUT ;
    USE SIGNAL ;
    PORT
      LAYER M4 ;
        RECT  27.996 20.208 28.08 20.232 ;
    END
  END q[131]
  PIN q[132]
    DIRECTION OUTPUT ;
    USE SIGNAL ;
    PORT
      LAYER M4 ;
        RECT  27.996 20.304 28.08 20.328 ;
    END
  END q[132]
  PIN q[133]
    DIRECTION OUTPUT ;
    USE SIGNAL ;
    PORT
      LAYER M4 ;
        RECT  27.996 20.4 28.08 20.424 ;
    END
  END q[133]
  PIN q[134]
    DIRECTION OUTPUT ;
    USE SIGNAL ;
    PORT
      LAYER M4 ;
        RECT  27.996 20.496 28.08 20.52 ;
    END
  END q[134]
  PIN q[135]
    DIRECTION OUTPUT ;
    USE SIGNAL ;
    PORT
      LAYER M4 ;
        RECT  27.996 20.592 28.08 20.616 ;
    END
  END q[135]
  PIN q[136]
    DIRECTION OUTPUT ;
    USE SIGNAL ;
    PORT
      LAYER M4 ;
        RECT  27.996 20.688 28.08 20.712 ;
    END
  END q[136]
  PIN q[137]
    DIRECTION OUTPUT ;
    USE SIGNAL ;
    PORT
      LAYER M4 ;
        RECT  27.996 20.784 28.08 20.808 ;
    END
  END q[137]
  PIN q[138]
    DIRECTION OUTPUT ;
    USE SIGNAL ;
    PORT
      LAYER M4 ;
        RECT  27.996 20.88 28.08 20.904 ;
    END
  END q[138]
  PIN q[139]
    DIRECTION OUTPUT ;
    USE SIGNAL ;
    PORT
      LAYER M4 ;
        RECT  27.996 20.976 28.08 21 ;
    END
  END q[139]
  PIN q[13]
    DIRECTION OUTPUT ;
    USE SIGNAL ;
    PORT
      LAYER M4 ;
        RECT  27.996 33.456 28.08 33.48 ;
    END
  END q[13]
  PIN q[140]
    DIRECTION OUTPUT ;
    USE SIGNAL ;
    PORT
      LAYER M4 ;
        RECT  27.996 21.072 28.08 21.096 ;
    END
  END q[140]
  PIN q[141]
    DIRECTION OUTPUT ;
    USE SIGNAL ;
    PORT
      LAYER M4 ;
        RECT  27.996 21.168 28.08 21.192 ;
    END
  END q[141]
  PIN q[142]
    DIRECTION OUTPUT ;
    USE SIGNAL ;
    PORT
      LAYER M4 ;
        RECT  27.996 21.264 28.08 21.288 ;
    END
  END q[142]
  PIN q[143]
    DIRECTION OUTPUT ;
    USE SIGNAL ;
    PORT
      LAYER M4 ;
        RECT  27.996 21.36 28.08 21.384 ;
    END
  END q[143]
  PIN q[144]
    DIRECTION OUTPUT ;
    USE SIGNAL ;
    PORT
      LAYER M4 ;
        RECT  27.996 21.456 28.08 21.48 ;
    END
  END q[144]
  PIN q[145]
    DIRECTION OUTPUT ;
    USE SIGNAL ;
    PORT
      LAYER M4 ;
        RECT  27.996 21.552 28.08 21.576 ;
    END
  END q[145]
  PIN q[146]
    DIRECTION OUTPUT ;
    USE SIGNAL ;
    PORT
      LAYER M4 ;
        RECT  27.996 21.648 28.08 21.672 ;
    END
  END q[146]
  PIN q[147]
    DIRECTION OUTPUT ;
    USE SIGNAL ;
    PORT
      LAYER M4 ;
        RECT  27.996 21.744 28.08 21.768 ;
    END
  END q[147]
  PIN q[148]
    DIRECTION OUTPUT ;
    USE SIGNAL ;
    PORT
      LAYER M4 ;
        RECT  27.996 21.84 28.08 21.864 ;
    END
  END q[148]
  PIN q[149]
    DIRECTION OUTPUT ;
    USE SIGNAL ;
    PORT
      LAYER M4 ;
        RECT  27.996 21.936 28.08 21.96 ;
    END
  END q[149]
  PIN q[14]
    DIRECTION OUTPUT ;
    USE SIGNAL ;
    PORT
      LAYER M4 ;
        RECT  27.996 33.552 28.08 33.576 ;
    END
  END q[14]
  PIN q[150]
    DIRECTION OUTPUT ;
    USE SIGNAL ;
    PORT
      LAYER M4 ;
        RECT  27.996 22.032 28.08 22.056 ;
    END
  END q[150]
  PIN q[151]
    DIRECTION OUTPUT ;
    USE SIGNAL ;
    PORT
      LAYER M4 ;
        RECT  27.996 22.128 28.08 22.152 ;
    END
  END q[151]
  PIN q[152]
    DIRECTION OUTPUT ;
    USE SIGNAL ;
    PORT
      LAYER M4 ;
        RECT  27.996 22.224 28.08 22.248 ;
    END
  END q[152]
  PIN q[153]
    DIRECTION OUTPUT ;
    USE SIGNAL ;
    PORT
      LAYER M4 ;
        RECT  27.996 22.32 28.08 22.344 ;
    END
  END q[153]
  PIN q[154]
    DIRECTION OUTPUT ;
    USE SIGNAL ;
    PORT
      LAYER M4 ;
        RECT  27.996 22.416 28.08 22.44 ;
    END
  END q[154]
  PIN q[155]
    DIRECTION OUTPUT ;
    USE SIGNAL ;
    PORT
      LAYER M4 ;
        RECT  27.996 22.512 28.08 22.536 ;
    END
  END q[155]
  PIN q[156]
    DIRECTION OUTPUT ;
    USE SIGNAL ;
    PORT
      LAYER M4 ;
        RECT  27.996 22.608 28.08 22.632 ;
    END
  END q[156]
  PIN q[157]
    DIRECTION OUTPUT ;
    USE SIGNAL ;
    PORT
      LAYER M4 ;
        RECT  27.996 22.704 28.08 22.728 ;
    END
  END q[157]
  PIN q[158]
    DIRECTION OUTPUT ;
    USE SIGNAL ;
    PORT
      LAYER M4 ;
        RECT  27.996 22.8 28.08 22.824 ;
    END
  END q[158]
  PIN q[159]
    DIRECTION OUTPUT ;
    USE SIGNAL ;
    PORT
      LAYER M4 ;
        RECT  27.996 22.896 28.08 22.92 ;
    END
  END q[159]
  PIN q[15]
    DIRECTION OUTPUT ;
    USE SIGNAL ;
    PORT
      LAYER M4 ;
        RECT  27.996 33.648 28.08 33.672 ;
    END
  END q[15]
  PIN q[160]
    DIRECTION OUTPUT ;
    USE SIGNAL ;
    PORT
      LAYER M4 ;
        RECT  27.996 29.136 28.08 29.16 ;
    END
  END q[160]
  PIN q[161]
    DIRECTION OUTPUT ;
    USE SIGNAL ;
    PORT
      LAYER M4 ;
        RECT  27.996 29.232 28.08 29.256 ;
    END
  END q[161]
  PIN q[162]
    DIRECTION OUTPUT ;
    USE SIGNAL ;
    PORT
      LAYER M4 ;
        RECT  27.996 29.328 28.08 29.352 ;
    END
  END q[162]
  PIN q[163]
    DIRECTION OUTPUT ;
    USE SIGNAL ;
    PORT
      LAYER M4 ;
        RECT  27.996 29.424 28.08 29.448 ;
    END
  END q[163]
  PIN q[164]
    DIRECTION OUTPUT ;
    USE SIGNAL ;
    PORT
      LAYER M4 ;
        RECT  27.996 29.52 28.08 29.544 ;
    END
  END q[164]
  PIN q[165]
    DIRECTION OUTPUT ;
    USE SIGNAL ;
    PORT
      LAYER M4 ;
        RECT  27.996 29.616 28.08 29.64 ;
    END
  END q[165]
  PIN q[166]
    DIRECTION OUTPUT ;
    USE SIGNAL ;
    PORT
      LAYER M4 ;
        RECT  27.996 29.712 28.08 29.736 ;
    END
  END q[166]
  PIN q[167]
    DIRECTION OUTPUT ;
    USE SIGNAL ;
    PORT
      LAYER M4 ;
        RECT  27.996 29.808 28.08 29.832 ;
    END
  END q[167]
  PIN q[168]
    DIRECTION OUTPUT ;
    USE SIGNAL ;
    PORT
      LAYER M4 ;
        RECT  27.996 29.904 28.08 29.928 ;
    END
  END q[168]
  PIN q[169]
    DIRECTION OUTPUT ;
    USE SIGNAL ;
    PORT
      LAYER M4 ;
        RECT  27.996 30 28.08 30.024 ;
    END
  END q[169]
  PIN q[16]
    DIRECTION OUTPUT ;
    USE SIGNAL ;
    PORT
      LAYER M4 ;
        RECT  27.996 33.744 28.08 33.768 ;
    END
  END q[16]
  PIN q[170]
    DIRECTION OUTPUT ;
    USE SIGNAL ;
    PORT
      LAYER M4 ;
        RECT  27.996 30.096 28.08 30.12 ;
    END
  END q[170]
  PIN q[171]
    DIRECTION OUTPUT ;
    USE SIGNAL ;
    PORT
      LAYER M4 ;
        RECT  27.996 30.192 28.08 30.216 ;
    END
  END q[171]
  PIN q[172]
    DIRECTION OUTPUT ;
    USE SIGNAL ;
    PORT
      LAYER M4 ;
        RECT  27.996 30.288 28.08 30.312 ;
    END
  END q[172]
  PIN q[173]
    DIRECTION OUTPUT ;
    USE SIGNAL ;
    PORT
      LAYER M4 ;
        RECT  27.996 30.384 28.08 30.408 ;
    END
  END q[173]
  PIN q[174]
    DIRECTION OUTPUT ;
    USE SIGNAL ;
    PORT
      LAYER M4 ;
        RECT  27.996 30.48 28.08 30.504 ;
    END
  END q[174]
  PIN q[175]
    DIRECTION OUTPUT ;
    USE SIGNAL ;
    PORT
      LAYER M4 ;
        RECT  27.996 30.576 28.08 30.6 ;
    END
  END q[175]
  PIN q[176]
    DIRECTION OUTPUT ;
    USE SIGNAL ;
    PORT
      LAYER M4 ;
        RECT  27.996 30.672 28.08 30.696 ;
    END
  END q[176]
  PIN q[177]
    DIRECTION OUTPUT ;
    USE SIGNAL ;
    PORT
      LAYER M4 ;
        RECT  27.996 30.768 28.08 30.792 ;
    END
  END q[177]
  PIN q[178]
    DIRECTION OUTPUT ;
    USE SIGNAL ;
    PORT
      LAYER M4 ;
        RECT  27.996 30.864 28.08 30.888 ;
    END
  END q[178]
  PIN q[179]
    DIRECTION OUTPUT ;
    USE SIGNAL ;
    PORT
      LAYER M4 ;
        RECT  27.996 30.96 28.08 30.984 ;
    END
  END q[179]
  PIN q[17]
    DIRECTION OUTPUT ;
    USE SIGNAL ;
    PORT
      LAYER M4 ;
        RECT  27.996 33.84 28.08 33.864 ;
    END
  END q[17]
  PIN q[180]
    DIRECTION OUTPUT ;
    USE SIGNAL ;
    PORT
      LAYER M4 ;
        RECT  27.996 31.056 28.08 31.08 ;
    END
  END q[180]
  PIN q[181]
    DIRECTION OUTPUT ;
    USE SIGNAL ;
    PORT
      LAYER M4 ;
        RECT  27.996 31.152 28.08 31.176 ;
    END
  END q[181]
  PIN q[182]
    DIRECTION OUTPUT ;
    USE SIGNAL ;
    PORT
      LAYER M4 ;
        RECT  27.996 31.248 28.08 31.272 ;
    END
  END q[182]
  PIN q[183]
    DIRECTION OUTPUT ;
    USE SIGNAL ;
    PORT
      LAYER M4 ;
        RECT  27.996 31.344 28.08 31.368 ;
    END
  END q[183]
  PIN q[184]
    DIRECTION OUTPUT ;
    USE SIGNAL ;
    PORT
      LAYER M4 ;
        RECT  27.996 31.44 28.08 31.464 ;
    END
  END q[184]
  PIN q[185]
    DIRECTION OUTPUT ;
    USE SIGNAL ;
    PORT
      LAYER M4 ;
        RECT  27.996 31.536 28.08 31.56 ;
    END
  END q[185]
  PIN q[186]
    DIRECTION OUTPUT ;
    USE SIGNAL ;
    PORT
      LAYER M4 ;
        RECT  27.996 31.632 28.08 31.656 ;
    END
  END q[186]
  PIN q[187]
    DIRECTION OUTPUT ;
    USE SIGNAL ;
    PORT
      LAYER M4 ;
        RECT  27.996 31.728 28.08 31.752 ;
    END
  END q[187]
  PIN q[188]
    DIRECTION OUTPUT ;
    USE SIGNAL ;
    PORT
      LAYER M4 ;
        RECT  27.996 31.824 28.08 31.848 ;
    END
  END q[188]
  PIN q[189]
    DIRECTION OUTPUT ;
    USE SIGNAL ;
    PORT
      LAYER M4 ;
        RECT  27.996 31.92 28.08 31.944 ;
    END
  END q[189]
  PIN q[18]
    DIRECTION OUTPUT ;
    USE SIGNAL ;
    PORT
      LAYER M4 ;
        RECT  27.996 33.936 28.08 33.96 ;
    END
  END q[18]
  PIN q[190]
    DIRECTION OUTPUT ;
    USE SIGNAL ;
    PORT
      LAYER M4 ;
        RECT  27.996 32.016 28.08 32.04 ;
    END
  END q[190]
  PIN q[191]
    DIRECTION OUTPUT ;
    USE SIGNAL ;
    PORT
      LAYER M4 ;
        RECT  27.996 32.112 28.08 32.136 ;
    END
  END q[191]
  PIN q[192]
    DIRECTION OUTPUT ;
    USE SIGNAL ;
    PORT
      LAYER M4 ;
        RECT  27.996 39.12 28.08 39.144 ;
    END
  END q[192]
  PIN q[193]
    DIRECTION OUTPUT ;
    USE SIGNAL ;
    PORT
      LAYER M4 ;
        RECT  27.996 39.216 28.08 39.24 ;
    END
  END q[193]
  PIN q[194]
    DIRECTION OUTPUT ;
    USE SIGNAL ;
    PORT
      LAYER M4 ;
        RECT  27.996 39.312 28.08 39.336 ;
    END
  END q[194]
  PIN q[195]
    DIRECTION OUTPUT ;
    USE SIGNAL ;
    PORT
      LAYER M4 ;
        RECT  27.996 39.408 28.08 39.432 ;
    END
  END q[195]
  PIN q[196]
    DIRECTION OUTPUT ;
    USE SIGNAL ;
    PORT
      LAYER M4 ;
        RECT  27.996 39.504 28.08 39.528 ;
    END
  END q[196]
  PIN q[197]
    DIRECTION OUTPUT ;
    USE SIGNAL ;
    PORT
      LAYER M4 ;
        RECT  27.996 39.6 28.08 39.624 ;
    END
  END q[197]
  PIN q[198]
    DIRECTION OUTPUT ;
    USE SIGNAL ;
    PORT
      LAYER M4 ;
        RECT  27.996 39.696 28.08 39.72 ;
    END
  END q[198]
  PIN q[199]
    DIRECTION OUTPUT ;
    USE SIGNAL ;
    PORT
      LAYER M4 ;
        RECT  27.996 39.792 28.08 39.816 ;
    END
  END q[199]
  PIN q[19]
    DIRECTION OUTPUT ;
    USE SIGNAL ;
    PORT
      LAYER M4 ;
        RECT  27.996 34.032 28.08 34.056 ;
    END
  END q[19]
  PIN q[1]
    DIRECTION OUTPUT ;
    USE SIGNAL ;
    PORT
      LAYER M4 ;
        RECT  27.996 32.304 28.08 32.328 ;
    END
  END q[1]
  PIN q[200]
    DIRECTION OUTPUT ;
    USE SIGNAL ;
    PORT
      LAYER M4 ;
        RECT  27.996 39.888 28.08 39.912 ;
    END
  END q[200]
  PIN q[201]
    DIRECTION OUTPUT ;
    USE SIGNAL ;
    PORT
      LAYER M4 ;
        RECT  27.996 39.984 28.08 40.008 ;
    END
  END q[201]
  PIN q[202]
    DIRECTION OUTPUT ;
    USE SIGNAL ;
    PORT
      LAYER M4 ;
        RECT  27.996 40.08 28.08 40.104 ;
    END
  END q[202]
  PIN q[203]
    DIRECTION OUTPUT ;
    USE SIGNAL ;
    PORT
      LAYER M4 ;
        RECT  27.996 40.176 28.08 40.2 ;
    END
  END q[203]
  PIN q[204]
    DIRECTION OUTPUT ;
    USE SIGNAL ;
    PORT
      LAYER M4 ;
        RECT  27.996 40.272 28.08 40.296 ;
    END
  END q[204]
  PIN q[205]
    DIRECTION OUTPUT ;
    USE SIGNAL ;
    PORT
      LAYER M4 ;
        RECT  27.996 40.368 28.08 40.392 ;
    END
  END q[205]
  PIN q[206]
    DIRECTION OUTPUT ;
    USE SIGNAL ;
    PORT
      LAYER M4 ;
        RECT  27.996 40.464 28.08 40.488 ;
    END
  END q[206]
  PIN q[207]
    DIRECTION OUTPUT ;
    USE SIGNAL ;
    PORT
      LAYER M4 ;
        RECT  27.996 40.56 28.08 40.584 ;
    END
  END q[207]
  PIN q[208]
    DIRECTION OUTPUT ;
    USE SIGNAL ;
    PORT
      LAYER M4 ;
        RECT  27.996 40.656 28.08 40.68 ;
    END
  END q[208]
  PIN q[209]
    DIRECTION OUTPUT ;
    USE SIGNAL ;
    PORT
      LAYER M4 ;
        RECT  27.996 40.752 28.08 40.776 ;
    END
  END q[209]
  PIN q[20]
    DIRECTION OUTPUT ;
    USE SIGNAL ;
    PORT
      LAYER M4 ;
        RECT  27.996 34.128 28.08 34.152 ;
    END
  END q[20]
  PIN q[210]
    DIRECTION OUTPUT ;
    USE SIGNAL ;
    PORT
      LAYER M4 ;
        RECT  27.996 40.848 28.08 40.872 ;
    END
  END q[210]
  PIN q[211]
    DIRECTION OUTPUT ;
    USE SIGNAL ;
    PORT
      LAYER M4 ;
        RECT  27.996 40.944 28.08 40.968 ;
    END
  END q[211]
  PIN q[212]
    DIRECTION OUTPUT ;
    USE SIGNAL ;
    PORT
      LAYER M4 ;
        RECT  27.996 41.04 28.08 41.064 ;
    END
  END q[212]
  PIN q[213]
    DIRECTION OUTPUT ;
    USE SIGNAL ;
    PORT
      LAYER M4 ;
        RECT  27.996 41.136 28.08 41.16 ;
    END
  END q[213]
  PIN q[214]
    DIRECTION OUTPUT ;
    USE SIGNAL ;
    PORT
      LAYER M4 ;
        RECT  27.996 41.232 28.08 41.256 ;
    END
  END q[214]
  PIN q[215]
    DIRECTION OUTPUT ;
    USE SIGNAL ;
    PORT
      LAYER M4 ;
        RECT  27.996 41.328 28.08 41.352 ;
    END
  END q[215]
  PIN q[216]
    DIRECTION OUTPUT ;
    USE SIGNAL ;
    PORT
      LAYER M4 ;
        RECT  27.996 41.424 28.08 41.448 ;
    END
  END q[216]
  PIN q[217]
    DIRECTION OUTPUT ;
    USE SIGNAL ;
    PORT
      LAYER M4 ;
        RECT  27.996 41.52 28.08 41.544 ;
    END
  END q[217]
  PIN q[218]
    DIRECTION OUTPUT ;
    USE SIGNAL ;
    PORT
      LAYER M4 ;
        RECT  27.996 41.616 28.08 41.64 ;
    END
  END q[218]
  PIN q[219]
    DIRECTION OUTPUT ;
    USE SIGNAL ;
    PORT
      LAYER M4 ;
        RECT  27.996 41.712 28.08 41.736 ;
    END
  END q[219]
  PIN q[21]
    DIRECTION OUTPUT ;
    USE SIGNAL ;
    PORT
      LAYER M4 ;
        RECT  27.996 34.224 28.08 34.248 ;
    END
  END q[21]
  PIN q[220]
    DIRECTION OUTPUT ;
    USE SIGNAL ;
    PORT
      LAYER M4 ;
        RECT  27.996 41.808 28.08 41.832 ;
    END
  END q[220]
  PIN q[221]
    DIRECTION OUTPUT ;
    USE SIGNAL ;
    PORT
      LAYER M4 ;
        RECT  27.996 41.904 28.08 41.928 ;
    END
  END q[221]
  PIN q[222]
    DIRECTION OUTPUT ;
    USE SIGNAL ;
    PORT
      LAYER M4 ;
        RECT  27.996 42 28.08 42.024 ;
    END
  END q[222]
  PIN q[223]
    DIRECTION OUTPUT ;
    USE SIGNAL ;
    PORT
      LAYER M4 ;
        RECT  27.996 42.096 28.08 42.12 ;
    END
  END q[223]
  PIN q[224]
    DIRECTION OUTPUT ;
    USE SIGNAL ;
    PORT
      LAYER M4 ;
        RECT  27.996 45.264 28.08 45.288 ;
    END
  END q[224]
  PIN q[225]
    DIRECTION OUTPUT ;
    USE SIGNAL ;
    PORT
      LAYER M4 ;
        RECT  27.996 45.36 28.08 45.384 ;
    END
  END q[225]
  PIN q[226]
    DIRECTION OUTPUT ;
    USE SIGNAL ;
    PORT
      LAYER M4 ;
        RECT  27.996 45.456 28.08 45.48 ;
    END
  END q[226]
  PIN q[227]
    DIRECTION OUTPUT ;
    USE SIGNAL ;
    PORT
      LAYER M4 ;
        RECT  27.996 45.552 28.08 45.576 ;
    END
  END q[227]
  PIN q[228]
    DIRECTION OUTPUT ;
    USE SIGNAL ;
    PORT
      LAYER M4 ;
        RECT  27.996 45.648 28.08 45.672 ;
    END
  END q[228]
  PIN q[229]
    DIRECTION OUTPUT ;
    USE SIGNAL ;
    PORT
      LAYER M4 ;
        RECT  27.996 45.744 28.08 45.768 ;
    END
  END q[229]
  PIN q[22]
    DIRECTION OUTPUT ;
    USE SIGNAL ;
    PORT
      LAYER M4 ;
        RECT  27.996 34.32 28.08 34.344 ;
    END
  END q[22]
  PIN q[230]
    DIRECTION OUTPUT ;
    USE SIGNAL ;
    PORT
      LAYER M4 ;
        RECT  27.996 45.84 28.08 45.864 ;
    END
  END q[230]
  PIN q[231]
    DIRECTION OUTPUT ;
    USE SIGNAL ;
    PORT
      LAYER M4 ;
        RECT  27.996 45.936 28.08 45.96 ;
    END
  END q[231]
  PIN q[232]
    DIRECTION OUTPUT ;
    USE SIGNAL ;
    PORT
      LAYER M4 ;
        RECT  27.996 46.032 28.08 46.056 ;
    END
  END q[232]
  PIN q[233]
    DIRECTION OUTPUT ;
    USE SIGNAL ;
    PORT
      LAYER M4 ;
        RECT  27.996 46.128 28.08 46.152 ;
    END
  END q[233]
  PIN q[234]
    DIRECTION OUTPUT ;
    USE SIGNAL ;
    PORT
      LAYER M4 ;
        RECT  27.996 46.224 28.08 46.248 ;
    END
  END q[234]
  PIN q[235]
    DIRECTION OUTPUT ;
    USE SIGNAL ;
    PORT
      LAYER M4 ;
        RECT  27.996 46.32 28.08 46.344 ;
    END
  END q[235]
  PIN q[236]
    DIRECTION OUTPUT ;
    USE SIGNAL ;
    PORT
      LAYER M4 ;
        RECT  27.996 46.416 28.08 46.44 ;
    END
  END q[236]
  PIN q[237]
    DIRECTION OUTPUT ;
    USE SIGNAL ;
    PORT
      LAYER M4 ;
        RECT  27.996 46.512 28.08 46.536 ;
    END
  END q[237]
  PIN q[238]
    DIRECTION OUTPUT ;
    USE SIGNAL ;
    PORT
      LAYER M4 ;
        RECT  27.996 46.608 28.08 46.632 ;
    END
  END q[238]
  PIN q[239]
    DIRECTION OUTPUT ;
    USE SIGNAL ;
    PORT
      LAYER M4 ;
        RECT  27.996 46.704 28.08 46.728 ;
    END
  END q[239]
  PIN q[23]
    DIRECTION OUTPUT ;
    USE SIGNAL ;
    PORT
      LAYER M4 ;
        RECT  27.996 34.416 28.08 34.44 ;
    END
  END q[23]
  PIN q[240]
    DIRECTION OUTPUT ;
    USE SIGNAL ;
    PORT
      LAYER M4 ;
        RECT  27.996 46.8 28.08 46.824 ;
    END
  END q[240]
  PIN q[241]
    DIRECTION OUTPUT ;
    USE SIGNAL ;
    PORT
      LAYER M4 ;
        RECT  27.996 46.896 28.08 46.92 ;
    END
  END q[241]
  PIN q[242]
    DIRECTION OUTPUT ;
    USE SIGNAL ;
    PORT
      LAYER M4 ;
        RECT  27.996 46.992 28.08 47.016 ;
    END
  END q[242]
  PIN q[243]
    DIRECTION OUTPUT ;
    USE SIGNAL ;
    PORT
      LAYER M4 ;
        RECT  27.996 47.088 28.08 47.112 ;
    END
  END q[243]
  PIN q[244]
    DIRECTION OUTPUT ;
    USE SIGNAL ;
    PORT
      LAYER M4 ;
        RECT  27.996 47.184 28.08 47.208 ;
    END
  END q[244]
  PIN q[245]
    DIRECTION OUTPUT ;
    USE SIGNAL ;
    PORT
      LAYER M4 ;
        RECT  27.996 47.28 28.08 47.304 ;
    END
  END q[245]
  PIN q[246]
    DIRECTION OUTPUT ;
    USE SIGNAL ;
    PORT
      LAYER M4 ;
        RECT  27.996 47.376 28.08 47.4 ;
    END
  END q[246]
  PIN q[247]
    DIRECTION OUTPUT ;
    USE SIGNAL ;
    PORT
      LAYER M4 ;
        RECT  27.996 47.472 28.08 47.496 ;
    END
  END q[247]
  PIN q[248]
    DIRECTION OUTPUT ;
    USE SIGNAL ;
    PORT
      LAYER M4 ;
        RECT  27.996 47.568 28.08 47.592 ;
    END
  END q[248]
  PIN q[249]
    DIRECTION OUTPUT ;
    USE SIGNAL ;
    PORT
      LAYER M4 ;
        RECT  27.996 47.664 28.08 47.688 ;
    END
  END q[249]
  PIN q[24]
    DIRECTION OUTPUT ;
    USE SIGNAL ;
    PORT
      LAYER M4 ;
        RECT  27.996 34.512 28.08 34.536 ;
    END
  END q[24]
  PIN q[250]
    DIRECTION OUTPUT ;
    USE SIGNAL ;
    PORT
      LAYER M4 ;
        RECT  27.996 47.76 28.08 47.784 ;
    END
  END q[250]
  PIN q[251]
    DIRECTION OUTPUT ;
    USE SIGNAL ;
    PORT
      LAYER M4 ;
        RECT  27.996 47.856 28.08 47.88 ;
    END
  END q[251]
  PIN q[252]
    DIRECTION OUTPUT ;
    USE SIGNAL ;
    PORT
      LAYER M4 ;
        RECT  27.996 47.952 28.08 47.976 ;
    END
  END q[252]
  PIN q[253]
    DIRECTION OUTPUT ;
    USE SIGNAL ;
    PORT
      LAYER M4 ;
        RECT  27.996 48.048 28.08 48.072 ;
    END
  END q[253]
  PIN q[254]
    DIRECTION OUTPUT ;
    USE SIGNAL ;
    PORT
      LAYER M4 ;
        RECT  27.996 48.144 28.08 48.168 ;
    END
  END q[254]
  PIN q[255]
    DIRECTION OUTPUT ;
    USE SIGNAL ;
    PORT
      LAYER M4 ;
        RECT  27.996 48.24 28.08 48.264 ;
    END
  END q[255]
  PIN q[256]
    DIRECTION OUTPUT ;
    USE SIGNAL ;
    PORT
      LAYER M4 ;
        RECT  27.996 54.48 28.08 54.504 ;
    END
  END q[256]
  PIN q[257]
    DIRECTION OUTPUT ;
    USE SIGNAL ;
    PORT
      LAYER M4 ;
        RECT  27.996 54.576 28.08 54.6 ;
    END
  END q[257]
  PIN q[258]
    DIRECTION OUTPUT ;
    USE SIGNAL ;
    PORT
      LAYER M4 ;
        RECT  27.996 54.672 28.08 54.696 ;
    END
  END q[258]
  PIN q[259]
    DIRECTION OUTPUT ;
    USE SIGNAL ;
    PORT
      LAYER M4 ;
        RECT  27.996 54.768 28.08 54.792 ;
    END
  END q[259]
  PIN q[25]
    DIRECTION OUTPUT ;
    USE SIGNAL ;
    PORT
      LAYER M4 ;
        RECT  27.996 34.608 28.08 34.632 ;
    END
  END q[25]
  PIN q[260]
    DIRECTION OUTPUT ;
    USE SIGNAL ;
    PORT
      LAYER M4 ;
        RECT  27.996 54.864 28.08 54.888 ;
    END
  END q[260]
  PIN q[261]
    DIRECTION OUTPUT ;
    USE SIGNAL ;
    PORT
      LAYER M4 ;
        RECT  27.996 54.96 28.08 54.984 ;
    END
  END q[261]
  PIN q[262]
    DIRECTION OUTPUT ;
    USE SIGNAL ;
    PORT
      LAYER M4 ;
        RECT  27.996 55.056 28.08 55.08 ;
    END
  END q[262]
  PIN q[263]
    DIRECTION OUTPUT ;
    USE SIGNAL ;
    PORT
      LAYER M4 ;
        RECT  27.996 55.152 28.08 55.176 ;
    END
  END q[263]
  PIN q[264]
    DIRECTION OUTPUT ;
    USE SIGNAL ;
    PORT
      LAYER M4 ;
        RECT  27.996 55.248 28.08 55.272 ;
    END
  END q[264]
  PIN q[265]
    DIRECTION OUTPUT ;
    USE SIGNAL ;
    PORT
      LAYER M4 ;
        RECT  27.996 55.344 28.08 55.368 ;
    END
  END q[265]
  PIN q[266]
    DIRECTION OUTPUT ;
    USE SIGNAL ;
    PORT
      LAYER M4 ;
        RECT  27.996 55.44 28.08 55.464 ;
    END
  END q[266]
  PIN q[267]
    DIRECTION OUTPUT ;
    USE SIGNAL ;
    PORT
      LAYER M4 ;
        RECT  27.996 55.536 28.08 55.56 ;
    END
  END q[267]
  PIN q[268]
    DIRECTION OUTPUT ;
    USE SIGNAL ;
    PORT
      LAYER M4 ;
        RECT  27.996 55.632 28.08 55.656 ;
    END
  END q[268]
  PIN q[269]
    DIRECTION OUTPUT ;
    USE SIGNAL ;
    PORT
      LAYER M4 ;
        RECT  27.996 55.728 28.08 55.752 ;
    END
  END q[269]
  PIN q[26]
    DIRECTION OUTPUT ;
    USE SIGNAL ;
    PORT
      LAYER M4 ;
        RECT  27.996 34.704 28.08 34.728 ;
    END
  END q[26]
  PIN q[270]
    DIRECTION OUTPUT ;
    USE SIGNAL ;
    PORT
      LAYER M4 ;
        RECT  27.996 55.824 28.08 55.848 ;
    END
  END q[270]
  PIN q[271]
    DIRECTION OUTPUT ;
    USE SIGNAL ;
    PORT
      LAYER M4 ;
        RECT  27.996 55.92 28.08 55.944 ;
    END
  END q[271]
  PIN q[272]
    DIRECTION OUTPUT ;
    USE SIGNAL ;
    PORT
      LAYER M4 ;
        RECT  27.996 56.016 28.08 56.04 ;
    END
  END q[272]
  PIN q[273]
    DIRECTION OUTPUT ;
    USE SIGNAL ;
    PORT
      LAYER M4 ;
        RECT  27.996 56.112 28.08 56.136 ;
    END
  END q[273]
  PIN q[274]
    DIRECTION OUTPUT ;
    USE SIGNAL ;
    PORT
      LAYER M4 ;
        RECT  27.996 56.208 28.08 56.232 ;
    END
  END q[274]
  PIN q[275]
    DIRECTION OUTPUT ;
    USE SIGNAL ;
    PORT
      LAYER M4 ;
        RECT  27.996 56.304 28.08 56.328 ;
    END
  END q[275]
  PIN q[276]
    DIRECTION OUTPUT ;
    USE SIGNAL ;
    PORT
      LAYER M4 ;
        RECT  27.996 56.4 28.08 56.424 ;
    END
  END q[276]
  PIN q[277]
    DIRECTION OUTPUT ;
    USE SIGNAL ;
    PORT
      LAYER M4 ;
        RECT  27.996 56.496 28.08 56.52 ;
    END
  END q[277]
  PIN q[278]
    DIRECTION OUTPUT ;
    USE SIGNAL ;
    PORT
      LAYER M4 ;
        RECT  27.996 56.592 28.08 56.616 ;
    END
  END q[278]
  PIN q[279]
    DIRECTION OUTPUT ;
    USE SIGNAL ;
    PORT
      LAYER M4 ;
        RECT  27.996 56.688 28.08 56.712 ;
    END
  END q[279]
  PIN q[27]
    DIRECTION OUTPUT ;
    USE SIGNAL ;
    PORT
      LAYER M4 ;
        RECT  27.996 34.8 28.08 34.824 ;
    END
  END q[27]
  PIN q[280]
    DIRECTION OUTPUT ;
    USE SIGNAL ;
    PORT
      LAYER M4 ;
        RECT  27.996 56.784 28.08 56.808 ;
    END
  END q[280]
  PIN q[281]
    DIRECTION OUTPUT ;
    USE SIGNAL ;
    PORT
      LAYER M4 ;
        RECT  27.996 56.88 28.08 56.904 ;
    END
  END q[281]
  PIN q[282]
    DIRECTION OUTPUT ;
    USE SIGNAL ;
    PORT
      LAYER M4 ;
        RECT  27.996 56.976 28.08 57 ;
    END
  END q[282]
  PIN q[283]
    DIRECTION OUTPUT ;
    USE SIGNAL ;
    PORT
      LAYER M4 ;
        RECT  27.996 57.072 28.08 57.096 ;
    END
  END q[283]
  PIN q[284]
    DIRECTION OUTPUT ;
    USE SIGNAL ;
    PORT
      LAYER M4 ;
        RECT  27.996 57.168 28.08 57.192 ;
    END
  END q[284]
  PIN q[285]
    DIRECTION OUTPUT ;
    USE SIGNAL ;
    PORT
      LAYER M4 ;
        RECT  27.996 57.264 28.08 57.288 ;
    END
  END q[285]
  PIN q[286]
    DIRECTION OUTPUT ;
    USE SIGNAL ;
    PORT
      LAYER M4 ;
        RECT  27.996 57.36 28.08 57.384 ;
    END
  END q[286]
  PIN q[287]
    DIRECTION OUTPUT ;
    USE SIGNAL ;
    PORT
      LAYER M4 ;
        RECT  27.996 57.456 28.08 57.48 ;
    END
  END q[287]
  PIN q[288]
    DIRECTION OUTPUT ;
    USE SIGNAL ;
    PORT
      LAYER M4 ;
        RECT  27.996 48.336 28.08 48.36 ;
    END
  END q[288]
  PIN q[289]
    DIRECTION OUTPUT ;
    USE SIGNAL ;
    PORT
      LAYER M4 ;
        RECT  27.996 48.432 28.08 48.456 ;
    END
  END q[289]
  PIN q[28]
    DIRECTION OUTPUT ;
    USE SIGNAL ;
    PORT
      LAYER M4 ;
        RECT  27.996 34.896 28.08 34.92 ;
    END
  END q[28]
  PIN q[290]
    DIRECTION OUTPUT ;
    USE SIGNAL ;
    PORT
      LAYER M4 ;
        RECT  27.996 48.528 28.08 48.552 ;
    END
  END q[290]
  PIN q[291]
    DIRECTION OUTPUT ;
    USE SIGNAL ;
    PORT
      LAYER M4 ;
        RECT  27.996 48.624 28.08 48.648 ;
    END
  END q[291]
  PIN q[292]
    DIRECTION OUTPUT ;
    USE SIGNAL ;
    PORT
      LAYER M4 ;
        RECT  27.996 48.72 28.08 48.744 ;
    END
  END q[292]
  PIN q[293]
    DIRECTION OUTPUT ;
    USE SIGNAL ;
    PORT
      LAYER M4 ;
        RECT  27.996 48.816 28.08 48.84 ;
    END
  END q[293]
  PIN q[294]
    DIRECTION OUTPUT ;
    USE SIGNAL ;
    PORT
      LAYER M4 ;
        RECT  27.996 48.912 28.08 48.936 ;
    END
  END q[294]
  PIN q[295]
    DIRECTION OUTPUT ;
    USE SIGNAL ;
    PORT
      LAYER M4 ;
        RECT  27.996 49.008 28.08 49.032 ;
    END
  END q[295]
  PIN q[296]
    DIRECTION OUTPUT ;
    USE SIGNAL ;
    PORT
      LAYER M4 ;
        RECT  27.996 49.104 28.08 49.128 ;
    END
  END q[296]
  PIN q[297]
    DIRECTION OUTPUT ;
    USE SIGNAL ;
    PORT
      LAYER M4 ;
        RECT  27.996 49.2 28.08 49.224 ;
    END
  END q[297]
  PIN q[298]
    DIRECTION OUTPUT ;
    USE SIGNAL ;
    PORT
      LAYER M4 ;
        RECT  27.996 49.296 28.08 49.32 ;
    END
  END q[298]
  PIN q[299]
    DIRECTION OUTPUT ;
    USE SIGNAL ;
    PORT
      LAYER M4 ;
        RECT  27.996 49.392 28.08 49.416 ;
    END
  END q[299]
  PIN q[29]
    DIRECTION OUTPUT ;
    USE SIGNAL ;
    PORT
      LAYER M4 ;
        RECT  27.996 34.992 28.08 35.016 ;
    END
  END q[29]
  PIN q[2]
    DIRECTION OUTPUT ;
    USE SIGNAL ;
    PORT
      LAYER M4 ;
        RECT  27.996 32.4 28.08 32.424 ;
    END
  END q[2]
  PIN q[300]
    DIRECTION OUTPUT ;
    USE SIGNAL ;
    PORT
      LAYER M4 ;
        RECT  27.996 49.488 28.08 49.512 ;
    END
  END q[300]
  PIN q[301]
    DIRECTION OUTPUT ;
    USE SIGNAL ;
    PORT
      LAYER M4 ;
        RECT  27.996 49.584 28.08 49.608 ;
    END
  END q[301]
  PIN q[302]
    DIRECTION OUTPUT ;
    USE SIGNAL ;
    PORT
      LAYER M4 ;
        RECT  27.996 49.68 28.08 49.704 ;
    END
  END q[302]
  PIN q[303]
    DIRECTION OUTPUT ;
    USE SIGNAL ;
    PORT
      LAYER M4 ;
        RECT  27.996 49.776 28.08 49.8 ;
    END
  END q[303]
  PIN q[304]
    DIRECTION OUTPUT ;
    USE SIGNAL ;
    PORT
      LAYER M4 ;
        RECT  27.996 49.872 28.08 49.896 ;
    END
  END q[304]
  PIN q[305]
    DIRECTION OUTPUT ;
    USE SIGNAL ;
    PORT
      LAYER M4 ;
        RECT  27.996 49.968 28.08 49.992 ;
    END
  END q[305]
  PIN q[306]
    DIRECTION OUTPUT ;
    USE SIGNAL ;
    PORT
      LAYER M4 ;
        RECT  27.996 50.064 28.08 50.088 ;
    END
  END q[306]
  PIN q[307]
    DIRECTION OUTPUT ;
    USE SIGNAL ;
    PORT
      LAYER M4 ;
        RECT  27.996 50.16 28.08 50.184 ;
    END
  END q[307]
  PIN q[308]
    DIRECTION OUTPUT ;
    USE SIGNAL ;
    PORT
      LAYER M4 ;
        RECT  27.996 50.256 28.08 50.28 ;
    END
  END q[308]
  PIN q[309]
    DIRECTION OUTPUT ;
    USE SIGNAL ;
    PORT
      LAYER M4 ;
        RECT  27.996 50.352 28.08 50.376 ;
    END
  END q[309]
  PIN q[30]
    DIRECTION OUTPUT ;
    USE SIGNAL ;
    PORT
      LAYER M4 ;
        RECT  27.996 35.088 28.08 35.112 ;
    END
  END q[30]
  PIN q[310]
    DIRECTION OUTPUT ;
    USE SIGNAL ;
    PORT
      LAYER M4 ;
        RECT  27.996 50.448 28.08 50.472 ;
    END
  END q[310]
  PIN q[311]
    DIRECTION OUTPUT ;
    USE SIGNAL ;
    PORT
      LAYER M4 ;
        RECT  27.996 50.544 28.08 50.568 ;
    END
  END q[311]
  PIN q[312]
    DIRECTION OUTPUT ;
    USE SIGNAL ;
    PORT
      LAYER M4 ;
        RECT  27.996 50.64 28.08 50.664 ;
    END
  END q[312]
  PIN q[313]
    DIRECTION OUTPUT ;
    USE SIGNAL ;
    PORT
      LAYER M4 ;
        RECT  27.996 50.736 28.08 50.76 ;
    END
  END q[313]
  PIN q[314]
    DIRECTION OUTPUT ;
    USE SIGNAL ;
    PORT
      LAYER M4 ;
        RECT  27.996 50.832 28.08 50.856 ;
    END
  END q[314]
  PIN q[315]
    DIRECTION OUTPUT ;
    USE SIGNAL ;
    PORT
      LAYER M4 ;
        RECT  27.996 50.928 28.08 50.952 ;
    END
  END q[315]
  PIN q[316]
    DIRECTION OUTPUT ;
    USE SIGNAL ;
    PORT
      LAYER M4 ;
        RECT  27.996 51.024 28.08 51.048 ;
    END
  END q[316]
  PIN q[317]
    DIRECTION OUTPUT ;
    USE SIGNAL ;
    PORT
      LAYER M4 ;
        RECT  27.996 51.12 28.08 51.144 ;
    END
  END q[317]
  PIN q[318]
    DIRECTION OUTPUT ;
    USE SIGNAL ;
    PORT
      LAYER M4 ;
        RECT  27.996 51.216 28.08 51.24 ;
    END
  END q[318]
  PIN q[319]
    DIRECTION OUTPUT ;
    USE SIGNAL ;
    PORT
      LAYER M4 ;
        RECT  27.996 51.312 28.08 51.336 ;
    END
  END q[319]
  PIN q[31]
    DIRECTION OUTPUT ;
    USE SIGNAL ;
    PORT
      LAYER M4 ;
        RECT  27.996 35.184 28.08 35.208 ;
    END
  END q[31]
  PIN q[320]
    DIRECTION OUTPUT ;
    USE SIGNAL ;
    PORT
      LAYER M4 ;
        RECT  27.996 51.408 28.08 51.432 ;
    END
  END q[320]
  PIN q[321]
    DIRECTION OUTPUT ;
    USE SIGNAL ;
    PORT
      LAYER M4 ;
        RECT  27.996 51.504 28.08 51.528 ;
    END
  END q[321]
  PIN q[322]
    DIRECTION OUTPUT ;
    USE SIGNAL ;
    PORT
      LAYER M4 ;
        RECT  27.996 51.6 28.08 51.624 ;
    END
  END q[322]
  PIN q[323]
    DIRECTION OUTPUT ;
    USE SIGNAL ;
    PORT
      LAYER M4 ;
        RECT  27.996 51.696 28.08 51.72 ;
    END
  END q[323]
  PIN q[324]
    DIRECTION OUTPUT ;
    USE SIGNAL ;
    PORT
      LAYER M4 ;
        RECT  27.996 51.792 28.08 51.816 ;
    END
  END q[324]
  PIN q[325]
    DIRECTION OUTPUT ;
    USE SIGNAL ;
    PORT
      LAYER M4 ;
        RECT  27.996 51.888 28.08 51.912 ;
    END
  END q[325]
  PIN q[326]
    DIRECTION OUTPUT ;
    USE SIGNAL ;
    PORT
      LAYER M4 ;
        RECT  27.996 51.984 28.08 52.008 ;
    END
  END q[326]
  PIN q[327]
    DIRECTION OUTPUT ;
    USE SIGNAL ;
    PORT
      LAYER M4 ;
        RECT  27.996 52.08 28.08 52.104 ;
    END
  END q[327]
  PIN q[328]
    DIRECTION OUTPUT ;
    USE SIGNAL ;
    PORT
      LAYER M4 ;
        RECT  27.996 52.176 28.08 52.2 ;
    END
  END q[328]
  PIN q[329]
    DIRECTION OUTPUT ;
    USE SIGNAL ;
    PORT
      LAYER M4 ;
        RECT  27.996 52.272 28.08 52.296 ;
    END
  END q[329]
  PIN q[32]
    DIRECTION OUTPUT ;
    USE SIGNAL ;
    PORT
      LAYER M4 ;
        RECT  27.996 26.064 28.08 26.088 ;
    END
  END q[32]
  PIN q[330]
    DIRECTION OUTPUT ;
    USE SIGNAL ;
    PORT
      LAYER M4 ;
        RECT  27.996 52.368 28.08 52.392 ;
    END
  END q[330]
  PIN q[331]
    DIRECTION OUTPUT ;
    USE SIGNAL ;
    PORT
      LAYER M4 ;
        RECT  27.996 52.464 28.08 52.488 ;
    END
  END q[331]
  PIN q[332]
    DIRECTION OUTPUT ;
    USE SIGNAL ;
    PORT
      LAYER M4 ;
        RECT  27.996 52.56 28.08 52.584 ;
    END
  END q[332]
  PIN q[333]
    DIRECTION OUTPUT ;
    USE SIGNAL ;
    PORT
      LAYER M4 ;
        RECT  27.996 52.656 28.08 52.68 ;
    END
  END q[333]
  PIN q[334]
    DIRECTION OUTPUT ;
    USE SIGNAL ;
    PORT
      LAYER M4 ;
        RECT  27.996 52.752 28.08 52.776 ;
    END
  END q[334]
  PIN q[335]
    DIRECTION OUTPUT ;
    USE SIGNAL ;
    PORT
      LAYER M4 ;
        RECT  27.996 52.848 28.08 52.872 ;
    END
  END q[335]
  PIN q[336]
    DIRECTION OUTPUT ;
    USE SIGNAL ;
    PORT
      LAYER M4 ;
        RECT  27.996 52.944 28.08 52.968 ;
    END
  END q[336]
  PIN q[337]
    DIRECTION OUTPUT ;
    USE SIGNAL ;
    PORT
      LAYER M4 ;
        RECT  27.996 53.04 28.08 53.064 ;
    END
  END q[337]
  PIN q[338]
    DIRECTION OUTPUT ;
    USE SIGNAL ;
    PORT
      LAYER M4 ;
        RECT  27.996 53.136 28.08 53.16 ;
    END
  END q[338]
  PIN q[339]
    DIRECTION OUTPUT ;
    USE SIGNAL ;
    PORT
      LAYER M4 ;
        RECT  27.996 53.232 28.08 53.256 ;
    END
  END q[339]
  PIN q[33]
    DIRECTION OUTPUT ;
    USE SIGNAL ;
    PORT
      LAYER M4 ;
        RECT  27.996 26.16 28.08 26.184 ;
    END
  END q[33]
  PIN q[340]
    DIRECTION OUTPUT ;
    USE SIGNAL ;
    PORT
      LAYER M4 ;
        RECT  27.996 53.328 28.08 53.352 ;
    END
  END q[340]
  PIN q[341]
    DIRECTION OUTPUT ;
    USE SIGNAL ;
    PORT
      LAYER M4 ;
        RECT  27.996 53.424 28.08 53.448 ;
    END
  END q[341]
  PIN q[342]
    DIRECTION OUTPUT ;
    USE SIGNAL ;
    PORT
      LAYER M4 ;
        RECT  27.996 53.52 28.08 53.544 ;
    END
  END q[342]
  PIN q[343]
    DIRECTION OUTPUT ;
    USE SIGNAL ;
    PORT
      LAYER M4 ;
        RECT  27.996 53.616 28.08 53.64 ;
    END
  END q[343]
  PIN q[344]
    DIRECTION OUTPUT ;
    USE SIGNAL ;
    PORT
      LAYER M4 ;
        RECT  27.996 53.712 28.08 53.736 ;
    END
  END q[344]
  PIN q[345]
    DIRECTION OUTPUT ;
    USE SIGNAL ;
    PORT
      LAYER M4 ;
        RECT  27.996 53.808 28.08 53.832 ;
    END
  END q[345]
  PIN q[346]
    DIRECTION OUTPUT ;
    USE SIGNAL ;
    PORT
      LAYER M4 ;
        RECT  27.996 53.904 28.08 53.928 ;
    END
  END q[346]
  PIN q[347]
    DIRECTION OUTPUT ;
    USE SIGNAL ;
    PORT
      LAYER M4 ;
        RECT  27.996 54 28.08 54.024 ;
    END
  END q[347]
  PIN q[348]
    DIRECTION OUTPUT ;
    USE SIGNAL ;
    PORT
      LAYER M4 ;
        RECT  27.996 54.096 28.08 54.12 ;
    END
  END q[348]
  PIN q[349]
    DIRECTION OUTPUT ;
    USE SIGNAL ;
    PORT
      LAYER M4 ;
        RECT  27.996 54.192 28.08 54.216 ;
    END
  END q[349]
  PIN q[34]
    DIRECTION OUTPUT ;
    USE SIGNAL ;
    PORT
      LAYER M4 ;
        RECT  27.996 26.256 28.08 26.28 ;
    END
  END q[34]
  PIN q[350]
    DIRECTION OUTPUT ;
    USE SIGNAL ;
    PORT
      LAYER M4 ;
        RECT  27.996 54.288 28.08 54.312 ;
    END
  END q[350]
  PIN q[351]
    DIRECTION OUTPUT ;
    USE SIGNAL ;
    PORT
      LAYER M4 ;
        RECT  27.996 54.384 28.08 54.408 ;
    END
  END q[351]
  PIN q[352]
    DIRECTION OUTPUT ;
    USE SIGNAL ;
    PORT
      LAYER M4 ;
        RECT  27.996 42.192 28.08 42.216 ;
    END
  END q[352]
  PIN q[353]
    DIRECTION OUTPUT ;
    USE SIGNAL ;
    PORT
      LAYER M4 ;
        RECT  27.996 42.288 28.08 42.312 ;
    END
  END q[353]
  PIN q[354]
    DIRECTION OUTPUT ;
    USE SIGNAL ;
    PORT
      LAYER M4 ;
        RECT  27.996 42.384 28.08 42.408 ;
    END
  END q[354]
  PIN q[355]
    DIRECTION OUTPUT ;
    USE SIGNAL ;
    PORT
      LAYER M4 ;
        RECT  27.996 42.48 28.08 42.504 ;
    END
  END q[355]
  PIN q[356]
    DIRECTION OUTPUT ;
    USE SIGNAL ;
    PORT
      LAYER M4 ;
        RECT  27.996 42.576 28.08 42.6 ;
    END
  END q[356]
  PIN q[357]
    DIRECTION OUTPUT ;
    USE SIGNAL ;
    PORT
      LAYER M4 ;
        RECT  27.996 42.672 28.08 42.696 ;
    END
  END q[357]
  PIN q[358]
    DIRECTION OUTPUT ;
    USE SIGNAL ;
    PORT
      LAYER M4 ;
        RECT  27.996 42.768 28.08 42.792 ;
    END
  END q[358]
  PIN q[359]
    DIRECTION OUTPUT ;
    USE SIGNAL ;
    PORT
      LAYER M4 ;
        RECT  27.996 42.864 28.08 42.888 ;
    END
  END q[359]
  PIN q[35]
    DIRECTION OUTPUT ;
    USE SIGNAL ;
    PORT
      LAYER M4 ;
        RECT  27.996 26.352 28.08 26.376 ;
    END
  END q[35]
  PIN q[360]
    DIRECTION OUTPUT ;
    USE SIGNAL ;
    PORT
      LAYER M4 ;
        RECT  27.996 42.96 28.08 42.984 ;
    END
  END q[360]
  PIN q[361]
    DIRECTION OUTPUT ;
    USE SIGNAL ;
    PORT
      LAYER M4 ;
        RECT  27.996 43.056 28.08 43.08 ;
    END
  END q[361]
  PIN q[362]
    DIRECTION OUTPUT ;
    USE SIGNAL ;
    PORT
      LAYER M4 ;
        RECT  27.996 43.152 28.08 43.176 ;
    END
  END q[362]
  PIN q[363]
    DIRECTION OUTPUT ;
    USE SIGNAL ;
    PORT
      LAYER M4 ;
        RECT  27.996 43.248 28.08 43.272 ;
    END
  END q[363]
  PIN q[364]
    DIRECTION OUTPUT ;
    USE SIGNAL ;
    PORT
      LAYER M4 ;
        RECT  27.996 43.344 28.08 43.368 ;
    END
  END q[364]
  PIN q[365]
    DIRECTION OUTPUT ;
    USE SIGNAL ;
    PORT
      LAYER M4 ;
        RECT  27.996 43.44 28.08 43.464 ;
    END
  END q[365]
  PIN q[366]
    DIRECTION OUTPUT ;
    USE SIGNAL ;
    PORT
      LAYER M4 ;
        RECT  27.996 43.536 28.08 43.56 ;
    END
  END q[366]
  PIN q[367]
    DIRECTION OUTPUT ;
    USE SIGNAL ;
    PORT
      LAYER M4 ;
        RECT  27.996 43.632 28.08 43.656 ;
    END
  END q[367]
  PIN q[368]
    DIRECTION OUTPUT ;
    USE SIGNAL ;
    PORT
      LAYER M4 ;
        RECT  27.996 43.728 28.08 43.752 ;
    END
  END q[368]
  PIN q[369]
    DIRECTION OUTPUT ;
    USE SIGNAL ;
    PORT
      LAYER M4 ;
        RECT  27.996 43.824 28.08 43.848 ;
    END
  END q[369]
  PIN q[36]
    DIRECTION OUTPUT ;
    USE SIGNAL ;
    PORT
      LAYER M4 ;
        RECT  27.996 26.448 28.08 26.472 ;
    END
  END q[36]
  PIN q[370]
    DIRECTION OUTPUT ;
    USE SIGNAL ;
    PORT
      LAYER M4 ;
        RECT  27.996 43.92 28.08 43.944 ;
    END
  END q[370]
  PIN q[371]
    DIRECTION OUTPUT ;
    USE SIGNAL ;
    PORT
      LAYER M4 ;
        RECT  27.996 44.016 28.08 44.04 ;
    END
  END q[371]
  PIN q[372]
    DIRECTION OUTPUT ;
    USE SIGNAL ;
    PORT
      LAYER M4 ;
        RECT  27.996 44.112 28.08 44.136 ;
    END
  END q[372]
  PIN q[373]
    DIRECTION OUTPUT ;
    USE SIGNAL ;
    PORT
      LAYER M4 ;
        RECT  27.996 44.208 28.08 44.232 ;
    END
  END q[373]
  PIN q[374]
    DIRECTION OUTPUT ;
    USE SIGNAL ;
    PORT
      LAYER M4 ;
        RECT  27.996 44.304 28.08 44.328 ;
    END
  END q[374]
  PIN q[375]
    DIRECTION OUTPUT ;
    USE SIGNAL ;
    PORT
      LAYER M4 ;
        RECT  27.996 44.4 28.08 44.424 ;
    END
  END q[375]
  PIN q[376]
    DIRECTION OUTPUT ;
    USE SIGNAL ;
    PORT
      LAYER M4 ;
        RECT  27.996 44.496 28.08 44.52 ;
    END
  END q[376]
  PIN q[377]
    DIRECTION OUTPUT ;
    USE SIGNAL ;
    PORT
      LAYER M4 ;
        RECT  27.996 44.592 28.08 44.616 ;
    END
  END q[377]
  PIN q[378]
    DIRECTION OUTPUT ;
    USE SIGNAL ;
    PORT
      LAYER M4 ;
        RECT  27.996 44.688 28.08 44.712 ;
    END
  END q[378]
  PIN q[379]
    DIRECTION OUTPUT ;
    USE SIGNAL ;
    PORT
      LAYER M4 ;
        RECT  27.996 44.784 28.08 44.808 ;
    END
  END q[379]
  PIN q[37]
    DIRECTION OUTPUT ;
    USE SIGNAL ;
    PORT
      LAYER M4 ;
        RECT  27.996 26.544 28.08 26.568 ;
    END
  END q[37]
  PIN q[380]
    DIRECTION OUTPUT ;
    USE SIGNAL ;
    PORT
      LAYER M4 ;
        RECT  27.996 44.88 28.08 44.904 ;
    END
  END q[380]
  PIN q[381]
    DIRECTION OUTPUT ;
    USE SIGNAL ;
    PORT
      LAYER M4 ;
        RECT  27.996 44.976 28.08 45 ;
    END
  END q[381]
  PIN q[382]
    DIRECTION OUTPUT ;
    USE SIGNAL ;
    PORT
      LAYER M4 ;
        RECT  27.996 45.072 28.08 45.096 ;
    END
  END q[382]
  PIN q[383]
    DIRECTION OUTPUT ;
    USE SIGNAL ;
    PORT
      LAYER M4 ;
        RECT  27.996 45.168 28.08 45.192 ;
    END
  END q[383]
  PIN q[384]
    DIRECTION OUTPUT ;
    USE SIGNAL ;
    PORT
      LAYER M4 ;
        RECT  27.996 9.936 28.08 9.96 ;
    END
  END q[384]
  PIN q[385]
    DIRECTION OUTPUT ;
    USE SIGNAL ;
    PORT
      LAYER M4 ;
        RECT  27.996 10.032 28.08 10.056 ;
    END
  END q[385]
  PIN q[386]
    DIRECTION OUTPUT ;
    USE SIGNAL ;
    PORT
      LAYER M4 ;
        RECT  27.996 10.128 28.08 10.152 ;
    END
  END q[386]
  PIN q[387]
    DIRECTION OUTPUT ;
    USE SIGNAL ;
    PORT
      LAYER M4 ;
        RECT  27.996 10.224 28.08 10.248 ;
    END
  END q[387]
  PIN q[388]
    DIRECTION OUTPUT ;
    USE SIGNAL ;
    PORT
      LAYER M4 ;
        RECT  27.996 10.32 28.08 10.344 ;
    END
  END q[388]
  PIN q[389]
    DIRECTION OUTPUT ;
    USE SIGNAL ;
    PORT
      LAYER M4 ;
        RECT  27.996 10.416 28.08 10.44 ;
    END
  END q[389]
  PIN q[38]
    DIRECTION OUTPUT ;
    USE SIGNAL ;
    PORT
      LAYER M4 ;
        RECT  27.996 26.64 28.08 26.664 ;
    END
  END q[38]
  PIN q[390]
    DIRECTION OUTPUT ;
    USE SIGNAL ;
    PORT
      LAYER M4 ;
        RECT  27.996 10.512 28.08 10.536 ;
    END
  END q[390]
  PIN q[391]
    DIRECTION OUTPUT ;
    USE SIGNAL ;
    PORT
      LAYER M4 ;
        RECT  27.996 10.608 28.08 10.632 ;
    END
  END q[391]
  PIN q[392]
    DIRECTION OUTPUT ;
    USE SIGNAL ;
    PORT
      LAYER M4 ;
        RECT  27.996 10.704 28.08 10.728 ;
    END
  END q[392]
  PIN q[393]
    DIRECTION OUTPUT ;
    USE SIGNAL ;
    PORT
      LAYER M4 ;
        RECT  27.996 10.8 28.08 10.824 ;
    END
  END q[393]
  PIN q[394]
    DIRECTION OUTPUT ;
    USE SIGNAL ;
    PORT
      LAYER M4 ;
        RECT  27.996 10.896 28.08 10.92 ;
    END
  END q[394]
  PIN q[395]
    DIRECTION OUTPUT ;
    USE SIGNAL ;
    PORT
      LAYER M4 ;
        RECT  27.996 10.992 28.08 11.016 ;
    END
  END q[395]
  PIN q[396]
    DIRECTION OUTPUT ;
    USE SIGNAL ;
    PORT
      LAYER M4 ;
        RECT  27.996 11.088 28.08 11.112 ;
    END
  END q[396]
  PIN q[397]
    DIRECTION OUTPUT ;
    USE SIGNAL ;
    PORT
      LAYER M4 ;
        RECT  27.996 11.184 28.08 11.208 ;
    END
  END q[397]
  PIN q[398]
    DIRECTION OUTPUT ;
    USE SIGNAL ;
    PORT
      LAYER M4 ;
        RECT  27.996 11.28 28.08 11.304 ;
    END
  END q[398]
  PIN q[399]
    DIRECTION OUTPUT ;
    USE SIGNAL ;
    PORT
      LAYER M4 ;
        RECT  27.996 11.376 28.08 11.4 ;
    END
  END q[399]
  PIN q[39]
    DIRECTION OUTPUT ;
    USE SIGNAL ;
    PORT
      LAYER M4 ;
        RECT  27.996 26.736 28.08 26.76 ;
    END
  END q[39]
  PIN q[3]
    DIRECTION OUTPUT ;
    USE SIGNAL ;
    PORT
      LAYER M4 ;
        RECT  27.996 32.496 28.08 32.52 ;
    END
  END q[3]
  PIN q[400]
    DIRECTION OUTPUT ;
    USE SIGNAL ;
    PORT
      LAYER M4 ;
        RECT  27.996 11.472 28.08 11.496 ;
    END
  END q[400]
  PIN q[401]
    DIRECTION OUTPUT ;
    USE SIGNAL ;
    PORT
      LAYER M4 ;
        RECT  27.996 11.568 28.08 11.592 ;
    END
  END q[401]
  PIN q[402]
    DIRECTION OUTPUT ;
    USE SIGNAL ;
    PORT
      LAYER M4 ;
        RECT  27.996 11.664 28.08 11.688 ;
    END
  END q[402]
  PIN q[403]
    DIRECTION OUTPUT ;
    USE SIGNAL ;
    PORT
      LAYER M4 ;
        RECT  27.996 11.76 28.08 11.784 ;
    END
  END q[403]
  PIN q[404]
    DIRECTION OUTPUT ;
    USE SIGNAL ;
    PORT
      LAYER M4 ;
        RECT  27.996 11.856 28.08 11.88 ;
    END
  END q[404]
  PIN q[405]
    DIRECTION OUTPUT ;
    USE SIGNAL ;
    PORT
      LAYER M4 ;
        RECT  27.996 11.952 28.08 11.976 ;
    END
  END q[405]
  PIN q[406]
    DIRECTION OUTPUT ;
    USE SIGNAL ;
    PORT
      LAYER M4 ;
        RECT  27.996 12.048 28.08 12.072 ;
    END
  END q[406]
  PIN q[407]
    DIRECTION OUTPUT ;
    USE SIGNAL ;
    PORT
      LAYER M4 ;
        RECT  27.996 12.144 28.08 12.168 ;
    END
  END q[407]
  PIN q[408]
    DIRECTION OUTPUT ;
    USE SIGNAL ;
    PORT
      LAYER M4 ;
        RECT  27.996 12.24 28.08 12.264 ;
    END
  END q[408]
  PIN q[409]
    DIRECTION OUTPUT ;
    USE SIGNAL ;
    PORT
      LAYER M4 ;
        RECT  27.996 12.336 28.08 12.36 ;
    END
  END q[409]
  PIN q[40]
    DIRECTION OUTPUT ;
    USE SIGNAL ;
    PORT
      LAYER M4 ;
        RECT  27.996 26.832 28.08 26.856 ;
    END
  END q[40]
  PIN q[410]
    DIRECTION OUTPUT ;
    USE SIGNAL ;
    PORT
      LAYER M4 ;
        RECT  27.996 12.432 28.08 12.456 ;
    END
  END q[410]
  PIN q[411]
    DIRECTION OUTPUT ;
    USE SIGNAL ;
    PORT
      LAYER M4 ;
        RECT  27.996 12.528 28.08 12.552 ;
    END
  END q[411]
  PIN q[412]
    DIRECTION OUTPUT ;
    USE SIGNAL ;
    PORT
      LAYER M4 ;
        RECT  27.996 12.624 28.08 12.648 ;
    END
  END q[412]
  PIN q[413]
    DIRECTION OUTPUT ;
    USE SIGNAL ;
    PORT
      LAYER M4 ;
        RECT  27.996 12.72 28.08 12.744 ;
    END
  END q[413]
  PIN q[414]
    DIRECTION OUTPUT ;
    USE SIGNAL ;
    PORT
      LAYER M4 ;
        RECT  27.996 12.816 28.08 12.84 ;
    END
  END q[414]
  PIN q[415]
    DIRECTION OUTPUT ;
    USE SIGNAL ;
    PORT
      LAYER M4 ;
        RECT  27.996 12.912 28.08 12.936 ;
    END
  END q[415]
  PIN q[416]
    DIRECTION OUTPUT ;
    USE SIGNAL ;
    PORT
      LAYER M4 ;
        RECT  27.996 13.008 28.08 13.032 ;
    END
  END q[416]
  PIN q[417]
    DIRECTION OUTPUT ;
    USE SIGNAL ;
    PORT
      LAYER M4 ;
        RECT  27.996 13.104 28.08 13.128 ;
    END
  END q[417]
  PIN q[418]
    DIRECTION OUTPUT ;
    USE SIGNAL ;
    PORT
      LAYER M4 ;
        RECT  27.996 13.2 28.08 13.224 ;
    END
  END q[418]
  PIN q[419]
    DIRECTION OUTPUT ;
    USE SIGNAL ;
    PORT
      LAYER M4 ;
        RECT  27.996 13.296 28.08 13.32 ;
    END
  END q[419]
  PIN q[41]
    DIRECTION OUTPUT ;
    USE SIGNAL ;
    PORT
      LAYER M4 ;
        RECT  27.996 26.928 28.08 26.952 ;
    END
  END q[41]
  PIN q[420]
    DIRECTION OUTPUT ;
    USE SIGNAL ;
    PORT
      LAYER M4 ;
        RECT  27.996 13.392 28.08 13.416 ;
    END
  END q[420]
  PIN q[421]
    DIRECTION OUTPUT ;
    USE SIGNAL ;
    PORT
      LAYER M4 ;
        RECT  27.996 13.488 28.08 13.512 ;
    END
  END q[421]
  PIN q[422]
    DIRECTION OUTPUT ;
    USE SIGNAL ;
    PORT
      LAYER M4 ;
        RECT  27.996 13.584 28.08 13.608 ;
    END
  END q[422]
  PIN q[423]
    DIRECTION OUTPUT ;
    USE SIGNAL ;
    PORT
      LAYER M4 ;
        RECT  27.996 13.68 28.08 13.704 ;
    END
  END q[423]
  PIN q[424]
    DIRECTION OUTPUT ;
    USE SIGNAL ;
    PORT
      LAYER M4 ;
        RECT  27.996 13.776 28.08 13.8 ;
    END
  END q[424]
  PIN q[425]
    DIRECTION OUTPUT ;
    USE SIGNAL ;
    PORT
      LAYER M4 ;
        RECT  27.996 13.872 28.08 13.896 ;
    END
  END q[425]
  PIN q[426]
    DIRECTION OUTPUT ;
    USE SIGNAL ;
    PORT
      LAYER M4 ;
        RECT  27.996 13.968 28.08 13.992 ;
    END
  END q[426]
  PIN q[427]
    DIRECTION OUTPUT ;
    USE SIGNAL ;
    PORT
      LAYER M4 ;
        RECT  27.996 14.064 28.08 14.088 ;
    END
  END q[427]
  PIN q[428]
    DIRECTION OUTPUT ;
    USE SIGNAL ;
    PORT
      LAYER M4 ;
        RECT  27.996 14.16 28.08 14.184 ;
    END
  END q[428]
  PIN q[429]
    DIRECTION OUTPUT ;
    USE SIGNAL ;
    PORT
      LAYER M4 ;
        RECT  27.996 14.256 28.08 14.28 ;
    END
  END q[429]
  PIN q[42]
    DIRECTION OUTPUT ;
    USE SIGNAL ;
    PORT
      LAYER M4 ;
        RECT  27.996 27.024 28.08 27.048 ;
    END
  END q[42]
  PIN q[430]
    DIRECTION OUTPUT ;
    USE SIGNAL ;
    PORT
      LAYER M4 ;
        RECT  27.996 14.352 28.08 14.376 ;
    END
  END q[430]
  PIN q[431]
    DIRECTION OUTPUT ;
    USE SIGNAL ;
    PORT
      LAYER M4 ;
        RECT  27.996 14.448 28.08 14.472 ;
    END
  END q[431]
  PIN q[432]
    DIRECTION OUTPUT ;
    USE SIGNAL ;
    PORT
      LAYER M4 ;
        RECT  27.996 14.544 28.08 14.568 ;
    END
  END q[432]
  PIN q[433]
    DIRECTION OUTPUT ;
    USE SIGNAL ;
    PORT
      LAYER M4 ;
        RECT  27.996 14.64 28.08 14.664 ;
    END
  END q[433]
  PIN q[434]
    DIRECTION OUTPUT ;
    USE SIGNAL ;
    PORT
      LAYER M4 ;
        RECT  27.996 14.736 28.08 14.76 ;
    END
  END q[434]
  PIN q[435]
    DIRECTION OUTPUT ;
    USE SIGNAL ;
    PORT
      LAYER M4 ;
        RECT  27.996 14.832 28.08 14.856 ;
    END
  END q[435]
  PIN q[436]
    DIRECTION OUTPUT ;
    USE SIGNAL ;
    PORT
      LAYER M4 ;
        RECT  27.996 14.928 28.08 14.952 ;
    END
  END q[436]
  PIN q[437]
    DIRECTION OUTPUT ;
    USE SIGNAL ;
    PORT
      LAYER M4 ;
        RECT  27.996 15.024 28.08 15.048 ;
    END
  END q[437]
  PIN q[438]
    DIRECTION OUTPUT ;
    USE SIGNAL ;
    PORT
      LAYER M4 ;
        RECT  27.996 15.12 28.08 15.144 ;
    END
  END q[438]
  PIN q[439]
    DIRECTION OUTPUT ;
    USE SIGNAL ;
    PORT
      LAYER M4 ;
        RECT  27.996 15.216 28.08 15.24 ;
    END
  END q[439]
  PIN q[43]
    DIRECTION OUTPUT ;
    USE SIGNAL ;
    PORT
      LAYER M4 ;
        RECT  27.996 27.12 28.08 27.144 ;
    END
  END q[43]
  PIN q[440]
    DIRECTION OUTPUT ;
    USE SIGNAL ;
    PORT
      LAYER M4 ;
        RECT  27.996 15.312 28.08 15.336 ;
    END
  END q[440]
  PIN q[441]
    DIRECTION OUTPUT ;
    USE SIGNAL ;
    PORT
      LAYER M4 ;
        RECT  27.996 15.408 28.08 15.432 ;
    END
  END q[441]
  PIN q[442]
    DIRECTION OUTPUT ;
    USE SIGNAL ;
    PORT
      LAYER M4 ;
        RECT  27.996 15.504 28.08 15.528 ;
    END
  END q[442]
  PIN q[443]
    DIRECTION OUTPUT ;
    USE SIGNAL ;
    PORT
      LAYER M4 ;
        RECT  27.996 15.6 28.08 15.624 ;
    END
  END q[443]
  PIN q[444]
    DIRECTION OUTPUT ;
    USE SIGNAL ;
    PORT
      LAYER M4 ;
        RECT  27.996 15.696 28.08 15.72 ;
    END
  END q[444]
  PIN q[445]
    DIRECTION OUTPUT ;
    USE SIGNAL ;
    PORT
      LAYER M4 ;
        RECT  27.996 15.792 28.08 15.816 ;
    END
  END q[445]
  PIN q[446]
    DIRECTION OUTPUT ;
    USE SIGNAL ;
    PORT
      LAYER M4 ;
        RECT  27.996 15.888 28.08 15.912 ;
    END
  END q[446]
  PIN q[447]
    DIRECTION OUTPUT ;
    USE SIGNAL ;
    PORT
      LAYER M4 ;
        RECT  27.996 15.984 28.08 16.008 ;
    END
  END q[447]
  PIN q[448]
    DIRECTION OUTPUT ;
    USE SIGNAL ;
    PORT
      LAYER M4 ;
        RECT  27.996 16.08 28.08 16.104 ;
    END
  END q[448]
  PIN q[449]
    DIRECTION OUTPUT ;
    USE SIGNAL ;
    PORT
      LAYER M4 ;
        RECT  27.996 16.176 28.08 16.2 ;
    END
  END q[449]
  PIN q[44]
    DIRECTION OUTPUT ;
    USE SIGNAL ;
    PORT
      LAYER M4 ;
        RECT  27.996 27.216 28.08 27.24 ;
    END
  END q[44]
  PIN q[450]
    DIRECTION OUTPUT ;
    USE SIGNAL ;
    PORT
      LAYER M4 ;
        RECT  27.996 16.272 28.08 16.296 ;
    END
  END q[450]
  PIN q[451]
    DIRECTION OUTPUT ;
    USE SIGNAL ;
    PORT
      LAYER M4 ;
        RECT  27.996 16.368 28.08 16.392 ;
    END
  END q[451]
  PIN q[452]
    DIRECTION OUTPUT ;
    USE SIGNAL ;
    PORT
      LAYER M4 ;
        RECT  27.996 16.464 28.08 16.488 ;
    END
  END q[452]
  PIN q[453]
    DIRECTION OUTPUT ;
    USE SIGNAL ;
    PORT
      LAYER M4 ;
        RECT  27.996 16.56 28.08 16.584 ;
    END
  END q[453]
  PIN q[454]
    DIRECTION OUTPUT ;
    USE SIGNAL ;
    PORT
      LAYER M4 ;
        RECT  27.996 16.656 28.08 16.68 ;
    END
  END q[454]
  PIN q[455]
    DIRECTION OUTPUT ;
    USE SIGNAL ;
    PORT
      LAYER M4 ;
        RECT  27.996 16.752 28.08 16.776 ;
    END
  END q[455]
  PIN q[456]
    DIRECTION OUTPUT ;
    USE SIGNAL ;
    PORT
      LAYER M4 ;
        RECT  27.996 16.848 28.08 16.872 ;
    END
  END q[456]
  PIN q[457]
    DIRECTION OUTPUT ;
    USE SIGNAL ;
    PORT
      LAYER M4 ;
        RECT  27.996 16.944 28.08 16.968 ;
    END
  END q[457]
  PIN q[458]
    DIRECTION OUTPUT ;
    USE SIGNAL ;
    PORT
      LAYER M4 ;
        RECT  27.996 17.04 28.08 17.064 ;
    END
  END q[458]
  PIN q[459]
    DIRECTION OUTPUT ;
    USE SIGNAL ;
    PORT
      LAYER M4 ;
        RECT  27.996 17.136 28.08 17.16 ;
    END
  END q[459]
  PIN q[45]
    DIRECTION OUTPUT ;
    USE SIGNAL ;
    PORT
      LAYER M4 ;
        RECT  27.996 27.312 28.08 27.336 ;
    END
  END q[45]
  PIN q[460]
    DIRECTION OUTPUT ;
    USE SIGNAL ;
    PORT
      LAYER M4 ;
        RECT  27.996 17.232 28.08 17.256 ;
    END
  END q[460]
  PIN q[461]
    DIRECTION OUTPUT ;
    USE SIGNAL ;
    PORT
      LAYER M4 ;
        RECT  27.996 17.328 28.08 17.352 ;
    END
  END q[461]
  PIN q[462]
    DIRECTION OUTPUT ;
    USE SIGNAL ;
    PORT
      LAYER M4 ;
        RECT  27.996 17.424 28.08 17.448 ;
    END
  END q[462]
  PIN q[463]
    DIRECTION OUTPUT ;
    USE SIGNAL ;
    PORT
      LAYER M4 ;
        RECT  27.996 17.52 28.08 17.544 ;
    END
  END q[463]
  PIN q[464]
    DIRECTION OUTPUT ;
    USE SIGNAL ;
    PORT
      LAYER M4 ;
        RECT  27.996 17.616 28.08 17.64 ;
    END
  END q[464]
  PIN q[465]
    DIRECTION OUTPUT ;
    USE SIGNAL ;
    PORT
      LAYER M4 ;
        RECT  27.996 17.712 28.08 17.736 ;
    END
  END q[465]
  PIN q[466]
    DIRECTION OUTPUT ;
    USE SIGNAL ;
    PORT
      LAYER M4 ;
        RECT  27.996 17.808 28.08 17.832 ;
    END
  END q[466]
  PIN q[467]
    DIRECTION OUTPUT ;
    USE SIGNAL ;
    PORT
      LAYER M4 ;
        RECT  27.996 17.904 28.08 17.928 ;
    END
  END q[467]
  PIN q[468]
    DIRECTION OUTPUT ;
    USE SIGNAL ;
    PORT
      LAYER M4 ;
        RECT  27.996 18 28.08 18.024 ;
    END
  END q[468]
  PIN q[469]
    DIRECTION OUTPUT ;
    USE SIGNAL ;
    PORT
      LAYER M4 ;
        RECT  27.996 18.096 28.08 18.12 ;
    END
  END q[469]
  PIN q[46]
    DIRECTION OUTPUT ;
    USE SIGNAL ;
    PORT
      LAYER M4 ;
        RECT  27.996 27.408 28.08 27.432 ;
    END
  END q[46]
  PIN q[470]
    DIRECTION OUTPUT ;
    USE SIGNAL ;
    PORT
      LAYER M4 ;
        RECT  27.996 18.192 28.08 18.216 ;
    END
  END q[470]
  PIN q[471]
    DIRECTION OUTPUT ;
    USE SIGNAL ;
    PORT
      LAYER M4 ;
        RECT  27.996 18.288 28.08 18.312 ;
    END
  END q[471]
  PIN q[472]
    DIRECTION OUTPUT ;
    USE SIGNAL ;
    PORT
      LAYER M4 ;
        RECT  27.996 18.384 28.08 18.408 ;
    END
  END q[472]
  PIN q[473]
    DIRECTION OUTPUT ;
    USE SIGNAL ;
    PORT
      LAYER M4 ;
        RECT  27.996 18.48 28.08 18.504 ;
    END
  END q[473]
  PIN q[474]
    DIRECTION OUTPUT ;
    USE SIGNAL ;
    PORT
      LAYER M4 ;
        RECT  27.996 18.576 28.08 18.6 ;
    END
  END q[474]
  PIN q[475]
    DIRECTION OUTPUT ;
    USE SIGNAL ;
    PORT
      LAYER M4 ;
        RECT  27.996 18.672 28.08 18.696 ;
    END
  END q[475]
  PIN q[476]
    DIRECTION OUTPUT ;
    USE SIGNAL ;
    PORT
      LAYER M4 ;
        RECT  27.996 18.768 28.08 18.792 ;
    END
  END q[476]
  PIN q[477]
    DIRECTION OUTPUT ;
    USE SIGNAL ;
    PORT
      LAYER M4 ;
        RECT  27.996 18.864 28.08 18.888 ;
    END
  END q[477]
  PIN q[478]
    DIRECTION OUTPUT ;
    USE SIGNAL ;
    PORT
      LAYER M4 ;
        RECT  27.996 18.96 28.08 18.984 ;
    END
  END q[478]
  PIN q[479]
    DIRECTION OUTPUT ;
    USE SIGNAL ;
    PORT
      LAYER M4 ;
        RECT  27.996 19.056 28.08 19.08 ;
    END
  END q[479]
  PIN q[47]
    DIRECTION OUTPUT ;
    USE SIGNAL ;
    PORT
      LAYER M4 ;
        RECT  27.996 27.504 28.08 27.528 ;
    END
  END q[47]
  PIN q[480]
    DIRECTION OUTPUT ;
    USE SIGNAL ;
    PORT
      LAYER M4 ;
        RECT  27.996 6.864 28.08 6.888 ;
    END
  END q[480]
  PIN q[481]
    DIRECTION OUTPUT ;
    USE SIGNAL ;
    PORT
      LAYER M4 ;
        RECT  27.996 6.96 28.08 6.984 ;
    END
  END q[481]
  PIN q[482]
    DIRECTION OUTPUT ;
    USE SIGNAL ;
    PORT
      LAYER M4 ;
        RECT  27.996 7.056 28.08 7.08 ;
    END
  END q[482]
  PIN q[483]
    DIRECTION OUTPUT ;
    USE SIGNAL ;
    PORT
      LAYER M4 ;
        RECT  27.996 7.152 28.08 7.176 ;
    END
  END q[483]
  PIN q[484]
    DIRECTION OUTPUT ;
    USE SIGNAL ;
    PORT
      LAYER M4 ;
        RECT  27.996 7.248 28.08 7.272 ;
    END
  END q[484]
  PIN q[485]
    DIRECTION OUTPUT ;
    USE SIGNAL ;
    PORT
      LAYER M4 ;
        RECT  27.996 7.344 28.08 7.368 ;
    END
  END q[485]
  PIN q[486]
    DIRECTION OUTPUT ;
    USE SIGNAL ;
    PORT
      LAYER M4 ;
        RECT  27.996 7.44 28.08 7.464 ;
    END
  END q[486]
  PIN q[487]
    DIRECTION OUTPUT ;
    USE SIGNAL ;
    PORT
      LAYER M4 ;
        RECT  27.996 7.536 28.08 7.56 ;
    END
  END q[487]
  PIN q[488]
    DIRECTION OUTPUT ;
    USE SIGNAL ;
    PORT
      LAYER M4 ;
        RECT  27.996 7.632 28.08 7.656 ;
    END
  END q[488]
  PIN q[489]
    DIRECTION OUTPUT ;
    USE SIGNAL ;
    PORT
      LAYER M4 ;
        RECT  27.996 7.728 28.08 7.752 ;
    END
  END q[489]
  PIN q[48]
    DIRECTION OUTPUT ;
    USE SIGNAL ;
    PORT
      LAYER M4 ;
        RECT  27.996 27.6 28.08 27.624 ;
    END
  END q[48]
  PIN q[490]
    DIRECTION OUTPUT ;
    USE SIGNAL ;
    PORT
      LAYER M4 ;
        RECT  27.996 7.824 28.08 7.848 ;
    END
  END q[490]
  PIN q[491]
    DIRECTION OUTPUT ;
    USE SIGNAL ;
    PORT
      LAYER M4 ;
        RECT  27.996 7.92 28.08 7.944 ;
    END
  END q[491]
  PIN q[492]
    DIRECTION OUTPUT ;
    USE SIGNAL ;
    PORT
      LAYER M4 ;
        RECT  27.996 8.016 28.08 8.04 ;
    END
  END q[492]
  PIN q[493]
    DIRECTION OUTPUT ;
    USE SIGNAL ;
    PORT
      LAYER M4 ;
        RECT  27.996 8.112 28.08 8.136 ;
    END
  END q[493]
  PIN q[494]
    DIRECTION OUTPUT ;
    USE SIGNAL ;
    PORT
      LAYER M4 ;
        RECT  27.996 8.208 28.08 8.232 ;
    END
  END q[494]
  PIN q[495]
    DIRECTION OUTPUT ;
    USE SIGNAL ;
    PORT
      LAYER M4 ;
        RECT  27.996 8.304 28.08 8.328 ;
    END
  END q[495]
  PIN q[496]
    DIRECTION OUTPUT ;
    USE SIGNAL ;
    PORT
      LAYER M4 ;
        RECT  27.996 8.4 28.08 8.424 ;
    END
  END q[496]
  PIN q[497]
    DIRECTION OUTPUT ;
    USE SIGNAL ;
    PORT
      LAYER M4 ;
        RECT  27.996 8.496 28.08 8.52 ;
    END
  END q[497]
  PIN q[498]
    DIRECTION OUTPUT ;
    USE SIGNAL ;
    PORT
      LAYER M4 ;
        RECT  27.996 8.592 28.08 8.616 ;
    END
  END q[498]
  PIN q[499]
    DIRECTION OUTPUT ;
    USE SIGNAL ;
    PORT
      LAYER M4 ;
        RECT  27.996 8.688 28.08 8.712 ;
    END
  END q[499]
  PIN q[49]
    DIRECTION OUTPUT ;
    USE SIGNAL ;
    PORT
      LAYER M4 ;
        RECT  27.996 27.696 28.08 27.72 ;
    END
  END q[49]
  PIN q[4]
    DIRECTION OUTPUT ;
    USE SIGNAL ;
    PORT
      LAYER M4 ;
        RECT  27.996 32.592 28.08 32.616 ;
    END
  END q[4]
  PIN q[500]
    DIRECTION OUTPUT ;
    USE SIGNAL ;
    PORT
      LAYER M4 ;
        RECT  27.996 8.784 28.08 8.808 ;
    END
  END q[500]
  PIN q[501]
    DIRECTION OUTPUT ;
    USE SIGNAL ;
    PORT
      LAYER M4 ;
        RECT  27.996 8.88 28.08 8.904 ;
    END
  END q[501]
  PIN q[502]
    DIRECTION OUTPUT ;
    USE SIGNAL ;
    PORT
      LAYER M4 ;
        RECT  27.996 8.976 28.08 9 ;
    END
  END q[502]
  PIN q[503]
    DIRECTION OUTPUT ;
    USE SIGNAL ;
    PORT
      LAYER M4 ;
        RECT  27.996 9.072 28.08 9.096 ;
    END
  END q[503]
  PIN q[504]
    DIRECTION OUTPUT ;
    USE SIGNAL ;
    PORT
      LAYER M4 ;
        RECT  27.996 9.168 28.08 9.192 ;
    END
  END q[504]
  PIN q[505]
    DIRECTION OUTPUT ;
    USE SIGNAL ;
    PORT
      LAYER M4 ;
        RECT  27.996 9.264 28.08 9.288 ;
    END
  END q[505]
  PIN q[506]
    DIRECTION OUTPUT ;
    USE SIGNAL ;
    PORT
      LAYER M4 ;
        RECT  27.996 9.36 28.08 9.384 ;
    END
  END q[506]
  PIN q[507]
    DIRECTION OUTPUT ;
    USE SIGNAL ;
    PORT
      LAYER M4 ;
        RECT  27.996 9.456 28.08 9.48 ;
    END
  END q[507]
  PIN q[508]
    DIRECTION OUTPUT ;
    USE SIGNAL ;
    PORT
      LAYER M4 ;
        RECT  27.996 9.552 28.08 9.576 ;
    END
  END q[508]
  PIN q[509]
    DIRECTION OUTPUT ;
    USE SIGNAL ;
    PORT
      LAYER M4 ;
        RECT  27.996 9.648 28.08 9.672 ;
    END
  END q[509]
  PIN q[50]
    DIRECTION OUTPUT ;
    USE SIGNAL ;
    PORT
      LAYER M4 ;
        RECT  27.996 27.792 28.08 27.816 ;
    END
  END q[50]
  PIN q[510]
    DIRECTION OUTPUT ;
    USE SIGNAL ;
    PORT
      LAYER M4 ;
        RECT  27.996 9.744 28.08 9.768 ;
    END
  END q[510]
  PIN q[511]
    DIRECTION OUTPUT ;
    USE SIGNAL ;
    PORT
      LAYER M4 ;
        RECT  27.996 9.84 28.08 9.864 ;
    END
  END q[511]
  PIN q[51]
    DIRECTION OUTPUT ;
    USE SIGNAL ;
    PORT
      LAYER M4 ;
        RECT  27.996 27.888 28.08 27.912 ;
    END
  END q[51]
  PIN q[52]
    DIRECTION OUTPUT ;
    USE SIGNAL ;
    PORT
      LAYER M4 ;
        RECT  27.996 27.984 28.08 28.008 ;
    END
  END q[52]
  PIN q[53]
    DIRECTION OUTPUT ;
    USE SIGNAL ;
    PORT
      LAYER M4 ;
        RECT  27.996 28.08 28.08 28.104 ;
    END
  END q[53]
  PIN q[54]
    DIRECTION OUTPUT ;
    USE SIGNAL ;
    PORT
      LAYER M4 ;
        RECT  27.996 28.176 28.08 28.2 ;
    END
  END q[54]
  PIN q[55]
    DIRECTION OUTPUT ;
    USE SIGNAL ;
    PORT
      LAYER M4 ;
        RECT  27.996 28.272 28.08 28.296 ;
    END
  END q[55]
  PIN q[56]
    DIRECTION OUTPUT ;
    USE SIGNAL ;
    PORT
      LAYER M4 ;
        RECT  27.996 28.368 28.08 28.392 ;
    END
  END q[56]
  PIN q[57]
    DIRECTION OUTPUT ;
    USE SIGNAL ;
    PORT
      LAYER M4 ;
        RECT  27.996 28.464 28.08 28.488 ;
    END
  END q[57]
  PIN q[58]
    DIRECTION OUTPUT ;
    USE SIGNAL ;
    PORT
      LAYER M4 ;
        RECT  27.996 28.56 28.08 28.584 ;
    END
  END q[58]
  PIN q[59]
    DIRECTION OUTPUT ;
    USE SIGNAL ;
    PORT
      LAYER M4 ;
        RECT  27.996 28.656 28.08 28.68 ;
    END
  END q[59]
  PIN q[5]
    DIRECTION OUTPUT ;
    USE SIGNAL ;
    PORT
      LAYER M4 ;
        RECT  27.996 32.688 28.08 32.712 ;
    END
  END q[5]
  PIN q[60]
    DIRECTION OUTPUT ;
    USE SIGNAL ;
    PORT
      LAYER M4 ;
        RECT  27.996 28.752 28.08 28.776 ;
    END
  END q[60]
  PIN q[61]
    DIRECTION OUTPUT ;
    USE SIGNAL ;
    PORT
      LAYER M4 ;
        RECT  27.996 28.848 28.08 28.872 ;
    END
  END q[61]
  PIN q[62]
    DIRECTION OUTPUT ;
    USE SIGNAL ;
    PORT
      LAYER M4 ;
        RECT  27.996 28.944 28.08 28.968 ;
    END
  END q[62]
  PIN q[63]
    DIRECTION OUTPUT ;
    USE SIGNAL ;
    PORT
      LAYER M4 ;
        RECT  27.996 29.04 28.08 29.064 ;
    END
  END q[63]
  PIN q[64]
    DIRECTION OUTPUT ;
    USE SIGNAL ;
    PORT
      LAYER M4 ;
        RECT  27.996 22.992 28.08 23.016 ;
    END
  END q[64]
  PIN q[65]
    DIRECTION OUTPUT ;
    USE SIGNAL ;
    PORT
      LAYER M4 ;
        RECT  27.996 23.088 28.08 23.112 ;
    END
  END q[65]
  PIN q[66]
    DIRECTION OUTPUT ;
    USE SIGNAL ;
    PORT
      LAYER M4 ;
        RECT  27.996 23.184 28.08 23.208 ;
    END
  END q[66]
  PIN q[67]
    DIRECTION OUTPUT ;
    USE SIGNAL ;
    PORT
      LAYER M4 ;
        RECT  27.996 23.28 28.08 23.304 ;
    END
  END q[67]
  PIN q[68]
    DIRECTION OUTPUT ;
    USE SIGNAL ;
    PORT
      LAYER M4 ;
        RECT  27.996 23.376 28.08 23.4 ;
    END
  END q[68]
  PIN q[69]
    DIRECTION OUTPUT ;
    USE SIGNAL ;
    PORT
      LAYER M4 ;
        RECT  27.996 23.472 28.08 23.496 ;
    END
  END q[69]
  PIN q[6]
    DIRECTION OUTPUT ;
    USE SIGNAL ;
    PORT
      LAYER M4 ;
        RECT  27.996 32.784 28.08 32.808 ;
    END
  END q[6]
  PIN q[70]
    DIRECTION OUTPUT ;
    USE SIGNAL ;
    PORT
      LAYER M4 ;
        RECT  27.996 23.568 28.08 23.592 ;
    END
  END q[70]
  PIN q[71]
    DIRECTION OUTPUT ;
    USE SIGNAL ;
    PORT
      LAYER M4 ;
        RECT  27.996 23.664 28.08 23.688 ;
    END
  END q[71]
  PIN q[72]
    DIRECTION OUTPUT ;
    USE SIGNAL ;
    PORT
      LAYER M4 ;
        RECT  27.996 23.76 28.08 23.784 ;
    END
  END q[72]
  PIN q[73]
    DIRECTION OUTPUT ;
    USE SIGNAL ;
    PORT
      LAYER M4 ;
        RECT  27.996 23.856 28.08 23.88 ;
    END
  END q[73]
  PIN q[74]
    DIRECTION OUTPUT ;
    USE SIGNAL ;
    PORT
      LAYER M4 ;
        RECT  27.996 23.952 28.08 23.976 ;
    END
  END q[74]
  PIN q[75]
    DIRECTION OUTPUT ;
    USE SIGNAL ;
    PORT
      LAYER M4 ;
        RECT  27.996 24.048 28.08 24.072 ;
    END
  END q[75]
  PIN q[76]
    DIRECTION OUTPUT ;
    USE SIGNAL ;
    PORT
      LAYER M4 ;
        RECT  27.996 24.144 28.08 24.168 ;
    END
  END q[76]
  PIN q[77]
    DIRECTION OUTPUT ;
    USE SIGNAL ;
    PORT
      LAYER M4 ;
        RECT  27.996 24.24 28.08 24.264 ;
    END
  END q[77]
  PIN q[78]
    DIRECTION OUTPUT ;
    USE SIGNAL ;
    PORT
      LAYER M4 ;
        RECT  27.996 24.336 28.08 24.36 ;
    END
  END q[78]
  PIN q[79]
    DIRECTION OUTPUT ;
    USE SIGNAL ;
    PORT
      LAYER M4 ;
        RECT  27.996 24.432 28.08 24.456 ;
    END
  END q[79]
  PIN q[7]
    DIRECTION OUTPUT ;
    USE SIGNAL ;
    PORT
      LAYER M4 ;
        RECT  27.996 32.88 28.08 32.904 ;
    END
  END q[7]
  PIN q[80]
    DIRECTION OUTPUT ;
    USE SIGNAL ;
    PORT
      LAYER M4 ;
        RECT  27.996 24.528 28.08 24.552 ;
    END
  END q[80]
  PIN q[81]
    DIRECTION OUTPUT ;
    USE SIGNAL ;
    PORT
      LAYER M4 ;
        RECT  27.996 24.624 28.08 24.648 ;
    END
  END q[81]
  PIN q[82]
    DIRECTION OUTPUT ;
    USE SIGNAL ;
    PORT
      LAYER M4 ;
        RECT  27.996 24.72 28.08 24.744 ;
    END
  END q[82]
  PIN q[83]
    DIRECTION OUTPUT ;
    USE SIGNAL ;
    PORT
      LAYER M4 ;
        RECT  27.996 24.816 28.08 24.84 ;
    END
  END q[83]
  PIN q[84]
    DIRECTION OUTPUT ;
    USE SIGNAL ;
    PORT
      LAYER M4 ;
        RECT  27.996 24.912 28.08 24.936 ;
    END
  END q[84]
  PIN q[85]
    DIRECTION OUTPUT ;
    USE SIGNAL ;
    PORT
      LAYER M4 ;
        RECT  27.996 25.008 28.08 25.032 ;
    END
  END q[85]
  PIN q[86]
    DIRECTION OUTPUT ;
    USE SIGNAL ;
    PORT
      LAYER M4 ;
        RECT  27.996 25.104 28.08 25.128 ;
    END
  END q[86]
  PIN q[87]
    DIRECTION OUTPUT ;
    USE SIGNAL ;
    PORT
      LAYER M4 ;
        RECT  27.996 25.2 28.08 25.224 ;
    END
  END q[87]
  PIN q[88]
    DIRECTION OUTPUT ;
    USE SIGNAL ;
    PORT
      LAYER M4 ;
        RECT  27.996 25.296 28.08 25.32 ;
    END
  END q[88]
  PIN q[89]
    DIRECTION OUTPUT ;
    USE SIGNAL ;
    PORT
      LAYER M4 ;
        RECT  27.996 25.392 28.08 25.416 ;
    END
  END q[89]
  PIN q[8]
    DIRECTION OUTPUT ;
    USE SIGNAL ;
    PORT
      LAYER M4 ;
        RECT  27.996 32.976 28.08 33 ;
    END
  END q[8]
  PIN q[90]
    DIRECTION OUTPUT ;
    USE SIGNAL ;
    PORT
      LAYER M4 ;
        RECT  27.996 25.488 28.08 25.512 ;
    END
  END q[90]
  PIN q[91]
    DIRECTION OUTPUT ;
    USE SIGNAL ;
    PORT
      LAYER M4 ;
        RECT  27.996 25.584 28.08 25.608 ;
    END
  END q[91]
  PIN q[92]
    DIRECTION OUTPUT ;
    USE SIGNAL ;
    PORT
      LAYER M4 ;
        RECT  27.996 25.68 28.08 25.704 ;
    END
  END q[92]
  PIN q[93]
    DIRECTION OUTPUT ;
    USE SIGNAL ;
    PORT
      LAYER M4 ;
        RECT  27.996 25.776 28.08 25.8 ;
    END
  END q[93]
  PIN q[94]
    DIRECTION OUTPUT ;
    USE SIGNAL ;
    PORT
      LAYER M4 ;
        RECT  27.996 25.872 28.08 25.896 ;
    END
  END q[94]
  PIN q[95]
    DIRECTION OUTPUT ;
    USE SIGNAL ;
    PORT
      LAYER M4 ;
        RECT  27.996 25.968 28.08 25.992 ;
    END
  END q[95]
  PIN q[96]
    DIRECTION OUTPUT ;
    USE SIGNAL ;
    PORT
      LAYER M4 ;
        RECT  27.996 35.28 28.08 35.304 ;
    END
  END q[96]
  PIN q[97]
    DIRECTION OUTPUT ;
    USE SIGNAL ;
    PORT
      LAYER M4 ;
        RECT  27.996 35.376 28.08 35.4 ;
    END
  END q[97]
  PIN q[98]
    DIRECTION OUTPUT ;
    USE SIGNAL ;
    PORT
      LAYER M4 ;
        RECT  27.996 35.472 28.08 35.496 ;
    END
  END q[98]
  PIN q[99]
    DIRECTION OUTPUT ;
    USE SIGNAL ;
    PORT
      LAYER M4 ;
        RECT  27.996 35.568 28.08 35.592 ;
    END
  END q[99]
  PIN q[9]
    DIRECTION OUTPUT ;
    USE SIGNAL ;
    PORT
      LAYER M4 ;
        RECT  27.996 33.072 28.08 33.096 ;
    END
  END q[9]
  PIN VDD
    DIRECTION INOUT ;
    USE POWER ;
    PORT
      LAYER M5 ;
        RECT  24.192 2.151 24.312 62.649 ;
        RECT  18.792 2.151 18.912 62.649 ;
        RECT  13.392 2.151 13.512 62.649 ;
        RECT  7.992 2.151 8.112 62.649 ;
        RECT  2.592 2.151 2.712 62.649 ;
    END
  END VDD
  PIN VSS
    DIRECTION INOUT ;
    USE GROUND ;
    PORT
      LAYER M5 ;
        RECT  24 2.137 24.12 62.663 ;
        RECT  18.6 2.137 18.72 62.663 ;
        RECT  13.2 2.137 13.32 62.663 ;
        RECT  7.8 2.137 7.92 62.663 ;
        RECT  2.4 2.137 2.52 62.663 ;
    END
  END VSS
  OBS
    LAYER RVTN ;
     RECT  2.16 2.16 25.92 2.295 ;
     RECT  2.16 2.565 25.92 2.835 ;
     RECT  2.16 3.105 25.92 3.375 ;
     RECT  2.16 3.645 25.92 3.915 ;
     RECT  2.16 4.185 25.92 4.455 ;
     RECT  2.16 4.725 25.92 4.995 ;
     RECT  2.16 5.265 25.92 5.535 ;
     RECT  2.16 5.805 25.92 6.075 ;
     RECT  2.16 6.345 25.92 6.615 ;
     RECT  2.16 6.885 25.92 7.155 ;
     RECT  2.16 7.425 25.92 7.695 ;
     RECT  2.16 7.965 25.92 8.235 ;
     RECT  2.16 8.505 25.92 8.775 ;
     RECT  2.16 9.045 25.92 9.315 ;
     RECT  2.16 9.585 25.92 9.855 ;
     RECT  2.16 10.125 25.92 10.395 ;
     RECT  2.16 10.665 25.92 10.935 ;
     RECT  2.16 11.205 25.92 11.475 ;
     RECT  2.16 11.745 25.92 12.015 ;
     RECT  2.16 12.285 25.92 12.555 ;
     RECT  2.16 12.825 25.92 13.095 ;
     RECT  2.16 13.365 25.92 13.635 ;
     RECT  2.16 13.905 25.92 14.175 ;
     RECT  2.16 14.445 25.92 14.715 ;
     RECT  2.16 14.985 25.92 15.255 ;
     RECT  2.16 15.525 25.92 15.795 ;
     RECT  2.16 16.065 25.92 16.335 ;
     RECT  2.16 16.605 25.92 16.875 ;
     RECT  2.16 17.145 25.92 17.415 ;
     RECT  2.16 17.685 25.92 17.955 ;
     RECT  2.16 18.225 25.92 18.495 ;
     RECT  2.16 18.765 25.92 19.035 ;
     RECT  2.16 19.305 25.92 19.575 ;
     RECT  2.16 19.845 25.92 20.115 ;
     RECT  2.16 20.385 25.92 20.655 ;
     RECT  2.16 20.925 25.92 21.195 ;
     RECT  2.16 21.465 25.92 21.735 ;
     RECT  2.16 22.005 25.92 22.275 ;
     RECT  2.16 22.545 25.92 22.815 ;
     RECT  2.16 23.085 25.92 23.355 ;
     RECT  2.16 23.625 25.92 23.895 ;
     RECT  2.16 24.165 25.92 24.435 ;
     RECT  2.16 24.705 25.92 24.975 ;
     RECT  2.16 25.245 25.92 25.515 ;
     RECT  2.16 25.785 25.92 26.055 ;
     RECT  2.16 26.325 25.92 26.595 ;
     RECT  2.16 26.865 25.92 27.135 ;
     RECT  2.16 27.405 25.92 27.675 ;
     RECT  2.16 27.945 25.92 28.215 ;
     RECT  2.16 28.485 25.92 28.755 ;
     RECT  2.16 29.025 25.92 29.295 ;
     RECT  2.16 29.565 25.92 29.835 ;
     RECT  2.16 30.105 25.92 30.375 ;
     RECT  2.16 30.645 25.92 30.915 ;
     RECT  2.16 31.185 25.92 31.455 ;
     RECT  2.16 31.725 25.92 31.995 ;
     RECT  2.16 32.265 25.92 32.535 ;
     RECT  2.16 32.805 25.92 33.075 ;
     RECT  2.16 33.345 25.92 33.615 ;
     RECT  2.16 33.885 25.92 34.155 ;
     RECT  2.16 34.425 25.92 34.695 ;
     RECT  2.16 34.965 25.92 35.235 ;
     RECT  2.16 35.505 25.92 35.775 ;
     RECT  2.16 36.045 25.92 36.315 ;
     RECT  2.16 36.585 25.92 36.855 ;
     RECT  2.16 37.125 25.92 37.395 ;
     RECT  2.16 37.665 25.92 37.935 ;
     RECT  2.16 38.205 25.92 38.475 ;
     RECT  2.16 38.745 25.92 39.015 ;
     RECT  2.16 39.285 25.92 39.555 ;
     RECT  2.16 39.825 25.92 40.095 ;
     RECT  2.16 40.365 25.92 40.635 ;
     RECT  2.16 40.905 25.92 41.175 ;
     RECT  2.16 41.445 25.92 41.715 ;
     RECT  2.16 41.985 25.92 42.255 ;
     RECT  2.16 42.525 25.92 42.795 ;
     RECT  2.16 43.065 25.92 43.335 ;
     RECT  2.16 43.605 25.92 43.875 ;
     RECT  2.16 44.145 25.92 44.415 ;
     RECT  2.16 44.685 25.92 44.955 ;
     RECT  2.16 45.225 25.92 45.495 ;
     RECT  2.16 45.765 25.92 46.035 ;
     RECT  2.16 46.305 25.92 46.575 ;
     RECT  2.16 46.845 25.92 47.115 ;
     RECT  2.16 47.385 25.92 47.655 ;
     RECT  2.16 47.925 25.92 48.195 ;
     RECT  2.16 48.465 25.92 48.735 ;
     RECT  2.16 49.005 25.92 49.275 ;
     RECT  2.16 49.545 25.92 49.815 ;
     RECT  2.16 50.085 25.92 50.355 ;
     RECT  2.16 50.625 25.92 50.895 ;
     RECT  2.16 51.165 25.92 51.435 ;
     RECT  2.16 51.705 25.92 51.975 ;
     RECT  2.16 52.245 25.92 52.515 ;
     RECT  2.16 52.785 25.92 53.055 ;
     RECT  2.16 53.325 25.92 53.595 ;
     RECT  2.16 53.865 25.92 54.135 ;
     RECT  2.16 54.405 25.92 54.675 ;
     RECT  2.16 54.945 25.92 55.215 ;
     RECT  2.16 55.485 25.92 55.755 ;
     RECT  2.16 56.025 25.92 56.295 ;
     RECT  2.16 56.565 25.92 56.835 ;
     RECT  2.16 57.105 25.92 57.375 ;
     RECT  2.16 57.645 25.92 57.915 ;
     RECT  2.16 58.185 25.92 58.455 ;
     RECT  2.16 58.725 25.92 58.995 ;
     RECT  2.16 59.265 25.92 59.535 ;
     RECT  2.16 59.805 25.92 60.075 ;
     RECT  2.16 60.345 25.92 60.615 ;
     RECT  2.16 60.885 25.92 61.155 ;
     RECT  2.16 61.425 25.92 61.695 ;
     RECT  2.16 61.965 25.92 62.235 ;
     RECT  2.16 62.505 25.92 62.64 ;
    LAYER RVTP ;
     RECT  2.16 2.295 25.92 2.565 ;
     RECT  2.16 2.835 25.92 3.105 ;
     RECT  2.16 3.375 25.92 3.645 ;
     RECT  2.16 3.915 25.92 4.185 ;
     RECT  2.16 4.455 25.92 4.725 ;
     RECT  2.16 4.995 25.92 5.265 ;
     RECT  2.16 5.535 25.92 5.805 ;
     RECT  2.16 6.075 25.92 6.345 ;
     RECT  2.16 6.615 25.92 6.885 ;
     RECT  2.16 7.155 25.92 7.425 ;
     RECT  2.16 7.695 25.92 7.965 ;
     RECT  2.16 8.235 25.92 8.505 ;
     RECT  2.16 8.775 25.92 9.045 ;
     RECT  2.16 9.315 25.92 9.585 ;
     RECT  2.16 9.855 25.92 10.125 ;
     RECT  2.16 10.395 25.92 10.665 ;
     RECT  2.16 10.935 25.92 11.205 ;
     RECT  2.16 11.475 25.92 11.745 ;
     RECT  2.16 12.015 25.92 12.285 ;
     RECT  2.16 12.555 25.92 12.825 ;
     RECT  2.16 13.095 25.92 13.365 ;
     RECT  2.16 13.635 25.92 13.905 ;
     RECT  2.16 14.175 25.92 14.445 ;
     RECT  2.16 14.715 25.92 14.985 ;
     RECT  2.16 15.255 25.92 15.525 ;
     RECT  2.16 15.795 25.92 16.065 ;
     RECT  2.16 16.335 25.92 16.605 ;
     RECT  2.16 16.875 25.92 17.145 ;
     RECT  2.16 17.415 25.92 17.685 ;
     RECT  2.16 17.955 25.92 18.225 ;
     RECT  2.16 18.495 25.92 18.765 ;
     RECT  2.16 19.035 25.92 19.305 ;
     RECT  2.16 19.575 25.92 19.845 ;
     RECT  2.16 20.115 25.92 20.385 ;
     RECT  2.16 20.655 25.92 20.925 ;
     RECT  2.16 21.195 25.92 21.465 ;
     RECT  2.16 21.735 25.92 22.005 ;
     RECT  2.16 22.275 25.92 22.545 ;
     RECT  2.16 22.815 25.92 23.085 ;
     RECT  2.16 23.355 25.92 23.625 ;
     RECT  2.16 23.895 25.92 24.165 ;
     RECT  2.16 24.435 25.92 24.705 ;
     RECT  2.16 24.975 25.92 25.245 ;
     RECT  2.16 25.515 25.92 25.785 ;
     RECT  2.16 26.055 25.92 26.325 ;
     RECT  2.16 26.595 25.92 26.865 ;
     RECT  2.16 27.135 25.92 27.405 ;
     RECT  2.16 27.675 25.92 27.945 ;
     RECT  2.16 28.215 25.92 28.485 ;
     RECT  2.16 28.755 25.92 29.025 ;
     RECT  2.16 29.295 25.92 29.565 ;
     RECT  2.16 29.835 25.92 30.105 ;
     RECT  2.16 30.375 25.92 30.645 ;
     RECT  2.16 30.915 25.92 31.185 ;
     RECT  2.16 31.455 25.92 31.725 ;
     RECT  2.16 31.995 25.92 32.265 ;
     RECT  2.16 32.535 25.92 32.805 ;
     RECT  2.16 33.075 25.92 33.345 ;
     RECT  2.16 33.615 25.92 33.885 ;
     RECT  2.16 34.155 25.92 34.425 ;
     RECT  2.16 34.695 25.92 34.965 ;
     RECT  2.16 35.235 25.92 35.505 ;
     RECT  2.16 35.775 25.92 36.045 ;
     RECT  2.16 36.315 25.92 36.585 ;
     RECT  2.16 36.855 25.92 37.125 ;
     RECT  2.16 37.395 25.92 37.665 ;
     RECT  2.16 37.935 25.92 38.205 ;
     RECT  2.16 38.475 25.92 38.745 ;
     RECT  2.16 39.015 25.92 39.285 ;
     RECT  2.16 39.555 25.92 39.825 ;
     RECT  2.16 40.095 25.92 40.365 ;
     RECT  2.16 40.635 25.92 40.905 ;
     RECT  2.16 41.175 25.92 41.445 ;
     RECT  2.16 41.715 25.92 41.985 ;
     RECT  2.16 42.255 25.92 42.525 ;
     RECT  2.16 42.795 25.92 43.065 ;
     RECT  2.16 43.335 25.92 43.605 ;
     RECT  2.16 43.875 25.92 44.145 ;
     RECT  2.16 44.415 25.92 44.685 ;
     RECT  2.16 44.955 25.92 45.225 ;
     RECT  2.16 45.495 25.92 45.765 ;
     RECT  2.16 46.035 25.92 46.305 ;
     RECT  2.16 46.575 25.92 46.845 ;
     RECT  2.16 47.115 25.92 47.385 ;
     RECT  2.16 47.655 25.92 47.925 ;
     RECT  2.16 48.195 25.92 48.465 ;
     RECT  2.16 48.735 25.92 49.005 ;
     RECT  2.16 49.275 25.92 49.545 ;
     RECT  2.16 49.815 25.92 50.085 ;
     RECT  2.16 50.355 25.92 50.625 ;
     RECT  2.16 50.895 25.92 51.165 ;
     RECT  2.16 51.435 25.92 51.705 ;
     RECT  2.16 51.975 25.92 52.245 ;
     RECT  2.16 52.515 25.92 52.785 ;
     RECT  2.16 53.055 25.92 53.325 ;
     RECT  2.16 53.595 25.92 53.865 ;
     RECT  2.16 54.135 25.92 54.405 ;
     RECT  2.16 54.675 25.92 54.945 ;
     RECT  2.16 55.215 25.92 55.485 ;
     RECT  2.16 55.755 25.92 56.025 ;
     RECT  2.16 56.295 25.92 56.565 ;
     RECT  2.16 56.835 25.92 57.105 ;
     RECT  2.16 57.375 25.92 57.645 ;
     RECT  2.16 57.915 25.92 58.185 ;
     RECT  2.16 58.455 25.92 58.725 ;
     RECT  2.16 58.995 25.92 59.265 ;
     RECT  2.16 59.535 25.92 59.805 ;
     RECT  2.16 60.075 25.92 60.345 ;
     RECT  2.16 60.615 25.92 60.885 ;
     RECT  2.16 61.155 25.92 61.425 ;
     RECT  2.16 61.695 25.92 61.965 ;
     RECT  2.16 62.235 25.92 62.505 ;
    LAYER M1 ;
     RECT  2.16 2.151 25.92 62.649 ;
    LAYER M2 ;
     RECT  0.031 41.796 0.067 41.814 ;
     RECT  0.031 50.526 0.067 50.544 ;
     RECT  0.067 9.981 0.103 9.999 ;
     RECT  0.031 13.572 0.103 13.59 ;
     RECT  0.067 14.454 0.103 14.472 ;
     RECT  0.031 18.702 0.103 18.72 ;
     RECT  0.031 32.472 0.103 32.49 ;
     RECT  0.031 36.018 0.103 36.036 ;
     RECT  0.067 41.796 0.103 42.318 ;
     RECT  0.031 45.81 0.103 45.828 ;
     RECT  0.067 46.971 0.103 47.106 ;
     RECT  0.031 47.862 0.103 47.88 ;
     RECT  0.067 50.256 0.103 50.544 ;
     RECT  0.103 36.018 0.131 36.378 ;
     RECT  0.103 45.27 0.131 45.828 ;
     RECT  0.103 13.572 0.139 13.662 ;
     RECT  0.103 14.454 0.139 14.778 ;
     RECT  0.103 28.962 0.139 29.52 ;
     RECT  0.103 32.472 0.139 32.868 ;
     RECT  0.103 37.602 0.139 38.538 ;
     RECT  0.103 39.87 0.139 40.356 ;
     RECT  0.103 53.496 0.139 53.514 ;
     RECT  0.103 54.45 0.139 54.468 ;
     RECT  0.103 50.256 0.167 50.958 ;
     RECT  0.103 7.704 0.175 7.722 ;
     RECT  0.103 9.711 0.175 10.116 ;
     RECT  0.103 20.898 0.175 21.456 ;
     RECT  0.139 22.212 0.175 22.23 ;
     RECT  0.103 30.654 0.175 31.716 ;
     RECT  0.139 32.472 0.175 33.606 ;
     RECT  0.131 36.09 0.175 36.378 ;
     RECT  0.139 37.368 0.175 38.538 ;
     RECT  0.103 43.848 0.175 43.866 ;
     RECT  0.103 46.971 0.175 47.88 ;
     RECT  0.167 50.67 0.175 50.958 ;
     RECT  0.103 8.55 0.203 8.568 ;
     RECT  0.175 9.711 0.203 10.692 ;
     RECT  0.175 20.898 0.203 22.23 ;
     RECT  0.139 13.572 0.211 14.778 ;
     RECT  0.103 24.48 0.211 24.498 ;
     RECT  0.175 46.971 0.211 48.15 ;
     RECT  0.175 50.67 0.211 51.228 ;
     RECT  0.103 41.382 0.247 42.624 ;
     RECT  0.203 10.098 0.275 10.692 ;
     RECT  0.247 41.382 0.283 42.75 ;
     RECT  0.175 43.65 0.283 43.866 ;
     RECT  0.211 13.572 0.311 14.859 ;
     RECT  0.211 49.86 0.319 49.878 ;
     RECT  0.175 7.47 0.347 7.722 ;
     RECT  0.275 10.674 0.347 10.692 ;
     RECT  0.211 20.196 0.347 20.214 ;
     RECT  0.203 21.816 0.347 22.23 ;
     RECT  0.211 46.314 0.355 48.15 ;
     RECT  0.139 28.836 0.383 29.52 ;
     RECT  0.355 46.314 0.391 48.222 ;
     RECT  0.319 15.876 0.419 15.894 ;
     RECT  0.355 34.362 0.427 34.38 ;
     RECT  0.211 50.67 0.427 51.768 ;
     RECT  0.391 52.596 0.427 52.614 ;
     RECT  0.175 36.09 0.463 38.538 ;
     RECT  0.139 39.6 0.463 40.356 ;
     RECT  0.427 50.67 0.463 52.614 ;
     RECT  0.139 53.496 0.463 54.468 ;
     RECT  0.311 13.572 0.499 14.778 ;
     RECT  0.103 26.874 0.499 26.892 ;
     RECT  0.499 13.41 0.535 14.778 ;
     RECT  0.211 23.904 0.535 24.498 ;
     RECT  0.499 26.874 0.535 27.162 ;
     RECT  0.103 27.918 0.535 27.936 ;
     RECT  0.383 29.502 0.535 29.52 ;
     RECT  0.175 30.654 0.535 33.606 ;
     RECT  0.427 34.362 0.535 34.488 ;
     RECT  0.463 36.09 0.535 40.356 ;
     RECT  0.283 41.382 0.535 43.866 ;
     RECT  0.463 50.67 0.535 54.468 ;
     RECT  0.391 46.314 0.599 48.42 ;
     RECT  0.535 29.502 1.111 33.606 ;
     RECT  0.535 34.362 1.111 35.226 ;
     RECT  0.823 16.686 1.147 16.704 ;
     RECT  0.131 45.27 1.147 45.558 ;
     RECT  0.535 36.09 1.183 43.866 ;
     RECT  1.147 44.658 1.183 45.558 ;
     RECT  1.183 36.09 1.399 45.558 ;
     RECT  0.535 23.634 1.435 24.498 ;
     RECT  1.399 25.254 1.435 25.272 ;
     RECT  1.435 23.634 1.471 25.272 ;
     RECT  1.147 16.686 1.507 16.974 ;
     RECT  1.435 21.276 1.507 21.294 ;
     RECT  0.347 22.05 1.507 22.23 ;
     RECT  0.535 26.874 1.543 28.314 ;
     RECT  1.111 29.502 1.543 35.226 ;
     RECT  1.399 36.018 1.543 45.558 ;
     RECT  1.543 26.604 1.615 28.314 ;
     RECT  0.535 19.62 1.651 19.638 ;
     RECT  1.507 21.276 1.687 22.23 ;
     RECT  1.471 23.634 1.687 25.344 ;
     RECT  1.147 9.792 1.723 9.81 ;
     RECT  0.535 13.068 1.723 14.778 ;
     RECT  1.651 19.62 1.723 19.764 ;
     RECT  0.103 18 1.867 18.72 ;
     RECT  1.723 19.62 1.867 20.34 ;
     RECT  1.687 21.276 1.867 25.344 ;
     RECT  0.599 46.314 1.867 48.294 ;
     RECT  0.319 49.32 1.867 49.878 ;
     RECT  1.507 16.272 1.903 16.974 ;
     RECT  1.723 13.068 1.975 15.318 ;
     RECT  1.975 12.906 2.011 15.318 ;
     RECT  1.543 29.502 2.047 45.558 ;
     RECT  1.867 46.314 2.047 49.878 ;
     RECT  1.723 9.792 2.16 11.16 ;
     RECT  2.011 12.492 2.16 15.318 ;
     RECT  1.903 16.272 2.16 17.136 ;
     RECT  1.867 17.928 2.16 18.72 ;
     RECT  1.867 19.62 2.16 25.344 ;
     RECT  1.615 26.1 2.16 28.314 ;
     RECT  2.047 29.502 2.16 49.878 ;
     RECT  0.535 50.67 2.16 54.504 ;
     RECT  0.103 55.998 2.16 56.016 ;
     RECT  2.16 2.151 25.92 62.649 ;
     RECT  25.92 7.056 26.231 52.074 ;
     RECT  26.231 7.056 26.519 51.534 ;
     RECT  25.92 61.596 26.519 61.614 ;
     RECT  26.519 13.266 26.627 51.534 ;
     RECT  26.627 13.266 26.771 50.724 ;
     RECT  26.519 7.056 26.807 12.114 ;
     RECT  26.771 30.276 26.807 50.724 ;
     RECT  25.92 52.866 26.807 58.374 ;
     RECT  26.771 13.266 26.843 29.484 ;
     RECT  26.807 49.05 26.843 50.724 ;
     RECT  26.807 7.326 27.095 12.114 ;
     RECT  26.843 13.266 27.095 29.052 ;
     RECT  27.095 13.266 27.131 15.624 ;
     RECT  27.095 16.416 27.275 29.052 ;
     RECT  26.807 57.816 27.275 58.374 ;
     RECT  27.095 7.326 27.311 11.736 ;
     RECT  27.275 57.816 27.311 58.104 ;
     RECT  27.311 7.326 27.347 7.884 ;
     RECT  27.131 13.266 27.347 15.21 ;
     RECT  27.275 21.978 27.347 29.052 ;
     RECT  26.807 30.276 27.347 34.074 ;
     RECT  26.807 35.136 27.347 48.114 ;
     RECT  26.807 52.866 27.347 56.934 ;
     RECT  27.311 58.086 27.347 58.104 ;
     RECT  27.347 7.668 27.383 7.884 ;
     RECT  27.275 16.416 27.383 21.114 ;
     RECT  27.347 26.838 27.383 29.052 ;
     RECT  27.347 31.356 27.383 33.678 ;
     RECT  27.347 35.136 27.383 36.108 ;
     RECT  27.347 39.096 27.383 47.214 ;
     RECT  27.347 52.866 27.383 55.278 ;
     RECT  27.347 56.376 27.383 56.934 ;
     RECT  27.383 16.416 27.419 19.944 ;
     RECT  27.383 39.726 27.419 47.142 ;
     RECT  27.383 54.486 27.419 55.278 ;
     RECT  27.383 56.376 27.419 56.592 ;
     RECT  27.419 42.696 27.455 47.142 ;
     RECT  27.383 53.136 27.455 53.514 ;
     RECT  27.419 54.486 27.455 54.594 ;
     RECT  26.843 49.284 27.535 50.724 ;
     RECT  27.535 49.284 27.599 50.769 ;
     RECT  27.599 49.626 27.671 50.769 ;
     RECT  27.671 49.626 27.743 49.644 ;
     RECT  27.419 39.726 27.779 41.778 ;
     RECT  27.455 42.696 27.779 46.332 ;
     RECT  27.347 37.206 27.815 38.304 ;
     RECT  27.311 8.748 27.823 11.736 ;
     RECT  27.823 8.748 27.851 11.808 ;
     RECT  27.815 37.206 27.851 38.268 ;
     RECT  27.419 16.416 27.887 17.514 ;
     RECT  27.779 41.256 27.887 41.778 ;
     RECT  27.779 42.696 27.887 45.288 ;
     RECT  27.671 50.436 27.895 50.769 ;
     RECT  26.627 51.516 27.895 51.534 ;
     RECT  27.419 18.576 27.923 19.404 ;
     RECT  27.383 21.096 27.923 21.114 ;
     RECT  27.887 42.966 27.923 45.288 ;
     RECT  27.787 48.132 27.923 48.15 ;
     RECT  27.851 8.748 27.959 11.034 ;
     RECT  27.887 16.416 27.959 16.434 ;
     RECT  27.887 17.496 27.959 17.514 ;
     RECT  27.923 18.702 27.959 19.404 ;
     RECT  27.347 21.978 27.959 25.974 ;
     RECT  27.383 26.946 27.959 29.052 ;
     RECT  27.383 31.356 27.959 33.066 ;
     RECT  27.779 39.726 27.959 40.284 ;
     RECT  27.887 41.346 27.959 41.778 ;
     RECT  27.779 46.314 27.959 46.332 ;
     RECT  27.455 47.124 27.959 47.142 ;
     RECT  27.455 54.486 27.959 54.504 ;
     RECT  27.895 50.436 27.967 51.534 ;
     RECT  27.383 7.668 27.995 7.758 ;
     RECT  27.959 8.748 27.995 8.766 ;
     RECT  27.959 9.828 27.995 11.034 ;
     RECT  27.347 13.644 27.995 15.21 ;
     RECT  27.959 22.518 27.995 22.536 ;
     RECT  27.959 23.328 27.995 25.974 ;
     RECT  27.959 26.946 27.995 26.964 ;
     RECT  27.959 27.846 27.995 28.584 ;
     RECT  27.959 31.806 27.995 31.824 ;
     RECT  27.959 33.048 27.995 33.066 ;
     RECT  27.383 35.406 27.995 35.424 ;
     RECT  27.851 37.206 27.995 37.809 ;
     RECT  27.959 41.346 27.995 41.364 ;
     RECT  27.923 42.966 27.995 43.866 ;
     RECT  27.923 44.658 27.995 45.288 ;
     RECT  27.967 50.436 27.995 52.002 ;
     RECT  27.455 53.136 27.995 53.154 ;
     RECT  27.419 56.376 27.995 56.394 ;
     RECT  27.995 10.746 28.031 11.034 ;
     RECT  27.995 15.192 28.031 15.21 ;
     RECT  27.959 18.81 28.031 19.404 ;
     RECT  27.995 24.066 28.031 24.084 ;
     RECT  27.995 42.966 28.031 42.984 ;
     RECT  27.995 50.634 28.031 50.958 ;
     RECT  27.995 7.74 28.067 7.758 ;
     RECT  28.031 11.016 28.067 11.034 ;
     RECT  27.851 11.79 28.067 11.808 ;
     RECT  28.031 19.386 28.067 19.404 ;
     RECT  27.959 39.726 28.067 39.744 ;
     RECT  27.995 43.776 28.067 43.866 ;
     RECT  27.995 51.984 28.067 52.002 ;
    LAYER M3 ;
     RECT  2.415 2.143 2.505 2.413 ;
     RECT  7.815 2.143 7.905 2.413 ;
     RECT  13.215 2.143 13.305 2.413 ;
     RECT  18.615 2.143 18.705 2.413 ;
     RECT  24.015 2.143 24.105 2.413 ;
     RECT  24.015 2.413 24.297 6.781 ;
     RECT  26.748 6.859 26.766 6.955 ;
     RECT  26.712 6.955 26.766 7.045 ;
     RECT  26.712 7.045 26.802 7.147 ;
     RECT  25.992 7.147 26.802 7.195 ;
     RECT  25.704 7.195 26.802 7.243 ;
     RECT  25.704 7.243 27.342 7.339 ;
     RECT  24.015 6.781 24.894 7.393 ;
     RECT  23.976 7.393 24.894 7.435 ;
     RECT  25.704 7.339 27.99 7.435 ;
     RECT  0.18 7.435 0.198 7.465 ;
     RECT  0.18 7.465 0.342 7.531 ;
     RECT  2.415 2.413 2.697 7.579 ;
     RECT  3.6 7.435 3.618 7.579 ;
     RECT  0.18 7.531 0.378 7.627 ;
     RECT  3.6 7.579 3.798 7.627 ;
     RECT  4.752 7.591 4.77 7.627 ;
     RECT  7.815 2.413 8.097 7.627 ;
     RECT  3.6 7.627 4.77 7.655 ;
     RECT  4.14 7.655 4.77 7.661 ;
     RECT  7.815 7.627 9.054 7.663 ;
     RECT  13.215 2.413 13.497 7.663 ;
     RECT  1.728 7.579 2.697 7.723 ;
     RECT  23.976 7.435 27.99 7.735 ;
     RECT  0.108 7.627 0.378 7.757 ;
     RECT  7.815 7.663 9.198 7.771 ;
     RECT  7.815 7.771 9.378 7.799 ;
     RECT  1.728 7.723 2.79 7.819 ;
     RECT  1.728 7.819 2.898 7.867 ;
     RECT  1.152 7.867 2.898 7.889 ;
     RECT  4.14 7.661 4.626 7.889 ;
     RECT  4.14 7.889 4.41 7.925 ;
     RECT  7.056 7.579 7.074 7.925 ;
     RECT  0.108 7.757 0.342 7.949 ;
     RECT  7.815 7.799 8.622 8.011 ;
     RECT  4.14 7.925 4.374 8.195 ;
     RECT  9.36 7.799 9.378 8.443 ;
     RECT  7.092 8.011 8.622 8.465 ;
     RECT  0.108 7.949 0.198 8.588 ;
     RECT  7.092 8.465 8.586 8.683 ;
     RECT  9.36 8.443 9.414 8.731 ;
     RECT  1.152 7.889 2.862 8.735 ;
     RECT  0.144 8.588 0.162 8.765 ;
     RECT  6.948 8.683 8.586 8.779 ;
     RECT  6.84 8.779 8.586 8.909 ;
     RECT  4.14 8.195 4.158 8.971 ;
     RECT  3.708 8.971 4.158 9.067 ;
     RECT  22.788 8.707 22.806 9.085 ;
     RECT  16.236 8.401 16.254 9.121 ;
     RECT  20.052 8.275 20.07 9.149 ;
     RECT  15.552 9.121 16.254 9.239 ;
     RECT  9.36 8.731 9.702 9.259 ;
     RECT  9.36 9.259 10.134 9.355 ;
     RECT  13.215 7.663 14.022 9.391 ;
     RECT  0.108 9.451 0.126 9.499 ;
     RECT  15.408 9.391 15.498 9.509 ;
     RECT  15.408 9.509 15.426 9.545 ;
     RECT  3.708 9.067 4.842 9.547 ;
     RECT  22.788 9.085 22.842 9.625 ;
     RECT  1.152 8.735 2.697 9.661 ;
     RECT  0.108 9.499 0.198 9.739 ;
     RECT  1.152 9.661 2.826 9.815 ;
     RECT  3.708 9.547 5.238 9.835 ;
     RECT  23.976 7.735 28.062 9.859 ;
     RECT  1.728 9.815 2.826 9.883 ;
     RECT  3.672 9.835 5.238 9.883 ;
     RECT  18.615 2.413 18.897 9.883 ;
     RECT  7.092 8.909 8.586 9.931 ;
     RECT  0.108 9.739 0.342 9.976 ;
     RECT  17.892 9.883 19.098 10.075 ;
     RECT  16.236 9.239 16.254 10.123 ;
     RECT  17.208 10.075 19.098 10.123 ;
     RECT  22.788 9.625 22.95 10.165 ;
     RECT  16.236 10.123 19.098 10.171 ;
     RECT  22.788 10.165 23.094 10.471 ;
     RECT  23.868 9.859 28.062 10.471 ;
     RECT  16.236 10.171 19.386 10.705 ;
     RECT  21.024 10.471 21.042 10.705 ;
     RECT  22.788 10.471 28.062 10.705 ;
     RECT  20.808 10.705 21.042 10.895 ;
     RECT  1.728 9.883 5.238 10.939 ;
     RECT  0.072 9.976 0.342 10.987 ;
     RECT  22.752 10.705 28.062 11.039 ;
     RECT  6.84 9.931 8.586 11.173 ;
     RECT  9.36 9.355 10.638 11.173 ;
     RECT  0.072 10.987 0.846 11.275 ;
     RECT  1.728 10.939 5.454 11.275 ;
     RECT  13.215 9.391 14.634 11.281 ;
     RECT  6.84 11.173 10.638 11.371 ;
     RECT  21.456 10.987 21.69 11.371 ;
     RECT  22.752 11.039 28.026 11.371 ;
     RECT  12.6 11.281 14.634 11.399 ;
     RECT  12.456 11.509 12.474 11.549 ;
     RECT  21.456 11.371 28.026 11.707 ;
     RECT  21.132 11.707 28.026 11.785 ;
     RECT  21.132 11.785 28.062 11.821 ;
     RECT  11.88 11.899 11.898 11.939 ;
     RECT  13.215 11.399 14.634 12.281 ;
     RECT  16.236 10.705 19.494 12.901 ;
     RECT  14.832 12.829 14.85 12.929 ;
     RECT  16.128 12.901 19.962 12.991 ;
     RECT  16.128 12.991 20.142 13.171 ;
     RECT  20.88 11.821 28.062 13.171 ;
     RECT  16.128 13.171 28.062 13.289 ;
     RECT  13.215 12.281 14.022 13.369 ;
     RECT  0.072 11.275 5.454 13.567 ;
     RECT  12.384 12.289 12.402 13.603 ;
     RECT  6.84 11.371 10.962 13.945 ;
     RECT  6.624 13.945 10.962 14.179 ;
     RECT  13.215 13.369 14.562 14.251 ;
     RECT  13.215 14.251 15.03 14.369 ;
     RECT  6.48 14.179 10.962 14.449 ;
     RECT  16.128 13.289 20.142 14.485 ;
     RECT  20.88 13.289 28.062 14.485 ;
     RECT  13.215 14.369 14.886 14.513 ;
     RECT  16.128 14.485 28.062 14.755 ;
     RECT  13.215 14.513 14.85 14.783 ;
     RECT  16.092 14.755 28.062 15.061 ;
     RECT  0.036 13.567 5.454 15.547 ;
     RECT  6.336 14.449 10.962 15.547 ;
     RECT  12.384 13.603 12.438 15.565 ;
     RECT  16.02 15.061 28.062 15.727 ;
     RECT  12.276 15.565 12.438 15.763 ;
     RECT  11.7 15.763 12.438 15.961 ;
     RECT  13.215 14.783 14.742 15.961 ;
     RECT  15.84 15.727 28.062 16.033 ;
     RECT  11.7 15.961 14.742 16.105 ;
     RECT  15.696 16.033 28.062 16.105 ;
     RECT  0.036 15.547 10.962 17.083 ;
     RECT  11.7 16.105 28.062 17.083 ;
     RECT  0.036 17.083 28.062 17.117 ;
     RECT  0.036 17.117 0.558 18.283 ;
     RECT  1.404 17.117 28.062 18.283 ;
     RECT  0.036 18.283 28.062 18.725 ;
     RECT  0.108 18.725 28.062 18.797 ;
     RECT  0.108 18.797 0.558 19.181 ;
     RECT  1.44 18.797 28.062 19.409 ;
     RECT  0.54 19.181 0.558 19.643 ;
     RECT  0.324 20.011 0.342 20.059 ;
     RECT  1.44 19.409 28.026 20.155 ;
     RECT  1.152 20.155 28.026 20.525 ;
     RECT  0.144 20.059 0.342 20.875 ;
     RECT  0.108 20.875 0.342 20.909 ;
     RECT  1.44 20.525 28.026 21.355 ;
     RECT  1.368 21.355 28.026 21.451 ;
     RECT  0.108 20.909 0.27 21.581 ;
     RECT  1.152 21.451 28.026 21.581 ;
     RECT  0.144 21.581 0.27 21.643 ;
     RECT  0.144 21.643 0.342 21.835 ;
     RECT  0.144 21.835 0.414 22.013 ;
     RECT  0.144 22.013 0.342 22.253 ;
     RECT  0.288 22.253 0.342 22.541 ;
     RECT  1.404 21.581 28.026 22.919 ;
     RECT  0.288 22.541 0.306 23.629 ;
     RECT  0.288 23.629 0.558 23.701 ;
     RECT  1.404 22.919 27.162 23.701 ;
     RECT  0.288 23.701 27.162 23.899 ;
     RECT  0.216 23.899 27.162 23.927 ;
     RECT  27.972 22.919 28.026 24.043 ;
     RECT  0.216 23.927 0.558 24.077 ;
     RECT  27.9 24.043 28.026 24.089 ;
     RECT  1.404 23.927 27.162 24.139 ;
     RECT  27.9 24.089 27.99 24.139 ;
     RECT  0.216 24.077 0.234 24.235 ;
     RECT  0.144 24.235 0.234 24.475 ;
     RECT  0.108 24.475 0.234 24.557 ;
     RECT  0.324 24.811 0.342 24.941 ;
     RECT  1.404 24.139 27.99 25.277 ;
     RECT  0.144 25.291 0.162 25.661 ;
     RECT  1.44 25.277 27.99 25.979 ;
     RECT  1.44 25.979 27.342 26.669 ;
     RECT  26.244 26.669 27.342 26.699 ;
     RECT  26.28 26.699 27.342 26.731 ;
     RECT  0.108 26.347 0.126 27.139 ;
     RECT  0.108 27.139 0.522 27.211 ;
     RECT  0.108 27.211 0.558 27.437 ;
     RECT  1.44 26.669 25.398 27.499 ;
     RECT  26.28 26.731 27.99 27.499 ;
     RECT  0.108 27.437 0.522 28.013 ;
     RECT  0.144 28.013 0.522 28.291 ;
     RECT  0.144 28.291 0.558 28.589 ;
     RECT  1.44 27.499 27.99 28.589 ;
     RECT  1.44 28.589 27.954 28.685 ;
     RECT  0.144 28.589 0.378 28.939 ;
     RECT  27.936 28.685 27.954 29.057 ;
     RECT  0.108 28.939 0.378 29.323 ;
     RECT  1.44 28.685 26.802 29.461 ;
     RECT  1.44 29.461 26.838 29.995 ;
     RECT  0.108 29.323 0.414 30.109 ;
     RECT  1.44 29.995 27.342 30.379 ;
     RECT  0.108 30.109 0.558 30.605 ;
     RECT  1.44 30.379 27.99 30.893 ;
     RECT  1.44 30.893 25.794 31.117 ;
     RECT  0.108 30.605 0.198 31.339 ;
     RECT  0.108 31.339 0.342 31.469 ;
     RECT  26.748 30.893 27.99 31.693 ;
     RECT  26.712 31.693 27.99 32.141 ;
     RECT  0.108 31.469 0.27 32.233 ;
     RECT  1.26 31.117 25.794 32.233 ;
     RECT  26.748 32.141 27.99 32.333 ;
     RECT  26.784 32.333 27.99 32.459 ;
     RECT  0.108 32.233 25.794 32.467 ;
     RECT  26.784 32.459 26.802 32.525 ;
     RECT  0.036 32.467 25.794 32.765 ;
     RECT  0.036 32.765 25.506 32.801 ;
     RECT  0.036 32.801 25.146 32.957 ;
     RECT  27.648 32.459 27.99 33.071 ;
     RECT  0.036 32.957 0.342 33.293 ;
     RECT  27.648 33.071 27.918 33.437 ;
     RECT  0.036 33.293 0.27 33.581 ;
     RECT  26.244 33.241 26.262 33.581 ;
     RECT  27.36 33.655 27.378 33.691 ;
     RECT  1.152 32.957 25.146 33.961 ;
     RECT  1.116 33.961 25.146 34.123 ;
     RECT  26.784 33.691 27.378 34.157 ;
     RECT  1.116 34.123 25.686 34.349 ;
     RECT  0.036 33.581 0.162 34.357 ;
     RECT  0.036 34.357 0.378 34.465 ;
     RECT  1.116 34.349 25.11 34.465 ;
     RECT  27.828 34.507 27.918 34.795 ;
     RECT  26.784 34.157 26.802 34.987 ;
     RECT  0.036 34.465 25.11 35.117 ;
     RECT  26.748 34.987 26.802 35.131 ;
     RECT  27.828 34.795 27.99 35.131 ;
     RECT  26.748 35.131 27.99 35.179 ;
     RECT  0.036 35.117 25.074 35.693 ;
     RECT  0.036 35.693 0.558 36.041 ;
     RECT  1.368 35.693 25.074 36.194 ;
     RECT  1.44 36.194 25.074 36.211 ;
     RECT  1.44 36.211 25.578 36.481 ;
     RECT  1.44 36.481 25.65 36.589 ;
     RECT  26.676 35.179 27.99 36.589 ;
     RECT  0.108 36.041 0.558 36.845 ;
     RECT  1.44 36.589 27.99 37.769 ;
     RECT  1.476 37.769 27.99 37.814 ;
     RECT  0.108 36.845 0.198 38.093 ;
     RECT  1.476 37.814 27.846 38.273 ;
     RECT  1.476 38.273 27.81 38.309 ;
     RECT  1.476 38.309 27.342 38.821 ;
     RECT  0.108 38.093 0.162 39.019 ;
     RECT  0.108 39.019 0.522 39.091 ;
     RECT  1.404 38.821 27.342 39.091 ;
     RECT  0.108 39.091 0.558 39.437 ;
     RECT  1.404 39.091 27.378 39.499 ;
     RECT  0.108 39.437 0.486 39.629 ;
     RECT  1.404 39.499 27.99 39.721 ;
     RECT  0.108 39.629 0.342 40.369 ;
     RECT  0.108 40.369 0.558 40.397 ;
     RECT  0.18 40.397 0.558 41.377 ;
     RECT  0.108 41.377 0.558 41.419 ;
     RECT  1.404 39.721 28.062 41.419 ;
     RECT  0.108 41.419 28.062 41.549 ;
     RECT  0.108 41.549 0.558 41.791 ;
     RECT  0.036 41.791 0.558 42.317 ;
     RECT  1.404 41.549 28.062 43.069 ;
     RECT  0.036 42.317 0.342 43.609 ;
     RECT  1.26 43.069 28.062 43.609 ;
     RECT  0.036 43.609 28.062 43.949 ;
     RECT  0.036 43.949 0.342 44.429 ;
     RECT  0.036 44.429 0.306 45.833 ;
     RECT  0.072 45.833 0.306 46.309 ;
     RECT  1.152 43.949 28.062 46.309 ;
     RECT  0.072 46.309 28.062 46.679 ;
     RECT  5.292 46.679 28.062 46.769 ;
     RECT  5.328 46.769 28.062 46.925 ;
     RECT  5.364 46.925 28.062 47.759 ;
     RECT  5.364 47.759 20.286 47.849 ;
     RECT  0.072 46.679 4.554 47.857 ;
     RECT  15.444 47.849 20.286 47.885 ;
     RECT  0.036 47.857 4.554 48.475 ;
     RECT  5.364 47.849 14.598 48.475 ;
     RECT  0.036 48.475 14.598 48.667 ;
     RECT  15.444 47.885 20.142 48.667 ;
     RECT  0.036 48.667 20.142 48.929 ;
     RECT  0.036 48.929 5.238 48.941 ;
     RECT  1.152 48.941 5.238 48.965 ;
     RECT  6.048 48.929 20.142 49.003 ;
     RECT  21.096 47.759 28.062 49.003 ;
     RECT  6.048 49.003 28.062 49.199 ;
     RECT  15.444 49.199 28.062 49.565 ;
     RECT  1.152 48.965 4.554 49.613 ;
     RECT  1.512 49.613 4.554 49.709 ;
     RECT  20.628 49.565 28.062 49.775 ;
     RECT  20.736 49.775 28.062 50.009 ;
     RECT  1.98 49.709 4.554 50.189 ;
     RECT  7.2 49.199 14.562 50.251 ;
     RECT  6.84 50.251 14.562 50.381 ;
     RECT  15.444 49.565 19.818 50.459 ;
     RECT  0.036 48.941 0.414 50.549 ;
     RECT  2.052 50.189 4.554 50.861 ;
     RECT  15.66 50.459 19.818 50.909 ;
     RECT  2.304 50.861 4.554 51.359 ;
     RECT  0.108 50.549 0.414 51.403 ;
     RECT  0.108 51.403 0.558 51.437 ;
     RECT  19.656 50.909 19.818 51.883 ;
     RECT  20.772 50.009 28.062 51.883 ;
     RECT  19.656 51.883 28.062 52.007 ;
     RECT  19.656 52.007 27.99 52.016 ;
     RECT  0.144 51.437 0.558 52.061 ;
     RECT  7.2 50.381 14.562 52.079 ;
     RECT  0.216 52.061 0.558 52.109 ;
     RECT  7.815 52.079 14.562 52.241 ;
     RECT  19.656 52.016 27.954 52.439 ;
     RECT  0.396 52.109 0.558 52.519 ;
     RECT  6.048 49.199 6.066 52.555 ;
     RECT  7.815 52.241 11.898 52.583 ;
     RECT  0.396 52.519 1.17 52.619 ;
     RECT  7.815 52.583 9.99 52.619 ;
     RECT  2.304 51.359 4.266 52.795 ;
     RECT  6.048 52.555 6.822 52.889 ;
     RECT  9.036 52.619 9.99 52.889 ;
     RECT  2.196 52.795 4.266 52.906 ;
     RECT  11.16 52.583 11.898 52.979 ;
     RECT  2.088 52.906 4.266 53.123 ;
     RECT  20.772 52.439 27.954 53.131 ;
     RECT  20.772 53.131 27.99 53.168 ;
     RECT  9.9 52.889 9.99 53.249 ;
     RECT  19.656 52.439 19.818 53.261 ;
     RECT  0.396 52.619 0.558 53.491 ;
     RECT  0.108 53.491 0.558 53.741 ;
     RECT  9.9 53.249 9.918 54.059 ;
     RECT  20.772 53.168 27.81 54.095 ;
     RECT  2.268 53.123 4.266 54.103 ;
     RECT  15.66 50.909 18.897 54.139 ;
     RECT  19.656 53.261 19.782 54.139 ;
     RECT  2.232 54.103 4.266 54.203 ;
     RECT  15.66 54.139 19.782 54.239 ;
     RECT  12.816 52.241 14.562 54.437 ;
     RECT  0.108 53.741 0.522 54.481 ;
     RECT  23.436 54.095 27.81 54.481 ;
     RECT  23.436 54.481 27.954 54.635 ;
     RECT  20.772 54.095 22.698 54.701 ;
     RECT  0.108 54.481 0.558 54.797 ;
     RECT  6.804 54.751 6.822 54.869 ;
     RECT  11.304 52.979 11.898 54.877 ;
     RECT  23.472 54.635 27.954 54.905 ;
     RECT  2.304 54.203 4.266 54.941 ;
     RECT  10.836 54.877 11.898 54.977 ;
     RECT  12.816 54.437 13.554 54.977 ;
     RECT  21.564 54.701 22.698 54.977 ;
     RECT  10.908 54.977 11.898 55.049 ;
     RECT  15.66 54.239 18.897 55.049 ;
     RECT  0.108 54.797 0.342 55.085 ;
     RECT  2.304 54.941 4.086 55.139 ;
     RECT  23.616 54.905 27.954 55.277 ;
     RECT  23.616 55.277 27.414 55.283 ;
     RECT  16.92 55.049 18.897 55.319 ;
     RECT  18.036 55.319 18.897 55.409 ;
     RECT  0.324 55.085 0.342 55.469 ;
     RECT  15.66 55.049 16.11 55.481 ;
     RECT  2.304 55.139 3.798 55.525 ;
     RECT  23.724 55.283 27.414 55.565 ;
     RECT  22.176 54.977 22.698 55.759 ;
     RECT  15.66 55.481 15.786 56.021 ;
     RECT  2.268 55.525 3.798 56.029 ;
     RECT  11.592 55.049 11.898 56.057 ;
     RECT  2.268 56.029 3.834 56.093 ;
     RECT  18.108 55.409 18.897 56.093 ;
     RECT  22.176 55.759 22.842 56.101 ;
     RECT  23.724 55.565 27.342 56.101 ;
     RECT  11.88 56.057 11.898 56.129 ;
     RECT  22.176 56.101 27.342 56.203 ;
     RECT  20.772 54.701 20.79 56.237 ;
     RECT  22.104 56.203 27.342 56.251 ;
     RECT  0.108 55.993 0.162 56.285 ;
     RECT  21.996 56.251 27.342 56.347 ;
     RECT  21.996 56.347 27.918 56.371 ;
     RECT  2.268 56.093 3.762 56.381 ;
     RECT  21.996 56.371 27.99 56.381 ;
     RECT  22.176 56.381 27.99 56.429 ;
     RECT  18.615 56.093 18.897 56.533 ;
     RECT  19.656 54.239 19.782 56.533 ;
     RECT  18.615 56.533 19.782 56.561 ;
     RECT  22.176 56.429 27.414 56.561 ;
     RECT  0.108 56.285 0.126 56.621 ;
     RECT  18.615 56.561 19.674 56.633 ;
     RECT  25.524 56.561 27.414 56.633 ;
     RECT  6.048 52.889 6.066 56.641 ;
     RECT  6.804 56.605 6.822 56.641 ;
     RECT  19.656 56.633 19.674 56.669 ;
     RECT  26.244 56.633 27.414 56.669 ;
     RECT  6.048 56.641 6.822 56.759 ;
     RECT  6.804 56.759 6.822 56.831 ;
     RECT  12.816 54.977 13.497 57.029 ;
     RECT  16.92 55.319 16.938 57.173 ;
     RECT  2.304 56.381 3.762 57.181 ;
     RECT  14.472 54.437 14.562 57.209 ;
     RECT  2.304 57.181 3.978 57.299 ;
     RECT  26.496 56.669 27.414 57.389 ;
     RECT  0.144 57.259 0.162 57.437 ;
     RECT  22.176 56.561 24.786 57.451 ;
     RECT  14.544 57.209 14.562 57.479 ;
     RECT  27.252 57.389 27.414 57.485 ;
     RECT  2.304 57.299 3.762 57.547 ;
     RECT  2.268 57.547 3.762 57.569 ;
     RECT  22.176 57.451 24.894 57.569 ;
     RECT  22.212 57.569 24.894 57.685 ;
     RECT  22.212 57.685 25.362 57.721 ;
     RECT  2.268 57.569 3.618 57.725 ;
     RECT  2.268 57.725 3.114 57.839 ;
     RECT  15.66 56.021 15.678 57.839 ;
     RECT  20.196 57.931 20.214 57.979 ;
     RECT  17.712 57.931 17.73 57.991 ;
     RECT  6.048 56.759 6.066 58.019 ;
     RECT  21.312 57.685 21.33 58.019 ;
     RECT  17.712 57.991 17.874 58.109 ;
     RECT  20.196 57.979 20.358 58.109 ;
     RECT  22.212 57.721 25.578 58.109 ;
     RECT  27.252 57.485 27.342 58.109 ;
     RECT  22.824 58.109 25.578 58.145 ;
     RECT  22.824 58.145 25.362 58.379 ;
     RECT  27.252 58.109 27.27 58.379 ;
     RECT  2.268 57.839 2.826 58.415 ;
     RECT  2.304 58.415 2.826 58.919 ;
     RECT  23.184 58.379 25.362 58.919 ;
     RECT  2.304 58.919 2.697 59.225 ;
     RECT  22.32 59.431 22.338 59.503 ;
     RECT  23.184 58.919 25.182 59.503 ;
     RECT  22.32 59.503 25.182 59.603 ;
     RECT  23.976 59.603 25.182 59.729 ;
     RECT  23.976 59.729 25.146 59.837 ;
     RECT  22.32 59.603 23.202 60.241 ;
     RECT  22.284 60.241 23.202 60.269 ;
     RECT  18.615 56.633 18.897 60.475 ;
     RECT  13.215 57.029 13.497 60.523 ;
     RECT  9.036 52.889 9.054 60.539 ;
     RECT  20.196 58.109 20.214 60.539 ;
     RECT  23.976 59.837 25.11 60.539 ;
     RECT  22.284 60.269 23.094 60.557 ;
     RECT  13.104 60.523 13.497 60.575 ;
     RECT  18.615 60.475 18.954 60.575 ;
     RECT  22.284 60.557 22.95 60.989 ;
     RECT  22.284 60.989 22.806 61.079 ;
     RECT  22.32 61.079 22.806 61.349 ;
     RECT  24.015 60.539 25.11 61.349 ;
     RECT  22.32 61.349 22.374 61.421 ;
     RECT  22.356 61.421 22.374 61.619 ;
     RECT  26.496 57.389 26.514 61.619 ;
     RECT  21.42 61.579 21.438 61.627 ;
     RECT  21.42 61.627 21.582 61.655 ;
     RECT  24.015 61.349 24.714 61.655 ;
     RECT  21.564 61.655 21.582 61.664 ;
     RECT  2.415 59.225 2.697 62.387 ;
     RECT  7.815 52.619 8.097 62.387 ;
     RECT  13.215 60.575 13.497 62.387 ;
     RECT  18.615 60.575 18.897 62.387 ;
     RECT  24.015 61.655 24.297 62.387 ;
     RECT  2.415 62.387 2.505 62.657 ;
     RECT  7.815 62.387 7.905 62.657 ;
     RECT  13.215 62.387 13.305 62.657 ;
     RECT  18.615 62.387 18.705 62.657 ;
     RECT  24.015 62.387 24.105 62.657 ;
    LAYER M4 ;
     RECT  0.06 7.248 0.133 57.864 ;
     RECT  0.133 7.248 0.323 58.776 ;
     RECT  0.323 7.44 2.408 58.776 ;
     RECT  2.408 2.148 2.512 62.652 ;
     RECT  2.512 2.418 2.704 62.382 ;
     RECT  2.704 46.08 2.765 50.664 ;
     RECT  2.704 53.04 2.819 58.968 ;
     RECT  2.819 58.944 2.867 58.968 ;
     RECT  2.819 53.04 2.873 57.72 ;
     RECT  2.704 12.768 2.909 45.048 ;
     RECT  2.909 12.768 2.915 16.392 ;
     RECT  2.873 53.04 2.945 56.52 ;
     RECT  2.704 51.696 2.981 52.008 ;
     RECT  2.915 13.104 3.011 16.392 ;
     RECT  2.909 17.376 3.233 45.048 ;
     RECT  2.945 53.04 3.385 56.472 ;
     RECT  2.765 46.08 3.413 48.504 ;
     RECT  2.981 51.984 3.413 52.008 ;
     RECT  3.413 46.08 3.521 47.688 ;
     RECT  2.704 7.44 3.629 11.496 ;
     RECT  2.873 57.696 3.629 57.72 ;
     RECT  3.385 55.296 3.683 56.472 ;
     RECT  3.683 56.064 3.731 56.472 ;
     RECT  3.521 46.08 3.737 47.448 ;
     RECT  3.737 47.28 3.773 47.448 ;
     RECT  3.385 53.04 3.809 54.216 ;
     RECT  3.233 20.064 3.841 45.048 ;
     RECT  3.737 46.08 3.841 46.2 ;
     RECT  3.731 56.064 3.845 56.088 ;
     RECT  2.765 49.584 3.913 50.664 ;
     RECT  3.809 53.04 3.971 54.168 ;
     RECT  3.629 7.584 4.021 11.496 ;
     RECT  3.971 53.04 4.105 54.072 ;
     RECT  3.841 20.064 4.421 46.2 ;
     RECT  3.233 17.376 4.493 19.032 ;
     RECT  4.421 20.064 4.493 45.048 ;
     RECT  4.493 20.4 4.565 45.048 ;
     RECT  4.565 20.64 5.171 45.048 ;
     RECT  5.209 48.48 5.221 48.504 ;
     RECT  4.021 7.584 5.249 11.736 ;
     RECT  4.421 46.08 5.249 46.2 ;
     RECT  3.773 47.28 5.269 47.304 ;
     RECT  3.011 13.296 5.285 16.392 ;
     RECT  5.269 46.896 5.315 47.304 ;
     RECT  5.221 48.48 5.315 48.6 ;
     RECT  5.315 46.896 5.357 46.92 ;
     RECT  5.315 48.576 5.393 48.6 ;
     RECT  5.171 20.64 5.429 44.328 ;
     RECT  5.285 13.296 5.681 16.296 ;
     RECT  4.493 17.376 5.789 18.744 ;
     RECT  5.429 20.64 5.795 44.232 ;
     RECT  5.795 24.72 5.897 44.232 ;
     RECT  5.897 32.88 6.113 44.232 ;
     RECT  5.795 20.64 6.145 23.736 ;
     RECT  6.145 20.304 6.433 23.736 ;
     RECT  5.897 24.72 6.581 31.896 ;
     RECT  5.681 13.296 6.833 15.864 ;
     RECT  6.113 33.024 6.833 44.232 ;
     RECT  6.433 19.92 6.901 23.736 ;
     RECT  6.581 24.72 6.901 31.8 ;
     RECT  6.901 19.92 7.117 31.8 ;
     RECT  5.789 18.72 7.369 18.744 ;
     RECT  7.117 19.872 7.369 31.8 ;
     RECT  7.369 18.72 7.669 31.8 ;
     RECT  6.833 33.024 7.669 44.088 ;
     RECT  6.833 13.296 7.765 15.624 ;
     RECT  5.249 7.584 7.808 9.384 ;
     RECT  5.249 10.464 7.808 11.736 ;
     RECT  7.765 13.056 7.808 15.624 ;
     RECT  5.789 17.376 7.808 17.4 ;
     RECT  7.669 18.72 7.808 44.088 ;
     RECT  5.989 45.696 7.808 45.72 ;
     RECT  6.577 46.896 7.808 46.92 ;
     RECT  3.913 49.584 7.808 50.856 ;
     RECT  4.105 53.28 7.808 54.072 ;
     RECT  6.469 60.528 7.808 60.552 ;
     RECT  7.808 2.148 7.912 62.652 ;
     RECT  7.912 2.418 8.104 62.382 ;
     RECT  8.104 23.616 8.201 44.088 ;
     RECT  8.104 21.696 8.741 22.248 ;
     RECT  8.104 13.056 8.819 15.24 ;
     RECT  8.104 7.632 9.065 10.056 ;
     RECT  8.201 24.672 9.137 44.088 ;
     RECT  8.104 53.28 9.349 54.072 ;
     RECT  9.065 8.448 9.425 10.056 ;
     RECT  8.104 45.696 9.445 46.92 ;
     RECT  8.201 23.616 9.493 23.64 ;
     RECT  9.137 24.672 9.493 40.152 ;
     RECT  9.425 8.736 9.713 10.056 ;
     RECT  8.104 17.376 9.745 17.4 ;
     RECT  8.104 18.72 9.973 20.664 ;
     RECT  8.741 21.696 9.973 21.72 ;
     RECT  9.137 41.424 10.105 44.088 ;
     RECT  9.713 9.264 10.145 10.056 ;
     RECT  9.493 23.616 10.465 40.152 ;
     RECT  10.105 41.184 10.465 44.088 ;
     RECT  10.145 9.36 10.649 10.056 ;
     RECT  10.465 23.616 10.861 44.088 ;
     RECT  9.973 18.72 10.969 21.72 ;
     RECT  9.745 17.376 11.005 17.496 ;
     RECT  10.861 22.848 11.441 44.088 ;
     RECT  11.441 38.64 11.449 40.632 ;
     RECT  11.441 22.848 11.581 37.608 ;
     RECT  8.104 11.712 11.869 11.736 ;
     RECT  11.005 17.088 11.905 17.496 ;
     RECT  10.969 18.528 11.905 21.72 ;
     RECT  11.905 17.088 12.049 21.72 ;
     RECT  9.349 53.28 12.277 55.032 ;
     RECT  12.049 16.848 12.301 21.72 ;
     RECT  11.869 11.712 12.428 11.928 ;
     RECT  11.581 22.752 12.553 37.608 ;
     RECT  11.449 38.688 12.553 40.632 ;
     RECT  11.689 47.952 12.625 47.976 ;
     RECT  12.301 16.464 12.709 21.72 ;
     RECT  12.553 22.752 12.709 40.632 ;
     RECT  11.441 41.952 12.757 44.088 ;
     RECT  12.709 16.464 12.805 40.632 ;
     RECT  12.757 41.952 12.805 44.136 ;
     RECT  12.805 16.464 13.165 44.136 ;
     RECT  9.445 45.168 13.165 46.92 ;
     RECT  10.649 10.032 13.208 10.056 ;
     RECT  12.428 11.52 13.208 11.928 ;
     RECT  8.819 13.296 13.208 15.24 ;
     RECT  13.165 16.464 13.208 46.92 ;
     RECT  12.625 47.904 13.208 47.976 ;
     RECT  8.104 49.584 13.208 50.856 ;
     RECT  12.277 53.28 13.208 55.56 ;
     RECT  8.104 57.984 13.208 58.008 ;
     RECT  8.104 60.528 13.208 60.552 ;
     RECT  13.208 2.148 13.312 62.652 ;
     RECT  13.312 2.418 13.504 62.382 ;
     RECT  13.504 16.512 14.213 47.976 ;
     RECT  14.213 16.512 14.257 47.352 ;
     RECT  13.504 13.296 14.531 14.712 ;
     RECT  14.257 16.512 14.677 46.92 ;
     RECT  14.677 15.984 14.717 46.92 ;
     RECT  13.504 11.712 14.725 11.736 ;
     RECT  13.504 9.408 14.771 10.056 ;
     RECT  14.717 15.984 14.771 16.008 ;
     RECT  14.717 17.376 14.861 46.92 ;
     RECT  14.861 22.176 14.933 46.92 ;
     RECT  14.933 40.896 15.077 46.92 ;
     RECT  13.504 49.584 15.107 50.856 ;
     RECT  14.861 17.376 15.329 20.712 ;
     RECT  15.329 17.376 15.689 20.664 ;
     RECT  14.933 22.176 15.829 39.768 ;
     RECT  15.829 21.648 16.013 39.768 ;
     RECT  15.077 41.184 16.117 46.92 ;
     RECT  14.771 10.032 16.259 10.056 ;
     RECT  15.689 17.376 16.307 19.512 ;
     RECT  16.013 24.672 16.477 39.768 ;
     RECT  15.107 49.584 16.477 49.608 ;
     RECT  15.107 50.832 16.477 50.856 ;
     RECT  16.477 24.672 16.621 39.864 ;
     RECT  16.117 40.992 16.621 46.92 ;
     RECT  16.307 18.096 16.841 19.512 ;
     RECT  15.685 48.384 17.233 48.408 ;
     RECT  16.477 49.584 17.233 51.384 ;
     RECT  16.801 10.08 17.341 10.152 ;
     RECT  13.504 53.28 17.363 55.56 ;
     RECT  16.013 21.648 17.629 23.64 ;
     RECT  16.621 24.672 17.629 46.92 ;
     RECT  13.504 57.984 17.701 58.008 ;
     RECT  17.341 10.08 17.881 10.68 ;
     RECT  17.881 9.888 18.097 10.68 ;
     RECT  14.725 11.664 18.097 11.736 ;
     RECT  17.233 48.384 18.428 51.384 ;
     RECT  18.097 9.888 18.608 11.736 ;
     RECT  14.531 13.296 18.608 14.664 ;
     RECT  18.061 17.088 18.608 17.112 ;
     RECT  16.841 18.672 18.608 19.512 ;
     RECT  15.689 20.64 18.608 20.664 ;
     RECT  17.629 21.648 18.608 46.92 ;
     RECT  18.428 48.288 18.608 51.384 ;
     RECT  17.363 54.048 18.608 55.56 ;
     RECT  17.701 57.936 18.608 58.008 ;
     RECT  13.504 60.528 18.608 60.552 ;
     RECT  18.608 2.148 18.712 62.652 ;
     RECT  18.712 2.418 18.904 62.382 ;
     RECT  18.904 60.48 19.043 60.552 ;
     RECT  18.904 9.888 19.109 10.728 ;
     RECT  18.904 17.088 19.909 19.512 ;
     RECT  19.909 16.56 19.937 19.512 ;
     RECT  19.937 17.616 19.969 19.512 ;
     RECT  18.904 20.64 19.969 20.664 ;
     RECT  18.904 48.384 20.101 51.384 ;
     RECT  18.904 12.912 20.147 14.664 ;
     RECT  18.904 22.464 20.149 47.352 ;
     RECT  20.101 48.384 20.185 51.912 ;
     RECT  18.904 53.232 20.185 55.56 ;
     RECT  19.937 16.56 20.252 16.584 ;
     RECT  20.252 16.464 20.339 16.584 ;
     RECT  20.185 48.384 20.369 55.56 ;
     RECT  18.904 57.936 20.369 58.008 ;
     RECT  20.149 21.84 20.473 47.352 ;
     RECT  20.369 48.384 20.473 51.384 ;
     RECT  19.969 17.616 20.621 20.664 ;
     RECT  20.369 52.368 20.761 55.56 ;
     RECT  20.147 12.912 20.867 14.376 ;
     RECT  20.339 16.56 20.941 16.584 ;
     RECT  20.621 17.616 20.941 17.64 ;
     RECT  20.473 21.84 20.941 51.384 ;
     RECT  20.621 18.768 20.989 20.664 ;
     RECT  20.761 52.368 21.011 56.232 ;
     RECT  21.011 53.232 21.013 56.232 ;
     RECT  20.989 19.392 21.049 20.664 ;
     RECT  20.941 21.744 21.049 51.384 ;
     RECT  20.369 57.936 21.059 57.96 ;
     RECT  20.941 16.56 21.269 17.64 ;
     RECT  18.904 61.584 21.301 61.608 ;
     RECT  19.043 60.528 21.445 60.552 ;
     RECT  21.301 61.584 21.445 61.656 ;
     RECT  21.013 53.232 21.491 56.376 ;
     RECT  21.049 19.392 21.557 51.384 ;
     RECT  21.557 44.208 21.587 51.384 ;
     RECT  21.445 60.528 21.593 61.656 ;
     RECT  19.109 10.032 21.661 10.728 ;
     RECT  21.121 11.712 21.661 11.736 ;
     RECT  21.557 19.392 21.881 43.224 ;
     RECT  21.587 44.208 21.917 45.288 ;
     RECT  21.269 17.424 22.021 17.64 ;
     RECT  21.587 46.32 22.025 51.384 ;
     RECT  20.867 12.912 22.205 12.936 ;
     RECT  21.881 21.696 22.529 43.224 ;
     RECT  21.881 19.392 22.565 20.664 ;
     RECT  20.867 14.352 22.637 14.376 ;
     RECT  22.021 17.424 22.645 17.736 ;
     RECT  21.917 44.448 22.777 45.288 ;
     RECT  21.593 60.528 22.961 60.984 ;
     RECT  21.491 54.384 23.101 56.376 ;
     RECT  21.491 53.232 23.137 53.256 ;
     RECT  23.137 53.232 23.209 53.352 ;
     RECT  22.529 30.672 23.353 43.224 ;
     RECT  23.101 54.384 23.365 56.424 ;
     RECT  22.645 17.424 23.509 17.928 ;
     RECT  22.565 20.064 23.533 20.664 ;
     RECT  23.533 19.728 23.569 20.664 ;
     RECT  22.529 21.696 23.569 29.64 ;
     RECT  23.353 30.672 23.653 43.368 ;
     RECT  22.777 44.448 23.653 45.528 ;
     RECT  23.509 17.424 23.785 18.168 ;
     RECT  21.661 10.032 24.008 11.736 ;
     RECT  22.849 15.984 24.008 16.008 ;
     RECT  23.785 17.136 24.008 18.168 ;
     RECT  23.569 19.728 24.008 29.64 ;
     RECT  23.653 30.672 24.008 45.528 ;
     RECT  22.025 46.56 24.008 51.384 ;
     RECT  23.209 52.8 24.008 53.352 ;
     RECT  23.365 54.384 24.008 57.048 ;
     RECT  22.961 60.528 24.008 60.552 ;
     RECT  24.008 2.148 24.112 62.652 ;
     RECT  24.112 2.418 24.304 62.382 ;
     RECT  24.304 14.064 24.419 29.304 ;
     RECT  24.419 15.84 24.515 29.304 ;
     RECT  24.515 15.84 24.652 29.256 ;
     RECT  24.304 56.352 24.689 57 ;
     RECT  24.419 14.064 25.405 14.472 ;
     RECT  24.304 31.056 25.409 53.352 ;
     RECT  24.652 15.984 25.585 29.256 ;
     RECT  24.304 8.592 25.657 8.616 ;
     RECT  24.304 10.032 25.657 11.976 ;
     RECT  25.405 13.296 25.657 14.472 ;
     RECT  25.477 7.44 25.693 7.464 ;
     RECT  25.657 8.592 25.693 11.976 ;
     RECT  25.657 13.296 25.693 14.856 ;
     RECT  25.585 15.984 25.693 29.448 ;
     RECT  25.693 7.44 25.729 11.976 ;
     RECT  25.693 13.296 25.729 29.448 ;
     RECT  25.409 31.056 25.765 46.344 ;
     RECT  25.409 47.376 25.765 53.352 ;
     RECT  24.304 54.384 25.765 54.408 ;
     RECT  24.689 56.352 25.765 56.712 ;
     RECT  25.765 47.376 25.945 54.6 ;
     RECT  25.729 7.44 25.981 29.448 ;
     RECT  25.981 7.152 26.125 29.448 ;
     RECT  25.765 30.48 26.125 46.344 ;
     RECT  25.765 55.92 26.161 56.712 ;
     RECT  25.945 47.376 26.197 54.696 ;
     RECT  26.161 55.824 26.197 56.712 ;
     RECT  26.197 47.376 26.485 56.712 ;
     RECT  26.125 7.152 26.701 46.344 ;
     RECT  26.701 6.96 26.737 46.344 ;
     RECT  26.485 47.376 26.737 57.192 ;
     RECT  26.737 6.864 26.773 57.192 ;
     RECT  26.773 6.864 27.385 57.384 ;
     RECT  27.385 6.864 28.044 57.48 ;
    LAYER M5 ;
     RECT  2.4 2.137 2.52 2.151 ;
     RECT  7.8 2.137 7.92 2.151 ;
     RECT  13.2 2.137 13.32 2.151 ;
     RECT  18.6 2.137 18.72 2.151 ;
     RECT  24 2.137 24.12 2.151 ;
     RECT  0.288 7.237 0.312 7.333 ;
     RECT  0.24 7.333 0.312 7.475 ;
     RECT  0.24 7.475 0.264 7.573 ;
     RECT  0.192 7.573 0.264 7.715 ;
     RECT  0.192 7.715 0.216 7.955 ;
     RECT  0.144 9.685 0.168 9.875 ;
     RECT  0.192 10.357 0.216 10.739 ;
     RECT  0.144 10.933 0.168 11.219 ;
     RECT  13.2 2.151 13.512 11.509 ;
     RECT  0.192 11.845 0.264 12.037 ;
     RECT  0.192 12.037 0.312 12.421 ;
     RECT  2.4 2.151 2.712 12.757 ;
     RECT  2.4 12.757 2.904 12.805 ;
     RECT  2.112 12.805 2.904 13.043 ;
     RECT  7.8 2.151 8.112 13.045 ;
     RECT  2.304 13.043 2.904 13.093 ;
     RECT  20.496 12.901 20.52 13.285 ;
     RECT  0.192 12.421 0.552 13.621 ;
     RECT  7.8 13.045 8.808 13.621 ;
     RECT  20.496 13.285 20.76 13.813 ;
     RECT  20.496 13.813 20.856 14.341 ;
     RECT  0.144 13.621 0.552 14.531 ;
     RECT  20.304 14.341 20.856 14.629 ;
     RECT  14.736 9.397 14.76 14.677 ;
     RECT  2.304 13.093 3 14.773 ;
     RECT  4.032 11.701 4.968 14.773 ;
     RECT  0.144 14.531 0.408 14.867 ;
     RECT  24 2.151 24.312 14.917 ;
     RECT  0.144 14.867 0.36 15.059 ;
     RECT  0.144 15.059 0.264 15.443 ;
     RECT  24 14.917 24.408 15.829 ;
     RECT  14.496 14.677 14.76 16.019 ;
     RECT  12.48 11.509 13.512 16.499 ;
     RECT  12.672 16.499 13.512 16.501 ;
     RECT  14.496 16.019 14.52 16.501 ;
     RECT  20.112 14.629 20.856 16.549 ;
     RECT  0.144 15.443 0.168 16.933 ;
     RECT  18.6 2.151 18.912 17.077 ;
     RECT  19.92 16.549 20.856 17.077 ;
     RECT  0.144 16.933 0.216 17.123 ;
     RECT  16.224 10.021 16.248 17.365 ;
     RECT  24 15.829 24.6 17.461 ;
     RECT  23.184 17.461 24.6 17.893 ;
     RECT  16.224 17.365 16.296 18.133 ;
     RECT  0.192 17.123 0.216 18.275 ;
     RECT  12.672 16.501 14.52 18.277 ;
     RECT  12.528 18.277 14.52 18.757 ;
     RECT  15.6 18.133 16.296 18.757 ;
     RECT  18.6 17.077 20.856 18.757 ;
     RECT  26.88 18.613 26.904 18.803 ;
     RECT  18.6 18.757 20.952 19.477 ;
     RECT  12.528 18.757 16.296 19.573 ;
     RECT  7.8 13.621 9.48 19.861 ;
     RECT  0.24 19.333 0.264 19.909 ;
     RECT  6 15.349 6.024 19.909 ;
     RECT  12.288 19.573 16.296 20.003 ;
     RECT  0.24 19.909 0.312 20.675 ;
     RECT  0.288 20.675 0.312 20.771 ;
     RECT  0.24 21.685 0.264 21.925 ;
     RECT  27.888 21.829 27.912 22.115 ;
     RECT  2.304 14.773 4.968 22.453 ;
     RECT  0.192 21.925 0.264 22.501 ;
     RECT  0.144 22.501 0.264 22.691 ;
     RECT  12.288 20.003 14.52 22.789 ;
     RECT  15.6 20.003 16.296 22.789 ;
     RECT  18.6 19.477 21.336 22.837 ;
     RECT  0.24 22.691 0.264 22.931 ;
     RECT  2.112 22.453 4.968 23.173 ;
     RECT  6 19.909 6.504 23.173 ;
     RECT  2.112 23.173 6.504 23.269 ;
     RECT  7.8 19.861 10.056 23.269 ;
     RECT  2.112 23.269 10.056 23.317 ;
     RECT  12.288 22.789 16.296 23.317 ;
     RECT  11.808 23.317 16.296 23.555 ;
     RECT  22.656 17.893 24.6 23.653 ;
     RECT  2.064 23.317 10.056 23.795 ;
     RECT  0.144 23.701 0.168 23.891 ;
     RECT  22.656 23.653 24.696 23.891 ;
     RECT  11.808 23.555 14.52 24.083 ;
     RECT  15.6 23.555 16.296 24.661 ;
     RECT  12.288 24.083 14.52 25.045 ;
     RECT  0.144 24.901 0.168 25.091 ;
     RECT  7.8 23.795 10.056 25.093 ;
     RECT  15.6 24.661 16.872 25.093 ;
     RECT  17.904 22.837 21.336 25.093 ;
     RECT  7.8 25.093 10.776 25.141 ;
     RECT  7.8 25.141 10.872 25.283 ;
     RECT  11.952 25.045 14.52 25.717 ;
     RECT  15.6 25.093 21.336 25.717 ;
     RECT  11.952 25.717 21.336 25.861 ;
     RECT  22.656 23.891 24.6 25.861 ;
     RECT  11.952 25.861 24.6 26.531 ;
     RECT  25.68 16.549 25.704 27.107 ;
     RECT  12.288 26.531 24.6 27.731 ;
     RECT  12.288 27.731 21.768 28.021 ;
     RECT  12.048 28.021 21.768 28.307 ;
     RECT  2.064 23.795 6.504 28.357 ;
     RECT  7.8 25.283 10.056 28.357 ;
     RECT  2.064 28.357 10.056 28.453 ;
     RECT  2.064 28.453 10.824 28.741 ;
     RECT  0.192 28.405 0.216 28.885 ;
     RECT  2.064 28.741 11.256 29.027 ;
     RECT  12.288 28.307 21.768 29.221 ;
     RECT  23.088 27.731 24.6 29.221 ;
     RECT  0.192 28.885 0.312 29.363 ;
     RECT  0.192 29.363 0.216 29.557 ;
     RECT  12.288 29.221 24.6 29.747 ;
     RECT  0.144 29.557 0.216 29.939 ;
     RECT  2.064 29.027 10.824 29.989 ;
     RECT  2.064 29.989 11.112 30.275 ;
     RECT  2.064 30.275 10.056 31.283 ;
     RECT  7.68 31.283 10.056 32.195 ;
     RECT  23.088 29.747 24.6 32.533 ;
     RECT  23.088 32.533 25.032 32.869 ;
     RECT  23.088 32.869 25.704 33.059 ;
     RECT  12.288 29.747 22.056 33.061 ;
     RECT  23.088 33.059 24.6 33.061 ;
     RECT  11.088 30.275 11.112 33.157 ;
     RECT  12.288 33.061 24.6 33.251 ;
     RECT  11.04 33.157 11.112 33.299 ;
     RECT  11.04 33.299 11.064 33.443 ;
     RECT  19.92 33.251 24.6 34.259 ;
     RECT  12.288 33.251 18.912 34.741 ;
     RECT  19.92 34.259 21.624 34.741 ;
     RECT  25.68 33.059 25.704 34.885 ;
     RECT  0.144 29.939 0.168 34.981 ;
     RECT  0.144 34.981 0.216 35.221 ;
     RECT  0.144 35.221 0.36 35.411 ;
     RECT  22.752 34.259 24.6 35.605 ;
     RECT  12.288 34.741 21.624 36.325 ;
     RECT  22.704 35.605 24.6 36.325 ;
     RECT  12.288 36.325 24.6 36.515 ;
     RECT  12.288 36.515 21.336 36.803 ;
     RECT  0.144 35.411 0.264 36.949 ;
     RECT  7.8 32.195 10.056 36.949 ;
     RECT  7.536 36.949 11.016 36.997 ;
     RECT  2.064 31.283 6.504 37.093 ;
     RECT  7.536 36.997 11.112 37.093 ;
     RECT  2.064 37.093 11.112 37.139 ;
     RECT  22.512 36.515 24.6 37.141 ;
     RECT  25.584 34.885 25.704 37.141 ;
     RECT  11.088 37.139 11.112 37.187 ;
     RECT  22.512 37.141 25.704 37.187 ;
     RECT  12.288 36.803 16.344 37.237 ;
     RECT  23.088 37.187 25.704 37.619 ;
     RECT  2.112 37.139 10.056 37.667 ;
     RECT  0.144 36.949 0.408 37.715 ;
     RECT  0.144 37.715 0.36 37.811 ;
     RECT  27.84 37.333 27.864 38.341 ;
     RECT  27.84 38.341 27.96 38.387 ;
     RECT  11.376 37.237 16.344 38.675 ;
     RECT  0.192 37.811 0.36 38.677 ;
     RECT  2.16 37.667 6.504 38.677 ;
     RECT  7.8 37.667 10.056 38.677 ;
     RECT  23.088 37.619 24.6 38.677 ;
     RECT  17.328 36.803 21.336 38.725 ;
     RECT  2.16 38.677 10.056 38.819 ;
     RECT  0.192 38.677 0.408 38.821 ;
     RECT  0.144 38.821 0.408 39.059 ;
     RECT  2.208 38.819 10.056 39.251 ;
     RECT  0.144 39.059 0.312 39.395 ;
     RECT  0.24 39.395 0.312 40.067 ;
     RECT  2.256 39.251 10.056 40.211 ;
     RECT  0.288 40.067 0.312 40.595 ;
     RECT  22.56 38.677 24.6 40.981 ;
     RECT  25.584 37.619 25.704 40.981 ;
     RECT  2.256 40.211 6.504 41.219 ;
     RECT  7.8 40.211 10.056 41.413 ;
     RECT  22.56 40.981 25.704 41.653 ;
     RECT  22.56 41.653 26.664 41.797 ;
     RECT  27.936 38.387 27.96 41.797 ;
     RECT  12.288 38.675 16.344 42.085 ;
     RECT  17.328 38.725 21.576 42.085 ;
     RECT  7.8 41.413 10.248 42.227 ;
     RECT  12.288 42.085 21.576 42.227 ;
     RECT  17.328 42.227 21.576 42.467 ;
     RECT  22.56 41.797 27.96 43.187 ;
     RECT  2.304 41.219 6.504 43.381 ;
     RECT  22.56 43.187 27.384 43.427 ;
     RECT  2.208 43.381 6.504 43.859 ;
     RECT  2.304 43.859 6.504 45.059 ;
     RECT  22.56 43.427 26.664 45.059 ;
     RECT  18.6 42.467 21.576 45.587 ;
     RECT  2.304 45.059 4.2 45.635 ;
     RECT  5.232 45.059 6.504 45.731 ;
     RECT  22.56 45.059 24.936 46.787 ;
     RECT  5.232 45.731 5.256 46.885 ;
     RECT  18.6 45.587 21.48 47.363 ;
     RECT  18.6 47.363 18.912 48.277 ;
     RECT  12.288 42.227 16.344 48.419 ;
     RECT  5.232 46.885 5.304 48.515 ;
     RECT  5.232 48.515 5.256 48.611 ;
     RECT  20.112 47.363 21.48 49.043 ;
     RECT  18.48 48.277 18.912 49.235 ;
     RECT  2.304 45.635 4.056 49.619 ;
     RECT  20.112 49.043 20.232 50.101 ;
     RECT  21.312 49.043 21.48 50.101 ;
     RECT  12.288 48.419 15.144 50.579 ;
     RECT  23.088 46.787 24.312 50.867 ;
     RECT  0.288 50.581 0.312 51.733 ;
     RECT  26.448 45.059 26.664 51.827 ;
     RECT  20.112 50.101 21.48 51.923 ;
     RECT  26.448 51.827 26.472 52.115 ;
     RECT  0.192 51.733 0.312 52.403 ;
     RECT  0.288 52.403 0.312 52.499 ;
     RECT  2.4 49.619 4.056 53.075 ;
     RECT  17.328 42.467 17.352 53.315 ;
     RECT  12.288 50.579 14.136 53.411 ;
     RECT  16.32 48.419 16.344 53.555 ;
     RECT  20.208 51.923 21.48 53.603 ;
     RECT  15.12 50.579 15.144 53.843 ;
     RECT  20.208 53.603 21.336 54.083 ;
     RECT  2.4 53.075 3.96 54.179 ;
     RECT  2.4 54.179 3.768 54.227 ;
     RECT  20.976 54.083 21.336 54.323 ;
     RECT  7.8 42.227 10.056 54.899 ;
     RECT  7.8 54.899 9.384 55.043 ;
     RECT  24 50.867 24.312 55.237 ;
     RECT  12.288 53.411 13.512 55.571 ;
     RECT  0.144 53.893 0.168 56.341 ;
     RECT  2.4 54.227 3.72 56.483 ;
     RECT  0.144 56.341 0.216 56.531 ;
     RECT  23.376 55.237 24.312 57.059 ;
     RECT  2.4 56.483 2.808 57.685 ;
     RECT  18.6 49.235 18.912 57.925 ;
     RECT  21.024 54.323 21.336 57.971 ;
     RECT  7.8 55.043 8.856 58.019 ;
     RECT  0.144 56.531 0.168 58.787 ;
     RECT  2.4 57.685 2.856 58.979 ;
     RECT  6.48 45.731 6.504 60.563 ;
     RECT  21.312 57.971 21.336 60.949 ;
     RECT  18.6 57.925 19.032 61.619 ;
     RECT  21.312 60.949 21.48 61.619 ;
     RECT  21.312 61.619 21.336 61.667 ;
     RECT  2.4 58.979 2.712 62.649 ;
     RECT  7.8 58.019 8.112 62.649 ;
     RECT  13.2 55.571 13.512 62.649 ;
     RECT  18.6 61.619 18.912 62.649 ;
     RECT  24 57.059 24.312 62.649 ;
     RECT  2.4 62.649 2.52 62.663 ;
     RECT  7.8 62.649 7.92 62.663 ;
     RECT  13.2 62.649 13.32 62.663 ;
     RECT  18.6 62.649 18.72 62.663 ;
     RECT  24 62.649 24.12 62.663 ;
  END
END ot_qwen_tree_delay
END LIBRARY
